VERSION 5.7 ;
  NOWIREEXTENSIONATPIN ON ;
  DIVIDERCHAR "/" ;
  BUSBITCHARS "[]" ;
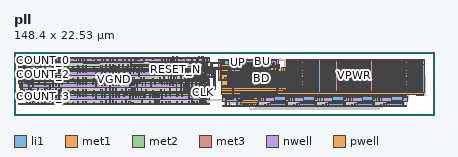
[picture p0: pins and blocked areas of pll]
MACRO pll
  CLASS BLOCK ;
  FOREIGN pll ;
  ORIGIN 0.000 0.000 ;
  SIZE 148.400 BY 22.530 ;
  PIN UP
    ANTENNAGATEAREA 1.341000 ;
    ANTENNADIFFAREA 0.537600 ;
    PORT
      LAYER li1 ;
        RECT 67.955 17.745 68.285 18.755 ;
        RECT 89.010 18.745 89.340 18.910 ;
        RECT 89.005 18.670 89.340 18.745 ;
        RECT 89.005 18.300 89.205 18.670 ;
        RECT 89.005 18.105 89.175 18.300 ;
        RECT 88.940 17.895 89.175 18.105 ;
        RECT 88.940 17.650 89.110 17.895 ;
        RECT 88.400 17.600 89.110 17.650 ;
        RECT 87.750 17.480 89.110 17.600 ;
        RECT 87.750 17.430 88.640 17.480 ;
        RECT 87.750 16.930 87.920 17.430 ;
        RECT 88.310 17.360 88.640 17.430 ;
        RECT 87.130 16.905 87.920 16.930 ;
        RECT 87.065 16.760 87.920 16.905 ;
        RECT 87.065 16.640 87.405 16.760 ;
        RECT 66.385 15.350 66.715 15.440 ;
        RECT 66.045 14.585 66.715 15.350 ;
        RECT 66.045 14.415 67.135 14.585 ;
        RECT 66.045 14.410 66.715 14.415 ;
        RECT 64.085 13.760 64.415 14.240 ;
        RECT 66.045 13.590 66.215 14.410 ;
        RECT 66.965 14.240 67.135 14.415 ;
        RECT 66.965 13.760 67.655 14.240 ;
        RECT 65.965 12.810 66.215 13.590 ;
        RECT 60.645 9.375 60.975 9.745 ;
      LAYER met1 ;
        RECT 88.920 18.415 89.270 18.690 ;
        RECT 67.945 18.240 68.300 18.255 ;
        RECT 67.900 18.010 68.345 18.240 ;
        RECT 67.945 17.980 68.300 18.010 ;
        RECT 66.400 15.105 66.690 15.140 ;
        RECT 64.110 14.935 66.690 15.105 ;
        RECT 64.110 14.275 64.280 14.935 ;
        RECT 66.400 14.900 66.690 14.935 ;
        RECT 64.085 13.985 64.315 14.275 ;
        RECT 67.075 14.030 67.365 14.065 ;
        RECT 67.050 13.740 67.390 14.030 ;
        RECT 67.075 13.705 67.365 13.740 ;
        RECT 61.665 13.105 61.925 13.190 ;
        RECT 67.130 13.105 67.300 13.705 ;
        RECT 61.665 12.935 67.300 13.105 ;
        RECT 61.665 12.860 61.925 12.935 ;
        RECT 60.725 9.545 60.955 9.665 ;
        RECT 61.665 9.545 61.925 9.615 ;
        RECT 60.725 9.375 61.925 9.545 ;
        RECT 61.665 9.285 61.925 9.375 ;
      LAYER met2 ;
        RECT 88.935 18.680 89.270 18.700 ;
        RECT 69.320 18.510 89.270 18.680 ;
        RECT 67.710 17.945 68.345 18.275 ;
        RECT 67.205 14.945 67.375 14.950 ;
        RECT 67.710 14.945 67.880 17.945 ;
        RECT 69.320 14.945 69.490 18.510 ;
        RECT 88.935 18.425 89.270 18.510 ;
        RECT 67.200 14.775 69.490 14.945 ;
        RECT 67.205 14.140 67.375 14.775 ;
        RECT 67.045 14.045 67.375 14.140 ;
        RECT 67.045 13.720 67.390 14.045 ;
        RECT 67.045 13.650 67.375 13.720 ;
        RECT 61.665 12.860 61.925 13.190 ;
        RECT 61.735 9.615 61.905 12.860 ;
        RECT 61.665 9.285 61.925 9.615 ;
    END
  END UP
  PIN BU
    ANTENNAGATEAREA 6.742000 ;
    ANTENNADIFFAREA 0.291200 ;
    PORT
      LAYER li1 ;
        RECT 81.520 17.395 81.740 18.460 ;
        RECT 84.715 17.475 84.885 19.080 ;
        RECT 84.645 17.395 84.990 17.475 ;
        RECT 81.520 17.305 84.990 17.395 ;
        RECT 81.520 17.215 84.885 17.305 ;
        RECT 81.520 16.115 81.740 17.215 ;
        RECT 91.070 17.200 91.600 17.380 ;
      LAYER met1 ;
        RECT 84.655 19.030 85.050 19.035 ;
        RECT 84.655 18.860 91.100 19.030 ;
        RECT 84.655 18.710 85.050 18.860 ;
        RECT 84.655 18.705 85.040 18.710 ;
        RECT 90.930 18.210 91.100 18.860 ;
        RECT 90.930 18.040 91.555 18.210 ;
        RECT 91.385 17.445 91.555 18.040 ;
        RECT 91.385 17.125 91.615 17.445 ;
    END
  END BU
  PIN BD
    ANTENNAGATEAREA 6.805000 ;
    ANTENNADIFFAREA 0.447500 ;
    PORT
      LAYER li1 ;
        RECT 77.255 17.395 77.465 18.960 ;
        RECT 77.115 17.215 80.195 17.395 ;
        RECT 77.115 16.930 77.285 17.215 ;
        RECT 76.175 16.760 77.285 16.930 ;
        RECT 76.175 15.710 76.375 16.760 ;
        RECT 81.415 15.740 81.760 15.910 ;
        RECT 75.930 15.530 76.375 15.710 ;
        RECT 84.790 15.630 84.960 15.975 ;
        RECT 93.030 15.740 93.260 15.885 ;
        RECT 92.955 15.565 93.335 15.740 ;
      LAYER met1 ;
        RECT 79.820 17.130 80.215 17.455 ;
        RECT 80.025 15.945 80.215 17.130 ;
        RECT 80.025 15.790 81.790 15.945 ;
        RECT 84.700 15.790 85.095 15.945 ;
        RECT 92.985 15.790 93.285 15.910 ;
        RECT 80.025 15.770 93.285 15.790 ;
        RECT 81.320 15.620 93.285 15.770 ;
    END
  END BD
  PIN RESET_OUT_N
    ANTENNAGATEAREA 0.232500 ;
    ANTENNADIFFAREA 0.543200 ;
    PORT
      LAYER li1 ;
        RECT 55.815 18.555 56.145 19.715 ;
        RECT 41.035 18.085 41.365 18.515 ;
        RECT 55.975 17.865 56.145 18.555 ;
        RECT 55.900 17.065 56.230 17.865 ;
      LAYER met1 ;
        RECT 55.890 19.415 56.220 19.675 ;
        RECT 55.975 18.870 56.145 19.415 ;
        RECT 55.890 18.610 56.220 18.870 ;
        RECT 41.010 18.160 41.270 18.490 ;
        RECT 41.100 17.690 41.270 18.160 ;
        RECT 55.935 17.690 56.195 17.815 ;
        RECT 41.100 17.520 56.195 17.690 ;
        RECT 55.935 17.485 56.195 17.520 ;
      LAYER met2 ;
        RECT 55.885 20.550 56.245 20.780 ;
        RECT 55.895 20.400 56.245 20.550 ;
        RECT 55.970 19.675 56.180 20.400 ;
        RECT 55.890 19.415 56.220 19.675 ;
        RECT 55.890 18.610 56.220 18.870 ;
        RECT 55.990 17.815 56.160 18.610 ;
        RECT 55.935 17.485 56.195 17.815 ;
    END
  END RESET_OUT_N
  PIN DOWN_N
    ANTENNAGATEAREA 0.252000 ;
    ANTENNADIFFAREA 0.541300 ;
    PORT
      LAYER li1 ;
        RECT 87.100 17.205 87.470 17.435 ;
        RECT 88.960 16.655 89.160 17.005 ;
        RECT 67.825 8.545 68.155 11.175 ;
      LAYER met1 ;
        RECT 87.125 17.345 87.480 17.440 ;
        RECT 87.125 17.175 87.745 17.345 ;
        RECT 87.585 16.515 87.745 17.175 ;
        RECT 88.905 16.685 89.255 16.970 ;
        RECT 88.920 16.515 89.080 16.685 ;
        RECT 87.585 16.345 89.100 16.515 ;
        RECT 67.830 10.335 68.150 10.655 ;
      LAYER met2 ;
        RECT 88.895 16.755 89.255 16.965 ;
        RECT 70.535 16.585 89.255 16.755 ;
        RECT 67.815 10.315 68.195 10.640 ;
        RECT 68.025 9.750 68.195 10.315 ;
        RECT 70.535 9.750 70.705 16.585 ;
        RECT 68.025 9.580 70.705 9.750 ;
    END
  END DOWN_N
  PIN UP_N
    ANTENNAGATEAREA 0.252000 ;
    ANTENNADIFFAREA 0.541300 ;
    PORT
      LAYER li1 ;
        RECT 90.620 17.110 90.850 17.480 ;
        RECT 88.430 16.690 88.700 17.020 ;
        RECT 67.825 12.810 68.155 15.440 ;
      LAYER met1 ;
        RECT 90.570 17.310 90.925 17.415 ;
        RECT 88.520 17.140 90.925 17.310 ;
        RECT 88.520 17.005 88.680 17.140 ;
        RECT 88.390 16.655 88.680 17.005 ;
        RECT 67.905 13.785 68.180 14.110 ;
      LAYER met2 ;
        RECT 69.900 18.095 89.245 18.265 ;
        RECT 67.870 13.785 68.210 14.110 ;
        RECT 68.000 13.500 68.170 13.785 ;
        RECT 69.900 13.500 70.070 18.095 ;
        RECT 89.075 17.430 89.245 18.095 ;
        RECT 89.075 17.260 90.895 17.430 ;
        RECT 90.555 17.155 90.895 17.260 ;
        RECT 68.000 13.330 70.070 13.500 ;
    END
  END UP_N
  PIN DOWN
    ANTENNAGATEAREA 1.341000 ;
    ANTENNADIFFAREA 0.537600 ;
    PORT
      LAYER li1 ;
        RECT 89.285 17.410 90.450 17.580 ;
        RECT 89.285 17.375 89.615 17.410 ;
        RECT 90.280 16.940 90.450 17.410 ;
        RECT 90.280 16.770 90.910 16.940 ;
        RECT 90.560 16.675 90.905 16.770 ;
        RECT 66.385 11.085 66.715 11.175 ;
        RECT 66.045 10.320 66.715 11.085 ;
        RECT 66.045 10.150 67.135 10.320 ;
        RECT 66.045 10.145 66.715 10.150 ;
        RECT 59.745 9.375 60.075 9.745 ;
        RECT 64.085 9.495 64.415 9.975 ;
        RECT 66.045 9.325 66.215 10.145 ;
        RECT 66.965 9.975 67.135 10.150 ;
        RECT 66.965 9.495 67.655 9.975 ;
        RECT 65.965 8.545 66.215 9.325 ;
        RECT 62.675 4.935 63.005 5.945 ;
      LAYER met1 ;
        RECT 90.560 16.660 90.910 16.945 ;
        RECT 66.400 10.840 66.690 10.875 ;
        RECT 59.755 10.380 60.015 10.710 ;
        RECT 64.110 10.670 66.690 10.840 ;
        RECT 59.800 9.665 59.970 10.380 ;
        RECT 64.110 10.010 64.280 10.670 ;
        RECT 66.400 10.635 66.690 10.670 ;
        RECT 64.085 9.720 64.315 10.010 ;
        RECT 67.070 9.775 67.370 9.780 ;
        RECT 59.765 9.375 59.995 9.665 ;
        RECT 67.030 9.470 67.395 9.775 ;
        RECT 67.070 9.460 67.370 9.470 ;
        RECT 61.665 8.840 61.925 8.925 ;
        RECT 67.130 8.840 67.300 9.460 ;
        RECT 61.665 8.670 67.300 8.840 ;
        RECT 61.665 8.595 61.925 8.670 ;
        RECT 62.585 5.650 63.040 5.955 ;
      LAYER met2 ;
        RECT 90.570 16.850 90.910 16.940 ;
        RECT 90.565 16.660 90.910 16.850 ;
        RECT 90.565 16.340 90.735 16.660 ;
        RECT 71.025 16.170 90.735 16.340 ;
        RECT 59.755 10.380 60.015 10.710 ;
        RECT 59.785 8.845 59.955 10.380 ;
        RECT 67.045 9.440 67.425 9.765 ;
        RECT 67.255 9.335 67.425 9.440 ;
        RECT 71.025 9.335 71.195 16.170 ;
        RECT 67.255 9.165 71.195 9.335 ;
        RECT 61.665 8.845 61.925 8.925 ;
        RECT 59.785 8.675 61.925 8.845 ;
        RECT 61.665 8.595 61.925 8.675 ;
        RECT 61.755 5.940 61.925 8.595 ;
        RECT 61.755 5.770 62.955 5.940 ;
        RECT 62.625 5.680 62.955 5.770 ;
    END
  END DOWN
  PIN CLK
    ANTENNADIFFAREA 0.924000 ;
    PORT
      LAYER li1 ;
        RECT 66.415 6.015 66.695 6.905 ;
        RECT 67.345 6.015 67.675 6.905 ;
        RECT 66.415 5.845 67.675 6.015 ;
        RECT 66.415 5.075 66.585 5.845 ;
        RECT 66.415 4.905 67.630 5.075 ;
        RECT 66.440 4.275 66.770 4.905 ;
        RECT 67.300 4.275 67.630 4.905 ;
      LAYER met1 ;
        RECT 66.370 4.680 66.890 4.985 ;
      LAYER met2 ;
        RECT 66.410 20.515 66.895 20.775 ;
        RECT 66.510 4.985 66.760 20.515 ;
        RECT 66.370 4.680 66.890 4.985 ;
    END
  END CLK
  PIN COUNT_0
    ANTENNAGATEAREA 0.540000 ;
    PORT
      LAYER li1 ;
        RECT 3.605 18.085 4.005 18.515 ;
        RECT 11.545 17.955 11.885 18.285 ;
        RECT 11.715 17.715 11.885 17.955 ;
        RECT 12.655 17.715 12.985 18.285 ;
        RECT 11.715 17.545 12.985 17.715 ;
      LAYER met1 ;
        RECT 3.710 18.235 4.040 18.535 ;
        RECT 12.725 17.945 13.055 18.245 ;
      LAYER met2 ;
        RECT 3.690 20.540 4.060 20.920 ;
        RECT 3.890 19.015 4.060 20.540 ;
        RECT 3.890 18.845 12.875 19.015 ;
        RECT 3.890 18.570 4.060 18.845 ;
        RECT 3.690 18.190 4.060 18.570 ;
        RECT 12.705 18.280 12.875 18.845 ;
        RECT 12.705 17.900 13.075 18.280 ;
    END
  END COUNT_0
  PIN COUNT_1
    ANTENNAGATEAREA 0.540000 ;
    PORT
      LAYER li1 ;
        RECT 3.105 18.085 3.435 18.885 ;
        RECT 11.545 13.680 11.885 14.010 ;
        RECT 11.715 13.440 11.885 13.680 ;
        RECT 12.655 13.440 12.985 14.010 ;
        RECT 11.715 13.270 12.985 13.440 ;
      LAYER met1 ;
        RECT 3.100 18.050 3.430 18.350 ;
        RECT 3.280 15.205 12.880 15.375 ;
        RECT 3.280 14.920 3.660 15.205 ;
        RECT 12.710 13.920 12.880 15.205 ;
        RECT 12.710 13.590 12.970 13.920 ;
      LAYER met2 ;
        RECT 3.080 20.535 3.450 20.915 ;
        RECT 3.165 18.385 3.335 20.535 ;
        RECT 3.080 18.005 3.450 18.385 ;
        RECT 3.280 15.290 3.450 18.005 ;
        RECT 3.280 14.920 3.660 15.290 ;
    END
  END COUNT_1
  PIN COUNT_3
    ANTENNAGATEAREA 0.540000 ;
    PORT
      LAYER li1 ;
        RECT 1.685 17.915 2.100 18.285 ;
        RECT 11.545 5.145 11.885 5.475 ;
        RECT 11.715 4.905 11.885 5.145 ;
        RECT 12.655 4.905 12.985 5.475 ;
        RECT 11.715 4.735 12.985 4.905 ;
      LAYER met1 ;
        RECT 1.725 17.975 2.055 18.275 ;
        RECT 4.015 6.570 4.395 6.715 ;
        RECT 4.015 6.400 12.880 6.570 ;
        RECT 4.015 6.345 4.395 6.400 ;
        RECT 12.710 5.385 12.880 6.400 ;
        RECT 12.710 5.055 12.970 5.385 ;
      LAYER met2 ;
        RECT 1.705 20.535 2.075 20.915 ;
        RECT 1.710 20.530 2.070 20.535 ;
        RECT 1.890 18.310 2.060 20.530 ;
        RECT 1.705 17.930 2.075 18.310 ;
        RECT 1.905 12.570 2.075 17.930 ;
        RECT 1.905 12.400 2.835 12.570 ;
        RECT 2.665 6.715 2.835 12.400 ;
        RECT 2.665 6.545 4.395 6.715 ;
        RECT 4.015 6.345 4.395 6.545 ;
    END
  END COUNT_3
  PIN COUNT_2
    ANTENNAGATEAREA 0.540000 ;
    PORT
      LAYER li1 ;
        RECT 2.535 18.085 2.875 19.625 ;
        RECT 11.545 9.415 11.885 9.745 ;
        RECT 11.715 9.175 11.885 9.415 ;
        RECT 12.655 9.175 12.985 9.745 ;
        RECT 11.715 9.005 12.985 9.175 ;
      LAYER met1 ;
        RECT 2.615 18.375 2.785 18.385 ;
        RECT 2.485 18.075 2.815 18.375 ;
        RECT 2.615 17.645 2.785 18.075 ;
        RECT 2.615 17.475 5.210 17.645 ;
        RECT 4.830 17.275 5.210 17.475 ;
        RECT 4.895 10.955 5.265 11.015 ;
        RECT 4.895 10.830 7.685 10.955 ;
        RECT 4.895 10.785 12.880 10.830 ;
        RECT 4.895 10.635 5.265 10.785 ;
        RECT 7.385 10.660 12.880 10.785 ;
        RECT 12.710 9.635 12.880 10.660 ;
        RECT 12.710 9.305 12.970 9.635 ;
      LAYER met2 ;
        RECT 2.465 20.530 2.835 20.910 ;
        RECT 2.550 18.410 2.720 20.530 ;
        RECT 2.465 18.030 2.835 18.410 ;
        RECT 4.830 17.275 5.210 17.645 ;
        RECT 5.015 11.015 5.185 17.275 ;
        RECT 4.895 10.635 5.265 11.015 ;
    END
  END COUNT_2
  PIN RESET_N
    ANTENNAGATEAREA 0.279000 ;
    PORT
      LAYER li1 ;
        RECT 56.885 13.760 57.575 14.240 ;
      LAYER met1 ;
        RECT 57.565 19.415 57.895 19.675 ;
        RECT 57.650 18.870 57.820 19.415 ;
        RECT 57.565 18.610 57.895 18.870 ;
        RECT 56.870 13.980 57.130 14.310 ;
      LAYER met2 ;
        RECT 57.560 20.550 57.920 20.780 ;
        RECT 57.570 20.400 57.920 20.550 ;
        RECT 57.645 19.675 57.855 20.400 ;
        RECT 57.565 19.415 57.895 19.675 ;
        RECT 57.565 18.610 57.895 18.870 ;
        RECT 57.625 17.965 57.795 18.610 ;
        RECT 56.915 17.820 57.795 17.965 ;
        RECT 56.915 14.310 57.085 17.820 ;
        RECT 56.870 13.980 57.130 14.310 ;
    END
  END RESET_N
  PIN VCTRL
    ANTENNAGATEAREA 1.241700 ;
    ANTENNADIFFAREA 1.913700 ;
    PORT
      LAYER li1 ;
        RECT 91.770 17.330 91.945 18.710 ;
        RECT 92.610 17.670 92.785 19.005 ;
        RECT 92.610 17.340 93.880 17.670 ;
        RECT 92.610 17.330 92.810 17.340 ;
        RECT 91.770 17.160 92.810 17.330 ;
        RECT 91.770 15.905 91.945 17.160 ;
        RECT 92.610 16.600 92.785 17.160 ;
        RECT 92.610 16.135 93.090 16.600 ;
        RECT 93.520 16.495 93.880 17.340 ;
        RECT 92.610 15.810 92.795 16.135 ;
        RECT 79.120 5.355 79.890 6.230 ;
        RECT 79.120 5.020 80.405 5.355 ;
        RECT 79.120 3.430 79.890 5.020 ;
      LAYER met1 ;
        RECT 92.530 17.140 92.880 17.425 ;
        RECT 86.655 12.500 86.795 14.165 ;
        RECT 87.215 12.500 87.355 14.165 ;
        RECT 87.775 12.500 87.915 14.165 ;
        RECT 88.145 12.500 88.415 14.165 ;
        RECT 88.645 12.500 88.785 14.165 ;
        RECT 89.205 12.500 89.345 14.165 ;
        RECT 89.765 12.500 89.905 14.165 ;
        RECT 86.655 12.180 89.905 12.500 ;
        RECT 86.655 10.515 86.795 12.180 ;
        RECT 87.215 10.515 87.355 12.180 ;
        RECT 87.775 10.515 87.915 12.180 ;
        RECT 88.145 10.515 88.415 12.180 ;
        RECT 88.645 10.515 88.785 12.180 ;
        RECT 89.205 10.515 89.345 12.180 ;
        RECT 89.765 10.515 89.905 12.180 ;
        RECT 91.380 12.500 91.520 14.165 ;
        RECT 91.940 12.500 92.080 14.165 ;
        RECT 92.500 12.500 92.640 14.165 ;
        RECT 92.870 12.500 93.140 14.165 ;
        RECT 93.370 12.500 93.510 14.165 ;
        RECT 93.930 12.500 94.070 14.165 ;
        RECT 94.490 12.500 94.630 14.165 ;
        RECT 91.380 12.180 94.630 12.500 ;
        RECT 91.380 10.515 91.520 12.180 ;
        RECT 91.940 10.515 92.080 12.180 ;
        RECT 92.500 10.515 92.640 12.180 ;
        RECT 92.870 10.515 93.140 12.180 ;
        RECT 93.370 10.515 93.510 12.180 ;
        RECT 93.930 10.515 94.070 12.180 ;
        RECT 94.490 10.515 94.630 12.180 ;
        RECT 80.155 5.375 80.470 5.410 ;
        RECT 80.155 5.070 80.475 5.375 ;
      LAYER met2 ;
        RECT 92.550 17.425 93.135 17.430 ;
        RECT 92.465 17.140 93.135 17.425 ;
        RECT 92.550 17.130 93.135 17.140 ;
        RECT 92.870 14.635 93.135 17.130 ;
        RECT 88.145 14.165 88.415 14.635 ;
        RECT 92.870 14.165 93.140 14.635 ;
        RECT 86.560 14.025 90.000 14.165 ;
        RECT 91.285 14.025 94.725 14.165 ;
        RECT 88.140 13.605 88.420 14.025 ;
        RECT 92.865 13.605 93.145 14.025 ;
        RECT 86.560 13.465 90.000 13.605 ;
        RECT 91.285 13.465 94.725 13.605 ;
        RECT 88.140 13.045 88.420 13.465 ;
        RECT 92.865 13.045 93.145 13.465 ;
        RECT 86.560 12.905 90.000 13.045 ;
        RECT 91.285 12.905 94.725 13.045 ;
        RECT 88.140 12.480 88.420 12.905 ;
        RECT 92.865 12.480 93.145 12.905 ;
        RECT 86.460 12.475 90.100 12.480 ;
        RECT 91.185 12.475 94.825 12.480 ;
        RECT 86.090 12.205 95.195 12.475 ;
        RECT 86.460 12.200 90.100 12.205 ;
        RECT 91.185 12.200 94.825 12.205 ;
        RECT 88.140 11.775 88.420 12.200 ;
        RECT 92.865 11.775 93.145 12.200 ;
        RECT 86.560 11.635 90.000 11.775 ;
        RECT 91.285 11.635 94.725 11.775 ;
        RECT 88.140 11.215 88.420 11.635 ;
        RECT 92.865 11.215 93.145 11.635 ;
        RECT 86.560 11.075 90.000 11.215 ;
        RECT 91.285 11.075 94.725 11.215 ;
        RECT 88.140 10.655 88.420 11.075 ;
        RECT 92.865 10.655 93.145 11.075 ;
        RECT 86.560 10.515 90.000 10.655 ;
        RECT 91.285 10.515 94.725 10.655 ;
        RECT 88.145 10.045 88.415 10.515 ;
        RECT 92.870 8.005 93.140 10.515 ;
        RECT 92.870 7.960 93.145 8.005 ;
        RECT 92.875 7.720 93.145 7.960 ;
        RECT 80.080 7.550 93.145 7.720 ;
        RECT 80.080 5.385 80.250 7.550 ;
        RECT 80.080 5.100 80.515 5.385 ;
        RECT 80.130 5.065 80.515 5.100 ;
      LAYER met3 ;
        RECT 86.720 12.505 87.020 14.005 ;
        RECT 88.115 12.505 88.445 14.005 ;
        RECT 89.540 12.505 89.840 14.005 ;
        RECT 86.720 12.175 89.840 12.505 ;
        RECT 86.720 10.675 87.020 12.175 ;
        RECT 88.115 10.675 88.445 12.175 ;
        RECT 89.540 10.675 89.840 12.175 ;
        RECT 91.445 12.505 91.745 14.005 ;
        RECT 92.840 12.505 93.170 14.005 ;
        RECT 94.265 12.505 94.565 14.005 ;
        RECT 91.445 12.175 94.565 12.505 ;
        RECT 91.445 10.675 91.745 12.175 ;
        RECT 92.840 10.675 93.170 12.175 ;
        RECT 94.265 10.675 94.565 12.175 ;
    END
  END VCTRL
  PIN REFCLK
    ANTENNAGATEAREA 0.558000 ;
    PORT
      LAYER li1 ;
        RECT 66.965 17.915 67.445 18.285 ;
        RECT 64.945 13.760 65.275 14.240 ;
      LAYER met1 ;
        RECT 65.150 18.240 65.505 18.255 ;
        RECT 67.195 18.240 67.435 18.255 ;
        RECT 65.135 18.205 65.580 18.240 ;
        RECT 67.035 18.205 67.480 18.240 ;
        RECT 65.135 18.035 67.480 18.205 ;
        RECT 65.135 18.010 65.580 18.035 ;
        RECT 67.035 18.010 67.480 18.035 ;
        RECT 65.150 17.980 65.505 18.010 ;
        RECT 67.195 17.995 67.435 18.010 ;
        RECT 64.930 14.240 65.285 14.255 ;
        RECT 64.885 14.010 65.330 14.240 ;
        RECT 64.930 13.980 65.285 14.010 ;
      LAYER met2 ;
        RECT 65.045 20.770 65.530 20.775 ;
        RECT 65.040 20.515 65.530 20.770 ;
        RECT 65.040 20.510 65.525 20.515 ;
        RECT 65.100 18.275 65.270 20.510 ;
        RECT 65.100 17.945 65.595 18.275 ;
        RECT 65.100 14.290 65.270 17.945 ;
        RECT 64.860 13.960 65.350 14.290 ;
    END
  END REFCLK
  PIN VPWR
    USE POWER ;
    PORT
      LAYER nwell ;
        RECT 1.850 9.855 68.950 11.715 ;
        RECT 24.575 9.815 30.220 9.855 ;
        RECT 28.700 9.750 30.220 9.815 ;
        RECT 47.300 9.815 52.945 9.855 ;
        RECT 47.300 9.750 48.820 9.815 ;
      LAYER li1 ;
        RECT 2.040 11.440 68.760 11.610 ;
        RECT 2.295 10.015 2.625 11.440 ;
        RECT 5.035 10.145 5.365 11.440 ;
        RECT 6.685 10.135 7.015 11.440 ;
        RECT 8.615 10.845 9.055 11.440 ;
        RECT 10.850 10.595 11.180 11.440 ;
        RECT 13.495 10.015 13.825 11.440 ;
        RECT 14.610 10.400 14.910 11.440 ;
        RECT 15.620 10.225 15.950 11.440 ;
        RECT 16.630 10.715 16.960 11.440 ;
        RECT 19.030 11.160 19.360 11.440 ;
        RECT 21.250 11.160 21.585 11.440 ;
        RECT 22.345 10.485 22.515 11.440 ;
        RECT 23.275 10.715 23.525 11.440 ;
        RECT 24.255 10.845 24.505 11.440 ;
        RECT 25.185 10.845 25.515 11.440 ;
        RECT 27.600 10.950 27.945 11.440 ;
        RECT 28.940 9.935 29.190 11.440 ;
        RECT 30.995 10.530 31.220 11.440 ;
        RECT 31.970 10.300 32.185 11.440 ;
        RECT 33.770 10.015 34.065 11.440 ;
        RECT 34.770 10.400 35.070 11.440 ;
        RECT 35.840 10.385 36.170 11.440 ;
        RECT 36.875 10.385 37.210 11.440 ;
        RECT 38.705 10.845 39.145 11.440 ;
        RECT 40.745 10.135 41.075 11.440 ;
        RECT 41.490 10.400 41.790 11.440 ;
        RECT 41.970 10.400 42.270 11.440 ;
        RECT 42.450 10.400 42.750 11.440 ;
        RECT 43.455 10.015 43.750 11.440 ;
        RECT 45.335 10.300 45.550 11.440 ;
        RECT 46.300 10.530 46.525 11.440 ;
        RECT 48.330 9.935 48.580 11.440 ;
        RECT 49.575 10.950 49.920 11.440 ;
        RECT 52.005 10.845 52.335 11.440 ;
        RECT 53.015 10.845 53.265 11.440 ;
        RECT 53.995 10.715 54.245 11.440 ;
        RECT 55.040 10.385 55.370 11.440 ;
        RECT 56.075 10.385 56.410 11.440 ;
        RECT 57.245 10.145 57.575 11.440 ;
        RECT 58.685 10.145 59.015 11.440 ;
        RECT 59.745 10.015 60.075 11.440 ;
        RECT 60.645 10.015 60.975 11.440 ;
        RECT 61.195 10.145 61.525 11.440 ;
        RECT 62.635 10.145 62.965 11.440 ;
        RECT 64.075 10.145 64.405 11.440 ;
        RECT 65.515 10.145 65.845 11.440 ;
        RECT 67.325 10.145 67.655 11.440 ;
        RECT 68.370 10.400 68.670 11.440 ;
      LAYER met1 ;
        RECT 2.040 11.280 68.760 11.770 ;
      LAYER met2 ;
        RECT 2.040 11.285 2.520 11.770 ;
        RECT 2.975 11.280 3.885 11.770 ;
        RECT 4.375 11.290 4.875 11.775 ;
        RECT 6.495 11.290 10.640 11.770 ;
        RECT 11.185 11.270 22.615 11.770 ;
        RECT 23.160 11.295 25.095 11.670 ;
        RECT 25.585 11.275 30.910 11.770 ;
        RECT 31.470 11.310 36.105 11.770 ;
        RECT 36.570 11.290 38.980 11.765 ;
        RECT 40.195 11.310 43.265 11.780 ;
        RECT 44.810 11.295 51.555 11.765 ;
        RECT 52.015 11.290 53.755 11.770 ;
        RECT 54.240 11.295 54.865 11.770 ;
        RECT 55.370 11.280 55.790 11.775 ;
        RECT 56.295 11.270 56.790 11.765 ;
        RECT 57.335 11.290 58.030 11.780 ;
        RECT 58.685 11.285 59.165 11.770 ;
        RECT 59.655 11.275 60.550 11.765 ;
        RECT 62.080 11.300 63.985 11.765 ;
        RECT 64.490 11.295 66.345 11.770 ;
        RECT 66.915 11.295 68.735 11.760 ;
      LAYER met3 ;
        RECT 2.800 11.765 68.980 11.775 ;
        RECT 2.055 11.760 68.980 11.765 ;
        RECT 1.560 11.285 68.980 11.760 ;
        RECT 1.560 11.280 68.765 11.285 ;
    END
    PORT
      LAYER nwell ;
        RECT 2.330 14.120 68.950 15.980 ;
        RECT 24.575 14.080 30.220 14.120 ;
        RECT 45.215 14.080 50.860 14.120 ;
        RECT 28.700 14.015 30.220 14.080 ;
        RECT 49.340 14.015 50.860 14.080 ;
      LAYER li1 ;
        RECT 2.520 15.705 68.760 15.875 ;
        RECT 3.005 14.410 3.335 15.705 ;
        RECT 5.125 14.750 5.745 15.705 ;
        RECT 6.685 14.400 7.015 15.705 ;
        RECT 8.615 15.110 9.055 15.705 ;
        RECT 10.850 14.860 11.180 15.705 ;
        RECT 13.495 14.280 13.825 15.705 ;
        RECT 14.610 14.665 14.910 15.705 ;
        RECT 15.620 14.490 15.950 15.705 ;
        RECT 16.630 14.980 16.960 15.705 ;
        RECT 19.030 15.425 19.360 15.705 ;
        RECT 21.250 15.425 21.585 15.705 ;
        RECT 22.345 14.750 22.515 15.705 ;
        RECT 23.275 14.980 23.525 15.705 ;
        RECT 24.255 15.110 24.505 15.705 ;
        RECT 25.185 15.110 25.515 15.705 ;
        RECT 27.600 15.215 27.945 15.705 ;
        RECT 28.940 14.200 29.190 15.705 ;
        RECT 30.995 14.795 31.220 15.705 ;
        RECT 31.970 14.565 32.185 15.705 ;
        RECT 33.770 14.280 34.065 15.705 ;
        RECT 34.770 14.665 35.070 15.705 ;
        RECT 35.840 14.650 36.170 15.705 ;
        RECT 36.875 14.650 37.210 15.705 ;
        RECT 38.705 15.110 39.145 15.705 ;
        RECT 40.745 14.400 41.075 15.705 ;
        RECT 42.050 14.750 42.315 15.705 ;
        RECT 43.135 15.110 43.470 15.705 ;
        RECT 43.915 14.980 44.165 15.705 ;
        RECT 44.895 15.110 45.145 15.705 ;
        RECT 45.825 15.110 46.155 15.705 ;
        RECT 48.240 15.215 48.585 15.705 ;
        RECT 43.925 13.460 44.320 14.655 ;
        RECT 49.580 14.200 49.830 15.705 ;
        RECT 51.635 14.795 51.860 15.705 ;
        RECT 52.610 14.565 52.825 15.705 ;
        RECT 54.410 14.280 54.705 15.705 ;
        RECT 56.315 14.410 56.645 15.705 ;
        RECT 57.245 14.410 57.575 15.705 ;
        RECT 58.685 14.410 59.015 15.705 ;
        RECT 60.125 14.410 60.455 15.705 ;
        RECT 61.195 14.410 61.525 15.705 ;
        RECT 62.635 14.410 62.965 15.705 ;
        RECT 64.075 14.410 64.405 15.705 ;
        RECT 65.515 14.410 65.845 15.705 ;
        RECT 67.325 14.410 67.655 15.705 ;
        RECT 68.370 14.665 68.670 15.705 ;
      LAYER met1 ;
        RECT 2.800 16.035 68.970 16.050 ;
        RECT 2.520 15.550 68.970 16.035 ;
        RECT 2.520 15.545 68.760 15.550 ;
        RECT 44.015 14.695 44.185 15.545 ;
        RECT 43.975 14.365 44.235 14.695 ;
      LAYER met2 ;
        RECT 2.530 15.550 3.080 16.030 ;
        RECT 4.450 15.555 4.855 16.015 ;
        RECT 5.930 15.545 8.790 16.045 ;
        RECT 9.340 15.535 10.650 16.020 ;
        RECT 11.115 15.545 22.560 16.035 ;
        RECT 23.230 15.540 25.125 16.040 ;
        RECT 25.675 15.555 30.930 16.045 ;
        RECT 31.390 15.560 34.210 16.030 ;
        RECT 34.680 15.550 36.100 16.030 ;
        RECT 36.570 15.550 39.525 16.035 ;
        RECT 40.185 15.545 42.265 16.035 ;
        RECT 42.880 15.560 56.175 16.030 ;
        RECT 57.290 15.555 58.060 16.035 ;
        RECT 58.725 15.535 63.890 16.045 ;
        RECT 64.550 15.555 64.935 16.035 ;
        RECT 65.470 15.550 66.310 16.035 ;
        RECT 67.085 15.555 67.565 16.030 ;
        RECT 68.200 15.530 68.770 16.020 ;
      LAYER met3 ;
        RECT 2.800 16.030 68.980 16.050 ;
        RECT 1.560 16.020 68.980 16.030 ;
        RECT 1.560 15.550 69.115 16.020 ;
        RECT 2.515 15.545 69.115 15.550 ;
        RECT 2.865 15.535 69.115 15.545 ;
    END
    PORT
      LAYER pwell ;
        RECT 75.055 16.920 75.985 16.925 ;
        RECT 77.685 16.920 80.465 17.105 ;
        RECT 75.055 16.700 80.465 16.920 ;
        RECT 81.910 16.700 86.790 17.105 ;
        RECT 75.055 16.625 86.790 16.700 ;
        RECT 91.180 16.625 92.950 17.030 ;
        RECT 75.055 15.450 88.535 16.625 ;
        RECT 89.435 15.450 92.950 16.625 ;
        RECT 94.600 15.450 95.950 16.720 ;
        RECT 73.870 15.205 96.015 15.450 ;
        RECT 74.940 14.870 95.825 15.205 ;
        RECT 95.395 7.995 95.825 14.870 ;
        RECT 107.730 7.895 108.160 19.690 ;
        RECT 119.985 7.895 120.415 19.690 ;
        RECT 132.245 7.895 132.675 19.690 ;
        RECT 144.485 7.905 144.915 17.965 ;
      LAYER li1 ;
        RECT 96.110 19.325 107.520 19.655 ;
        RECT 96.110 18.795 96.440 19.325 ;
        RECT 107.190 18.795 107.520 19.325 ;
        RECT 96.110 18.625 101.510 18.795 ;
        RECT 102.120 18.625 107.520 18.795 ;
        RECT 96.110 18.095 96.440 18.625 ;
        RECT 107.190 18.095 107.520 18.625 ;
        RECT 96.110 17.925 101.510 18.095 ;
        RECT 102.120 17.925 107.520 18.095 ;
        RECT 76.615 15.290 76.785 16.590 ;
        RECT 77.855 15.290 80.295 17.035 ;
        RECT 80.480 16.600 80.650 17.510 ;
        RECT 96.110 17.395 96.440 17.925 ;
        RECT 107.190 17.395 107.520 17.925 ;
        RECT 96.110 17.225 101.510 17.395 ;
        RECT 102.120 17.225 107.520 17.395 ;
        RECT 80.480 16.150 80.935 16.600 ;
        RECT 80.540 15.290 80.935 16.150 ;
        RECT 82.080 15.290 84.530 17.045 ;
        RECT 96.110 16.695 96.440 17.225 ;
        RECT 107.190 16.695 107.520 17.225 ;
        RECT 96.110 16.525 101.510 16.695 ;
        RECT 102.120 16.525 107.520 16.695 ;
        RECT 87.350 15.290 87.945 16.460 ;
        RECT 90.025 15.290 90.615 16.460 ;
        RECT 95.185 15.345 95.370 16.480 ;
        RECT 96.110 15.995 96.440 16.525 ;
        RECT 107.190 15.995 107.520 16.525 ;
        RECT 96.110 15.825 101.510 15.995 ;
        RECT 102.120 15.825 107.520 15.995 ;
        RECT 96.110 15.345 96.440 15.825 ;
        RECT 95.130 15.295 96.440 15.345 ;
        RECT 107.190 15.295 107.520 15.825 ;
        RECT 95.130 15.290 101.510 15.295 ;
        RECT 73.380 15.125 101.510 15.290 ;
        RECT 102.120 15.125 107.520 15.295 ;
        RECT 73.380 14.960 96.440 15.125 ;
        RECT 95.130 14.950 96.440 14.960 ;
        RECT 74.400 12.620 75.025 13.310 ;
        RECT 75.295 10.045 79.675 14.635 ;
        RECT 80.165 10.045 84.545 14.635 ;
        RECT 86.090 10.045 90.470 14.635 ;
        RECT 90.815 10.045 95.195 14.635 ;
        RECT 96.110 14.595 96.440 14.950 ;
        RECT 107.190 14.595 107.520 15.125 ;
        RECT 95.415 8.125 95.830 14.520 ;
        RECT 96.110 14.425 101.510 14.595 ;
        RECT 102.120 14.425 107.520 14.595 ;
        RECT 96.110 13.895 96.440 14.425 ;
        RECT 107.190 13.895 107.520 14.425 ;
        RECT 96.110 13.725 101.510 13.895 ;
        RECT 102.120 13.725 107.520 13.895 ;
        RECT 96.110 13.195 96.440 13.725 ;
        RECT 107.190 13.195 107.520 13.725 ;
        RECT 96.110 13.025 101.510 13.195 ;
        RECT 102.120 13.025 107.520 13.195 ;
        RECT 96.110 12.495 96.440 13.025 ;
        RECT 107.190 12.495 107.520 13.025 ;
        RECT 96.110 12.325 101.510 12.495 ;
        RECT 102.120 12.325 107.520 12.495 ;
        RECT 96.110 11.795 96.440 12.325 ;
        RECT 107.190 11.795 107.520 12.325 ;
        RECT 96.110 11.625 101.510 11.795 ;
        RECT 102.120 11.625 107.520 11.795 ;
        RECT 96.110 11.095 96.440 11.625 ;
        RECT 107.190 11.095 107.520 11.625 ;
        RECT 96.110 10.925 101.510 11.095 ;
        RECT 102.120 10.925 107.520 11.095 ;
        RECT 96.110 10.395 96.440 10.925 ;
        RECT 107.190 10.395 107.520 10.925 ;
        RECT 96.110 10.225 101.510 10.395 ;
        RECT 102.120 10.225 107.520 10.395 ;
        RECT 96.110 9.695 96.440 10.225 ;
        RECT 107.190 9.695 107.520 10.225 ;
        RECT 96.110 9.525 101.510 9.695 ;
        RECT 102.120 9.525 107.520 9.695 ;
        RECT 96.110 8.995 96.440 9.525 ;
        RECT 107.190 8.995 107.520 9.525 ;
        RECT 96.110 8.825 101.510 8.995 ;
        RECT 102.120 8.825 107.520 8.995 ;
        RECT 96.110 8.295 96.440 8.825 ;
        RECT 107.190 8.295 107.520 8.825 ;
        RECT 96.110 7.965 107.520 8.295 ;
        RECT 107.750 8.025 108.165 19.560 ;
        RECT 108.335 19.325 119.745 19.655 ;
        RECT 108.335 18.795 108.665 19.325 ;
        RECT 119.415 18.795 119.745 19.325 ;
        RECT 108.335 18.625 113.735 18.795 ;
        RECT 114.345 18.625 119.745 18.795 ;
        RECT 108.335 18.095 108.665 18.625 ;
        RECT 119.415 18.095 119.745 18.625 ;
        RECT 108.335 17.925 113.735 18.095 ;
        RECT 114.345 17.925 119.745 18.095 ;
        RECT 108.335 17.395 108.665 17.925 ;
        RECT 119.415 17.395 119.745 17.925 ;
        RECT 108.335 17.225 113.735 17.395 ;
        RECT 114.345 17.225 119.745 17.395 ;
        RECT 108.335 16.695 108.665 17.225 ;
        RECT 119.415 16.695 119.745 17.225 ;
        RECT 108.335 16.525 113.735 16.695 ;
        RECT 114.345 16.525 119.745 16.695 ;
        RECT 108.335 15.995 108.665 16.525 ;
        RECT 119.415 15.995 119.745 16.525 ;
        RECT 108.335 15.825 113.735 15.995 ;
        RECT 114.345 15.825 119.745 15.995 ;
        RECT 108.335 15.295 108.665 15.825 ;
        RECT 119.415 15.295 119.745 15.825 ;
        RECT 108.335 15.125 113.735 15.295 ;
        RECT 114.345 15.125 119.745 15.295 ;
        RECT 108.335 14.595 108.665 15.125 ;
        RECT 119.415 14.595 119.745 15.125 ;
        RECT 108.335 14.425 113.735 14.595 ;
        RECT 114.345 14.425 119.745 14.595 ;
        RECT 108.335 13.895 108.665 14.425 ;
        RECT 119.415 13.895 119.745 14.425 ;
        RECT 108.335 13.725 113.735 13.895 ;
        RECT 114.345 13.725 119.745 13.895 ;
        RECT 108.335 13.195 108.665 13.725 ;
        RECT 119.415 13.195 119.745 13.725 ;
        RECT 108.335 13.025 113.735 13.195 ;
        RECT 114.345 13.025 119.745 13.195 ;
        RECT 108.335 12.495 108.665 13.025 ;
        RECT 119.415 12.495 119.745 13.025 ;
        RECT 108.335 12.325 113.735 12.495 ;
        RECT 114.345 12.325 119.745 12.495 ;
        RECT 108.335 11.795 108.665 12.325 ;
        RECT 119.415 11.795 119.745 12.325 ;
        RECT 108.335 11.625 113.735 11.795 ;
        RECT 114.345 11.625 119.745 11.795 ;
        RECT 108.335 11.095 108.665 11.625 ;
        RECT 119.415 11.095 119.745 11.625 ;
        RECT 108.335 10.925 113.735 11.095 ;
        RECT 114.345 10.925 119.745 11.095 ;
        RECT 108.335 10.395 108.665 10.925 ;
        RECT 119.415 10.395 119.745 10.925 ;
        RECT 108.335 10.225 113.735 10.395 ;
        RECT 114.345 10.225 119.745 10.395 ;
        RECT 108.335 9.695 108.665 10.225 ;
        RECT 119.415 9.695 119.745 10.225 ;
        RECT 108.335 9.525 113.735 9.695 ;
        RECT 114.345 9.525 119.745 9.695 ;
        RECT 108.335 8.995 108.665 9.525 ;
        RECT 119.415 8.995 119.745 9.525 ;
        RECT 108.335 8.825 113.735 8.995 ;
        RECT 114.345 8.825 119.745 8.995 ;
        RECT 108.335 8.295 108.665 8.825 ;
        RECT 119.415 8.295 119.745 8.825 ;
        RECT 108.335 7.965 119.745 8.295 ;
        RECT 120.005 8.025 120.420 19.560 ;
        RECT 120.600 19.325 132.010 19.655 ;
        RECT 120.600 18.795 120.930 19.325 ;
        RECT 131.680 18.795 132.010 19.325 ;
        RECT 120.600 18.625 126.000 18.795 ;
        RECT 126.610 18.625 132.010 18.795 ;
        RECT 120.600 18.095 120.930 18.625 ;
        RECT 131.680 18.095 132.010 18.625 ;
        RECT 120.600 17.925 126.000 18.095 ;
        RECT 126.610 17.925 132.010 18.095 ;
        RECT 120.600 17.395 120.930 17.925 ;
        RECT 131.680 17.395 132.010 17.925 ;
        RECT 120.600 17.225 126.000 17.395 ;
        RECT 126.610 17.225 132.010 17.395 ;
        RECT 120.600 16.695 120.930 17.225 ;
        RECT 131.680 16.695 132.010 17.225 ;
        RECT 120.600 16.525 126.000 16.695 ;
        RECT 126.610 16.525 132.010 16.695 ;
        RECT 120.600 15.995 120.930 16.525 ;
        RECT 131.680 15.995 132.010 16.525 ;
        RECT 120.600 15.825 126.000 15.995 ;
        RECT 126.610 15.825 132.010 15.995 ;
        RECT 120.600 15.295 120.930 15.825 ;
        RECT 131.680 15.295 132.010 15.825 ;
        RECT 120.600 15.125 126.000 15.295 ;
        RECT 126.610 15.125 132.010 15.295 ;
        RECT 120.600 14.595 120.930 15.125 ;
        RECT 131.680 14.595 132.010 15.125 ;
        RECT 120.600 14.425 126.000 14.595 ;
        RECT 126.610 14.425 132.010 14.595 ;
        RECT 120.600 13.895 120.930 14.425 ;
        RECT 131.680 13.895 132.010 14.425 ;
        RECT 120.600 13.725 126.000 13.895 ;
        RECT 126.610 13.725 132.010 13.895 ;
        RECT 120.600 13.195 120.930 13.725 ;
        RECT 131.680 13.195 132.010 13.725 ;
        RECT 120.600 13.025 126.000 13.195 ;
        RECT 126.610 13.025 132.010 13.195 ;
        RECT 120.600 12.495 120.930 13.025 ;
        RECT 131.680 12.495 132.010 13.025 ;
        RECT 120.600 12.325 126.000 12.495 ;
        RECT 126.610 12.325 132.010 12.495 ;
        RECT 120.600 11.795 120.930 12.325 ;
        RECT 131.680 11.795 132.010 12.325 ;
        RECT 120.600 11.625 126.000 11.795 ;
        RECT 126.610 11.625 132.010 11.795 ;
        RECT 120.600 11.095 120.930 11.625 ;
        RECT 131.680 11.095 132.010 11.625 ;
        RECT 120.600 10.925 126.000 11.095 ;
        RECT 126.610 10.925 132.010 11.095 ;
        RECT 120.600 10.395 120.930 10.925 ;
        RECT 131.680 10.395 132.010 10.925 ;
        RECT 120.600 10.225 126.000 10.395 ;
        RECT 126.610 10.225 132.010 10.395 ;
        RECT 120.600 9.695 120.930 10.225 ;
        RECT 131.680 9.695 132.010 10.225 ;
        RECT 120.600 9.525 126.000 9.695 ;
        RECT 126.610 9.525 132.010 9.695 ;
        RECT 120.600 8.995 120.930 9.525 ;
        RECT 131.680 8.995 132.010 9.525 ;
        RECT 120.600 8.825 126.000 8.995 ;
        RECT 126.610 8.825 132.010 8.995 ;
        RECT 120.600 8.295 120.930 8.825 ;
        RECT 131.680 8.295 132.010 8.825 ;
        RECT 120.600 7.965 132.010 8.295 ;
        RECT 132.265 8.025 132.680 19.560 ;
        RECT 132.850 19.325 144.260 19.655 ;
        RECT 132.850 18.795 133.180 19.325 ;
        RECT 143.930 18.795 144.260 19.325 ;
        RECT 132.850 18.625 138.250 18.795 ;
        RECT 138.860 18.625 144.260 18.795 ;
        RECT 132.850 18.095 133.180 18.625 ;
        RECT 143.930 18.095 144.260 18.625 ;
        RECT 132.850 17.925 138.250 18.095 ;
        RECT 138.860 17.925 144.260 18.095 ;
        RECT 132.850 17.395 133.180 17.925 ;
        RECT 143.930 17.395 144.260 17.925 ;
        RECT 132.850 17.225 138.250 17.395 ;
        RECT 138.860 17.225 144.260 17.395 ;
        RECT 132.850 16.695 133.180 17.225 ;
        RECT 143.930 16.695 144.260 17.225 ;
        RECT 132.850 16.525 138.250 16.695 ;
        RECT 138.860 16.525 144.260 16.695 ;
        RECT 132.850 15.995 133.180 16.525 ;
        RECT 143.930 15.995 144.260 16.525 ;
        RECT 132.850 15.825 138.250 15.995 ;
        RECT 138.860 15.825 144.260 15.995 ;
        RECT 132.850 15.295 133.180 15.825 ;
        RECT 143.930 15.295 144.260 15.825 ;
        RECT 132.850 15.125 138.250 15.295 ;
        RECT 138.860 15.125 144.260 15.295 ;
        RECT 132.850 14.595 133.180 15.125 ;
        RECT 143.930 14.595 144.260 15.125 ;
        RECT 132.850 14.425 138.250 14.595 ;
        RECT 138.860 14.425 144.260 14.595 ;
        RECT 132.850 13.895 133.180 14.425 ;
        RECT 143.930 13.895 144.260 14.425 ;
        RECT 132.850 13.725 138.250 13.895 ;
        RECT 138.860 13.725 144.260 13.895 ;
        RECT 132.850 13.195 133.180 13.725 ;
        RECT 143.930 13.195 144.260 13.725 ;
        RECT 132.850 13.025 138.250 13.195 ;
        RECT 138.860 13.025 144.260 13.195 ;
        RECT 132.850 12.495 133.180 13.025 ;
        RECT 143.930 12.495 144.260 13.025 ;
        RECT 132.850 12.325 138.250 12.495 ;
        RECT 138.860 12.325 144.260 12.495 ;
        RECT 132.850 11.795 133.180 12.325 ;
        RECT 143.930 11.795 144.260 12.325 ;
        RECT 132.850 11.625 138.250 11.795 ;
        RECT 138.860 11.625 144.260 11.795 ;
        RECT 132.850 11.095 133.180 11.625 ;
        RECT 143.930 11.095 144.260 11.625 ;
        RECT 132.850 10.925 138.250 11.095 ;
        RECT 138.860 10.925 144.260 11.095 ;
        RECT 132.850 10.395 133.180 10.925 ;
        RECT 143.930 10.395 144.260 10.925 ;
        RECT 132.850 10.225 138.250 10.395 ;
        RECT 138.860 10.225 144.260 10.395 ;
        RECT 132.850 9.695 133.180 10.225 ;
        RECT 143.930 9.695 144.260 10.225 ;
        RECT 132.850 9.525 138.250 9.695 ;
        RECT 138.860 9.525 144.260 9.695 ;
        RECT 132.850 8.995 133.180 9.525 ;
        RECT 143.930 8.995 144.260 9.525 ;
        RECT 132.850 8.825 138.250 8.995 ;
        RECT 138.860 8.825 144.260 8.995 ;
        RECT 132.850 8.295 133.180 8.825 ;
        RECT 143.930 8.295 144.260 8.825 ;
        RECT 132.850 7.965 144.260 8.295 ;
        RECT 144.505 8.035 144.920 17.835 ;
      LAYER met1 ;
        RECT 96.110 19.325 145.160 19.655 ;
        RECT 73.380 18.485 84.515 18.925 ;
        RECT 73.380 17.765 84.900 18.485 ;
        RECT 73.380 16.970 79.540 17.765 ;
        RECT 80.355 17.620 84.900 17.765 ;
        RECT 73.380 15.450 79.775 16.970 ;
        RECT 80.355 16.090 84.895 17.620 ;
        RECT 81.945 15.950 84.310 16.090 ;
        RECT 96.110 15.450 96.440 19.325 ;
        RECT 73.380 14.960 96.440 15.450 ;
        RECT 73.385 14.635 75.560 14.960 ;
        RECT 79.525 14.670 80.055 14.960 ;
        RECT 79.525 14.635 80.180 14.670 ;
        RECT 84.300 14.635 96.440 14.960 ;
        RECT 73.385 14.305 96.440 14.635 ;
        RECT 73.385 10.375 75.625 14.305 ;
        RECT 76.140 12.640 76.280 14.305 ;
        RECT 76.700 12.640 76.840 14.305 ;
        RECT 78.130 12.640 78.270 14.305 ;
        RECT 78.690 12.640 78.830 14.305 ;
        RECT 76.140 10.375 76.280 12.040 ;
        RECT 76.700 10.375 76.840 12.040 ;
        RECT 78.130 10.375 78.270 12.040 ;
        RECT 78.690 10.375 78.830 12.040 ;
        RECT 79.345 10.375 80.495 14.305 ;
        RECT 81.010 12.640 81.150 14.305 ;
        RECT 81.570 12.640 81.710 14.305 ;
        RECT 83.000 12.640 83.140 14.305 ;
        RECT 83.560 12.640 83.700 14.305 ;
        RECT 81.010 10.375 81.150 12.040 ;
        RECT 81.570 10.375 81.710 12.040 ;
        RECT 83.000 10.375 83.140 12.040 ;
        RECT 83.560 10.375 83.700 12.040 ;
        RECT 84.215 10.375 86.420 14.305 ;
        RECT 86.935 12.640 87.075 14.305 ;
        RECT 87.495 12.640 87.635 14.305 ;
        RECT 88.925 12.640 89.065 14.305 ;
        RECT 89.485 12.640 89.625 14.305 ;
        RECT 86.935 10.375 87.075 12.040 ;
        RECT 87.495 10.375 87.635 12.040 ;
        RECT 88.925 10.375 89.065 12.040 ;
        RECT 89.485 10.375 89.625 12.040 ;
        RECT 90.140 10.375 91.145 14.305 ;
        RECT 91.660 12.640 91.800 14.305 ;
        RECT 92.220 12.640 92.360 14.305 ;
        RECT 93.650 12.640 93.790 14.305 ;
        RECT 94.210 12.640 94.350 14.305 ;
        RECT 91.660 10.375 91.800 12.040 ;
        RECT 92.220 10.375 92.360 12.040 ;
        RECT 93.650 10.375 93.790 12.040 ;
        RECT 94.210 10.375 94.350 12.040 ;
        RECT 94.865 10.375 96.440 14.305 ;
        RECT 96.890 14.110 97.030 19.325 ;
        RECT 97.450 14.110 97.590 19.325 ;
        RECT 98.010 14.110 98.150 19.325 ;
        RECT 98.570 14.110 98.710 19.325 ;
        RECT 99.130 14.110 99.270 19.325 ;
        RECT 99.690 14.110 99.830 19.325 ;
        RECT 100.250 14.110 100.390 19.325 ;
        RECT 100.810 14.110 100.950 19.325 ;
        RECT 101.370 14.110 101.510 19.325 ;
        RECT 102.120 14.110 102.260 19.325 ;
        RECT 102.680 14.110 102.820 19.325 ;
        RECT 103.240 14.110 103.380 19.325 ;
        RECT 103.800 14.110 103.940 19.325 ;
        RECT 104.360 14.110 104.500 19.325 ;
        RECT 104.920 14.110 105.060 19.325 ;
        RECT 105.480 14.110 105.620 19.325 ;
        RECT 106.040 14.110 106.180 19.325 ;
        RECT 106.600 14.110 106.740 19.325 ;
        RECT 73.385 10.045 96.440 10.375 ;
        RECT 73.385 9.765 75.480 10.045 ;
        RECT 79.675 9.765 80.180 10.045 ;
        RECT 84.300 9.765 86.355 10.045 ;
        RECT 90.440 9.765 90.815 10.045 ;
        RECT 92.545 9.835 96.440 10.045 ;
        RECT 92.425 9.765 96.440 9.835 ;
        RECT 73.385 9.750 96.440 9.765 ;
        RECT 73.385 8.975 93.280 9.750 ;
        RECT 94.410 8.975 96.440 9.750 ;
        RECT 73.385 8.295 96.440 8.975 ;
        RECT 96.890 8.295 97.030 13.510 ;
        RECT 97.450 8.295 97.590 13.510 ;
        RECT 98.010 8.295 98.150 13.510 ;
        RECT 98.570 8.295 98.710 13.510 ;
        RECT 99.130 8.295 99.270 13.510 ;
        RECT 99.690 8.295 99.830 13.510 ;
        RECT 100.250 8.295 100.390 13.510 ;
        RECT 100.810 8.295 100.950 13.510 ;
        RECT 101.370 8.295 101.510 13.510 ;
        RECT 102.120 8.295 102.260 13.510 ;
        RECT 102.680 8.295 102.820 13.510 ;
        RECT 103.240 8.295 103.380 13.510 ;
        RECT 103.800 8.295 103.940 13.510 ;
        RECT 104.360 8.295 104.500 13.510 ;
        RECT 104.920 8.295 105.060 13.510 ;
        RECT 105.480 8.295 105.620 13.510 ;
        RECT 106.040 8.295 106.180 13.510 ;
        RECT 106.600 8.295 106.740 13.510 ;
        RECT 107.190 8.295 108.665 19.325 ;
        RECT 109.115 14.110 109.255 19.325 ;
        RECT 109.675 14.110 109.815 19.325 ;
        RECT 110.235 14.110 110.375 19.325 ;
        RECT 110.795 14.110 110.935 19.325 ;
        RECT 111.355 14.110 111.495 19.325 ;
        RECT 111.915 14.110 112.055 19.325 ;
        RECT 112.475 14.110 112.615 19.325 ;
        RECT 113.035 14.110 113.175 19.325 ;
        RECT 113.595 14.110 113.735 19.325 ;
        RECT 114.345 14.110 114.485 19.325 ;
        RECT 114.905 14.110 115.045 19.325 ;
        RECT 115.465 14.110 115.605 19.325 ;
        RECT 116.025 14.110 116.165 19.325 ;
        RECT 116.585 14.110 116.725 19.325 ;
        RECT 117.145 14.110 117.285 19.325 ;
        RECT 117.705 14.110 117.845 19.325 ;
        RECT 118.265 14.110 118.405 19.325 ;
        RECT 118.825 14.110 118.965 19.325 ;
        RECT 109.115 8.295 109.255 13.510 ;
        RECT 109.675 8.295 109.815 13.510 ;
        RECT 110.235 8.295 110.375 13.510 ;
        RECT 110.795 8.295 110.935 13.510 ;
        RECT 111.355 8.295 111.495 13.510 ;
        RECT 111.915 8.295 112.055 13.510 ;
        RECT 112.475 8.295 112.615 13.510 ;
        RECT 113.035 8.295 113.175 13.510 ;
        RECT 113.595 8.295 113.735 13.510 ;
        RECT 114.345 8.295 114.485 13.510 ;
        RECT 114.905 8.295 115.045 13.510 ;
        RECT 115.465 8.295 115.605 13.510 ;
        RECT 116.025 8.295 116.165 13.510 ;
        RECT 116.585 8.295 116.725 13.510 ;
        RECT 117.145 8.295 117.285 13.510 ;
        RECT 117.705 8.295 117.845 13.510 ;
        RECT 118.265 8.295 118.405 13.510 ;
        RECT 118.825 8.295 118.965 13.510 ;
        RECT 119.415 8.295 120.930 19.325 ;
        RECT 121.380 14.110 121.520 19.325 ;
        RECT 121.940 14.110 122.080 19.325 ;
        RECT 122.500 14.110 122.640 19.325 ;
        RECT 123.060 14.110 123.200 19.325 ;
        RECT 123.620 14.110 123.760 19.325 ;
        RECT 124.180 14.110 124.320 19.325 ;
        RECT 124.740 14.110 124.880 19.325 ;
        RECT 125.300 14.110 125.440 19.325 ;
        RECT 125.860 14.110 126.000 19.325 ;
        RECT 126.610 14.110 126.750 19.325 ;
        RECT 127.170 14.110 127.310 19.325 ;
        RECT 127.730 14.110 127.870 19.325 ;
        RECT 128.290 14.110 128.430 19.325 ;
        RECT 128.850 14.110 128.990 19.325 ;
        RECT 129.410 14.110 129.550 19.325 ;
        RECT 129.970 14.110 130.110 19.325 ;
        RECT 130.530 14.110 130.670 19.325 ;
        RECT 131.090 14.110 131.230 19.325 ;
        RECT 121.380 8.295 121.520 13.510 ;
        RECT 121.940 8.295 122.080 13.510 ;
        RECT 122.500 8.295 122.640 13.510 ;
        RECT 123.060 8.295 123.200 13.510 ;
        RECT 123.620 8.295 123.760 13.510 ;
        RECT 124.180 8.295 124.320 13.510 ;
        RECT 124.740 8.295 124.880 13.510 ;
        RECT 125.300 8.295 125.440 13.510 ;
        RECT 125.860 8.295 126.000 13.510 ;
        RECT 126.610 8.295 126.750 13.510 ;
        RECT 127.170 8.295 127.310 13.510 ;
        RECT 127.730 8.295 127.870 13.510 ;
        RECT 128.290 8.295 128.430 13.510 ;
        RECT 128.850 8.295 128.990 13.510 ;
        RECT 129.410 8.295 129.550 13.510 ;
        RECT 129.970 8.295 130.110 13.510 ;
        RECT 130.530 8.295 130.670 13.510 ;
        RECT 131.090 8.295 131.230 13.510 ;
        RECT 131.680 8.295 133.180 19.325 ;
        RECT 133.630 14.110 133.770 19.325 ;
        RECT 134.190 14.110 134.330 19.325 ;
        RECT 134.750 14.110 134.890 19.325 ;
        RECT 135.310 14.110 135.450 19.325 ;
        RECT 135.870 14.110 136.010 19.325 ;
        RECT 136.430 14.110 136.570 19.325 ;
        RECT 136.990 14.110 137.130 19.325 ;
        RECT 137.550 14.110 137.690 19.325 ;
        RECT 138.110 14.110 138.250 19.325 ;
        RECT 138.860 14.110 139.000 19.325 ;
        RECT 139.420 14.110 139.560 19.325 ;
        RECT 139.980 14.110 140.120 19.325 ;
        RECT 140.540 14.110 140.680 19.325 ;
        RECT 141.100 14.110 141.240 19.325 ;
        RECT 141.660 14.110 141.800 19.325 ;
        RECT 142.220 14.110 142.360 19.325 ;
        RECT 142.780 14.110 142.920 19.325 ;
        RECT 143.340 14.110 143.480 19.325 ;
        RECT 133.630 8.295 133.770 13.510 ;
        RECT 134.190 8.295 134.330 13.510 ;
        RECT 134.750 8.295 134.890 13.510 ;
        RECT 135.310 8.295 135.450 13.510 ;
        RECT 135.870 8.295 136.010 13.510 ;
        RECT 136.430 8.295 136.570 13.510 ;
        RECT 136.990 8.295 137.130 13.510 ;
        RECT 137.550 8.295 137.690 13.510 ;
        RECT 138.110 8.295 138.250 13.510 ;
        RECT 138.860 8.295 139.000 13.510 ;
        RECT 139.420 8.295 139.560 13.510 ;
        RECT 139.980 8.295 140.120 13.510 ;
        RECT 140.540 8.295 140.680 13.510 ;
        RECT 141.100 8.295 141.240 13.510 ;
        RECT 141.660 8.295 141.800 13.510 ;
        RECT 142.220 8.295 142.360 13.510 ;
        RECT 142.780 8.295 142.920 13.510 ;
        RECT 143.340 8.295 143.480 13.510 ;
        RECT 143.930 8.295 145.160 19.325 ;
        RECT 73.385 7.965 145.160 8.295 ;
        RECT 73.385 7.075 144.780 7.965 ;
        RECT 142.070 6.815 144.780 7.075 ;
      LAYER met2 ;
        RECT 96.110 19.325 101.540 19.655 ;
        RECT 102.090 19.325 107.520 19.655 ;
        RECT 96.110 18.905 96.440 19.325 ;
        RECT 107.190 18.905 107.520 19.325 ;
        RECT 96.110 18.765 101.540 18.905 ;
        RECT 102.090 18.765 107.520 18.905 ;
        RECT 96.110 18.345 96.440 18.765 ;
        RECT 107.190 18.345 107.520 18.765 ;
        RECT 96.110 18.205 101.540 18.345 ;
        RECT 102.090 18.205 107.520 18.345 ;
        RECT 96.110 17.785 96.440 18.205 ;
        RECT 107.190 17.785 107.520 18.205 ;
        RECT 96.110 17.645 101.540 17.785 ;
        RECT 102.090 17.645 107.520 17.785 ;
        RECT 96.110 17.225 96.440 17.645 ;
        RECT 107.190 17.225 107.520 17.645 ;
        RECT 96.110 17.085 101.540 17.225 ;
        RECT 102.090 17.085 107.520 17.225 ;
        RECT 96.110 16.665 96.440 17.085 ;
        RECT 107.190 16.665 107.520 17.085 ;
        RECT 96.110 16.525 101.540 16.665 ;
        RECT 102.090 16.525 107.520 16.665 ;
        RECT 96.110 16.105 96.440 16.525 ;
        RECT 107.190 16.105 107.520 16.525 ;
        RECT 96.110 15.965 101.540 16.105 ;
        RECT 102.090 15.965 107.520 16.105 ;
        RECT 96.110 15.545 96.440 15.965 ;
        RECT 107.190 15.545 107.520 15.965 ;
        RECT 73.380 14.960 92.720 15.445 ;
        RECT 93.320 14.940 95.330 15.455 ;
        RECT 96.110 15.405 101.540 15.545 ;
        RECT 102.090 15.405 107.520 15.545 ;
        RECT 96.110 14.985 96.440 15.405 ;
        RECT 107.190 14.985 107.520 15.405 ;
        RECT 96.110 14.845 101.540 14.985 ;
        RECT 102.090 14.845 107.520 14.985 ;
        RECT 75.295 14.305 77.210 14.635 ;
        RECT 77.760 14.305 79.675 14.635 ;
        RECT 75.295 13.885 75.625 14.305 ;
        RECT 79.345 13.885 79.675 14.305 ;
        RECT 75.295 13.745 77.205 13.885 ;
        RECT 77.765 13.745 79.675 13.885 ;
        RECT 75.295 13.325 75.625 13.745 ;
        RECT 79.345 13.325 79.675 13.745 ;
        RECT 75.295 13.185 77.205 13.325 ;
        RECT 77.765 13.185 79.675 13.325 ;
        RECT 75.295 12.765 75.625 13.185 ;
        RECT 79.345 12.765 79.675 13.185 ;
        RECT 75.295 12.625 77.205 12.765 ;
        RECT 77.765 12.625 79.675 12.765 ;
        RECT 75.295 12.615 75.625 12.625 ;
        RECT 79.345 12.615 79.675 12.625 ;
        RECT 80.165 14.305 82.080 14.635 ;
        RECT 82.630 14.305 84.545 14.635 ;
        RECT 80.165 13.885 80.495 14.305 ;
        RECT 84.215 13.885 84.545 14.305 ;
        RECT 80.165 13.745 82.075 13.885 ;
        RECT 82.635 13.745 84.545 13.885 ;
        RECT 80.165 13.325 80.495 13.745 ;
        RECT 84.215 13.325 84.545 13.745 ;
        RECT 80.165 13.185 82.075 13.325 ;
        RECT 82.635 13.185 84.545 13.325 ;
        RECT 80.165 12.765 80.495 13.185 ;
        RECT 84.215 12.765 84.545 13.185 ;
        RECT 80.165 12.625 82.075 12.765 ;
        RECT 82.635 12.625 84.545 12.765 ;
        RECT 80.165 12.615 80.495 12.625 ;
        RECT 84.215 12.615 84.545 12.625 ;
        RECT 86.090 14.305 88.005 14.635 ;
        RECT 88.555 14.305 90.470 14.635 ;
        RECT 86.090 13.885 86.420 14.305 ;
        RECT 90.140 13.885 90.470 14.305 ;
        RECT 86.090 13.745 88.000 13.885 ;
        RECT 88.560 13.745 90.470 13.885 ;
        RECT 86.090 13.325 86.420 13.745 ;
        RECT 90.140 13.325 90.470 13.745 ;
        RECT 86.090 13.185 88.000 13.325 ;
        RECT 88.560 13.185 90.470 13.325 ;
        RECT 86.090 12.765 86.420 13.185 ;
        RECT 90.140 12.765 90.470 13.185 ;
        RECT 86.090 12.625 88.000 12.765 ;
        RECT 88.560 12.625 90.470 12.765 ;
        RECT 86.090 12.615 86.420 12.625 ;
        RECT 90.140 12.615 90.470 12.625 ;
        RECT 90.815 14.305 92.730 14.635 ;
        RECT 93.280 14.305 95.195 14.635 ;
        RECT 90.815 13.885 91.145 14.305 ;
        RECT 94.865 13.885 95.195 14.305 ;
        RECT 96.110 14.425 96.440 14.845 ;
        RECT 107.190 14.425 107.520 14.845 ;
        RECT 96.110 14.285 101.540 14.425 ;
        RECT 102.090 14.285 107.520 14.425 ;
        RECT 96.110 14.085 96.440 14.285 ;
        RECT 107.190 14.085 107.520 14.285 ;
        RECT 108.335 19.325 113.765 19.655 ;
        RECT 114.315 19.325 119.745 19.655 ;
        RECT 108.335 18.905 108.665 19.325 ;
        RECT 119.415 18.905 119.745 19.325 ;
        RECT 108.335 18.765 113.765 18.905 ;
        RECT 114.315 18.765 119.745 18.905 ;
        RECT 108.335 18.345 108.665 18.765 ;
        RECT 119.415 18.345 119.745 18.765 ;
        RECT 108.335 18.205 113.765 18.345 ;
        RECT 114.315 18.205 119.745 18.345 ;
        RECT 108.335 17.785 108.665 18.205 ;
        RECT 119.415 17.785 119.745 18.205 ;
        RECT 108.335 17.645 113.765 17.785 ;
        RECT 114.315 17.645 119.745 17.785 ;
        RECT 108.335 17.225 108.665 17.645 ;
        RECT 119.415 17.225 119.745 17.645 ;
        RECT 108.335 17.085 113.765 17.225 ;
        RECT 114.315 17.085 119.745 17.225 ;
        RECT 108.335 16.665 108.665 17.085 ;
        RECT 119.415 16.665 119.745 17.085 ;
        RECT 108.335 16.525 113.765 16.665 ;
        RECT 114.315 16.525 119.745 16.665 ;
        RECT 108.335 16.105 108.665 16.525 ;
        RECT 119.415 16.105 119.745 16.525 ;
        RECT 108.335 15.965 113.765 16.105 ;
        RECT 114.315 15.965 119.745 16.105 ;
        RECT 108.335 15.545 108.665 15.965 ;
        RECT 119.415 15.545 119.745 15.965 ;
        RECT 108.335 15.405 113.765 15.545 ;
        RECT 114.315 15.405 119.745 15.545 ;
        RECT 108.335 14.985 108.665 15.405 ;
        RECT 119.415 14.985 119.745 15.405 ;
        RECT 108.335 14.845 113.765 14.985 ;
        RECT 114.315 14.845 119.745 14.985 ;
        RECT 108.335 14.425 108.665 14.845 ;
        RECT 119.415 14.425 119.745 14.845 ;
        RECT 108.335 14.285 113.765 14.425 ;
        RECT 114.315 14.285 119.745 14.425 ;
        RECT 108.335 14.085 108.665 14.285 ;
        RECT 119.415 14.085 119.745 14.285 ;
        RECT 120.600 19.325 126.030 19.655 ;
        RECT 126.580 19.325 132.010 19.655 ;
        RECT 120.600 18.905 120.930 19.325 ;
        RECT 131.680 18.905 132.010 19.325 ;
        RECT 120.600 18.765 126.030 18.905 ;
        RECT 126.580 18.765 132.010 18.905 ;
        RECT 120.600 18.345 120.930 18.765 ;
        RECT 131.680 18.345 132.010 18.765 ;
        RECT 120.600 18.205 126.030 18.345 ;
        RECT 126.580 18.205 132.010 18.345 ;
        RECT 120.600 17.785 120.930 18.205 ;
        RECT 131.680 17.785 132.010 18.205 ;
        RECT 120.600 17.645 126.030 17.785 ;
        RECT 126.580 17.645 132.010 17.785 ;
        RECT 120.600 17.225 120.930 17.645 ;
        RECT 131.680 17.225 132.010 17.645 ;
        RECT 120.600 17.085 126.030 17.225 ;
        RECT 126.580 17.085 132.010 17.225 ;
        RECT 120.600 16.665 120.930 17.085 ;
        RECT 131.680 16.665 132.010 17.085 ;
        RECT 120.600 16.525 126.030 16.665 ;
        RECT 126.580 16.525 132.010 16.665 ;
        RECT 120.600 16.105 120.930 16.525 ;
        RECT 131.680 16.105 132.010 16.525 ;
        RECT 120.600 15.965 126.030 16.105 ;
        RECT 126.580 15.965 132.010 16.105 ;
        RECT 120.600 15.545 120.930 15.965 ;
        RECT 131.680 15.545 132.010 15.965 ;
        RECT 120.600 15.405 126.030 15.545 ;
        RECT 126.580 15.405 132.010 15.545 ;
        RECT 120.600 14.985 120.930 15.405 ;
        RECT 131.680 14.985 132.010 15.405 ;
        RECT 120.600 14.845 126.030 14.985 ;
        RECT 126.580 14.845 132.010 14.985 ;
        RECT 120.600 14.425 120.930 14.845 ;
        RECT 131.680 14.425 132.010 14.845 ;
        RECT 120.600 14.285 126.030 14.425 ;
        RECT 126.580 14.285 132.010 14.425 ;
        RECT 120.600 14.085 120.930 14.285 ;
        RECT 131.680 14.085 132.010 14.285 ;
        RECT 132.850 19.325 138.280 19.655 ;
        RECT 138.830 19.325 144.260 19.655 ;
        RECT 132.850 18.905 133.180 19.325 ;
        RECT 143.930 18.905 144.260 19.325 ;
        RECT 132.850 18.765 138.280 18.905 ;
        RECT 138.830 18.765 144.260 18.905 ;
        RECT 132.850 18.345 133.180 18.765 ;
        RECT 143.930 18.345 144.260 18.765 ;
        RECT 132.850 18.205 138.280 18.345 ;
        RECT 138.830 18.205 144.260 18.345 ;
        RECT 132.850 17.785 133.180 18.205 ;
        RECT 143.930 17.785 144.260 18.205 ;
        RECT 132.850 17.645 138.280 17.785 ;
        RECT 138.830 17.645 144.260 17.785 ;
        RECT 132.850 17.225 133.180 17.645 ;
        RECT 143.930 17.225 144.260 17.645 ;
        RECT 132.850 17.085 138.280 17.225 ;
        RECT 138.830 17.085 144.260 17.225 ;
        RECT 132.850 16.665 133.180 17.085 ;
        RECT 143.930 16.665 144.260 17.085 ;
        RECT 132.850 16.525 138.280 16.665 ;
        RECT 138.830 16.525 144.260 16.665 ;
        RECT 132.850 16.105 133.180 16.525 ;
        RECT 143.930 16.105 144.260 16.525 ;
        RECT 132.850 15.965 138.280 16.105 ;
        RECT 138.830 15.965 144.260 16.105 ;
        RECT 132.850 15.545 133.180 15.965 ;
        RECT 143.930 15.545 144.260 15.965 ;
        RECT 132.850 15.405 138.280 15.545 ;
        RECT 138.830 15.405 144.260 15.545 ;
        RECT 132.850 14.985 133.180 15.405 ;
        RECT 143.930 14.985 144.260 15.405 ;
        RECT 132.850 14.845 138.280 14.985 ;
        RECT 138.830 14.845 144.260 14.985 ;
        RECT 132.850 14.425 133.180 14.845 ;
        RECT 143.930 14.425 144.260 14.845 ;
        RECT 132.850 14.285 138.280 14.425 ;
        RECT 138.830 14.285 144.260 14.425 ;
        RECT 132.850 14.085 133.180 14.285 ;
        RECT 143.930 14.085 144.260 14.285 ;
        RECT 90.815 13.745 92.725 13.885 ;
        RECT 93.285 13.745 95.195 13.885 ;
        RECT 90.815 13.325 91.145 13.745 ;
        RECT 94.865 13.325 95.195 13.745 ;
        RECT 90.815 13.185 92.725 13.325 ;
        RECT 93.285 13.185 95.195 13.325 ;
        RECT 90.815 12.765 91.145 13.185 ;
        RECT 94.865 12.765 95.195 13.185 ;
        RECT 90.815 12.625 92.725 12.765 ;
        RECT 93.285 12.625 95.195 12.765 ;
        RECT 90.815 12.615 91.145 12.625 ;
        RECT 94.865 12.615 95.195 12.625 ;
        RECT 96.110 13.335 96.440 13.535 ;
        RECT 107.190 13.335 107.520 13.535 ;
        RECT 96.110 13.195 101.540 13.335 ;
        RECT 102.090 13.195 107.520 13.335 ;
        RECT 96.110 12.775 96.440 13.195 ;
        RECT 107.190 12.775 107.520 13.195 ;
        RECT 96.110 12.635 101.540 12.775 ;
        RECT 102.090 12.635 107.520 12.775 ;
        RECT 96.110 12.215 96.440 12.635 ;
        RECT 107.190 12.215 107.520 12.635 ;
        RECT 96.110 12.075 101.540 12.215 ;
        RECT 102.090 12.075 107.520 12.215 ;
        RECT 75.295 12.055 75.625 12.065 ;
        RECT 79.345 12.055 79.675 12.065 ;
        RECT 75.295 11.915 77.205 12.055 ;
        RECT 77.765 11.915 79.675 12.055 ;
        RECT 75.295 11.495 75.625 11.915 ;
        RECT 79.345 11.495 79.675 11.915 ;
        RECT 75.295 11.355 77.205 11.495 ;
        RECT 77.765 11.355 79.675 11.495 ;
        RECT 75.295 10.935 75.625 11.355 ;
        RECT 79.345 10.935 79.675 11.355 ;
        RECT 75.295 10.795 77.205 10.935 ;
        RECT 77.765 10.795 79.675 10.935 ;
        RECT 75.295 10.375 75.625 10.795 ;
        RECT 79.345 10.375 79.675 10.795 ;
        RECT 75.295 10.045 77.210 10.375 ;
        RECT 77.760 10.045 79.675 10.375 ;
        RECT 80.165 12.055 80.495 12.065 ;
        RECT 84.215 12.055 84.545 12.065 ;
        RECT 80.165 11.915 82.075 12.055 ;
        RECT 82.635 11.915 84.545 12.055 ;
        RECT 80.165 11.495 80.495 11.915 ;
        RECT 84.215 11.495 84.545 11.915 ;
        RECT 80.165 11.355 82.075 11.495 ;
        RECT 82.635 11.355 84.545 11.495 ;
        RECT 80.165 10.935 80.495 11.355 ;
        RECT 84.215 10.935 84.545 11.355 ;
        RECT 80.165 10.795 82.075 10.935 ;
        RECT 82.635 10.795 84.545 10.935 ;
        RECT 80.165 10.375 80.495 10.795 ;
        RECT 84.215 10.375 84.545 10.795 ;
        RECT 80.165 10.045 82.080 10.375 ;
        RECT 82.630 10.045 84.545 10.375 ;
        RECT 86.090 12.055 86.420 12.065 ;
        RECT 90.140 12.055 90.470 12.065 ;
        RECT 86.090 11.915 88.000 12.055 ;
        RECT 88.560 11.915 90.470 12.055 ;
        RECT 86.090 11.495 86.420 11.915 ;
        RECT 90.140 11.495 90.470 11.915 ;
        RECT 86.090 11.355 88.000 11.495 ;
        RECT 88.560 11.355 90.470 11.495 ;
        RECT 86.090 10.935 86.420 11.355 ;
        RECT 90.140 10.935 90.470 11.355 ;
        RECT 86.090 10.795 88.000 10.935 ;
        RECT 88.560 10.795 90.470 10.935 ;
        RECT 86.090 10.375 86.420 10.795 ;
        RECT 90.140 10.375 90.470 10.795 ;
        RECT 86.090 10.045 88.005 10.375 ;
        RECT 88.555 10.045 90.470 10.375 ;
        RECT 90.815 12.055 91.145 12.065 ;
        RECT 94.865 12.055 95.195 12.065 ;
        RECT 90.815 11.915 92.725 12.055 ;
        RECT 93.285 11.915 95.195 12.055 ;
        RECT 90.815 11.495 91.145 11.915 ;
        RECT 94.865 11.495 95.195 11.915 ;
        RECT 90.815 11.355 92.725 11.495 ;
        RECT 93.285 11.355 95.195 11.495 ;
        RECT 90.815 10.935 91.145 11.355 ;
        RECT 94.865 10.935 95.195 11.355 ;
        RECT 90.815 10.795 92.725 10.935 ;
        RECT 93.285 10.795 95.195 10.935 ;
        RECT 90.815 10.375 91.145 10.795 ;
        RECT 94.865 10.375 95.195 10.795 ;
        RECT 90.815 10.045 92.730 10.375 ;
        RECT 93.280 10.045 95.195 10.375 ;
        RECT 96.110 11.655 96.440 12.075 ;
        RECT 107.190 11.655 107.520 12.075 ;
        RECT 96.110 11.515 101.540 11.655 ;
        RECT 102.090 11.515 107.520 11.655 ;
        RECT 96.110 11.095 96.440 11.515 ;
        RECT 107.190 11.095 107.520 11.515 ;
        RECT 96.110 10.955 101.540 11.095 ;
        RECT 102.090 10.955 107.520 11.095 ;
        RECT 96.110 10.535 96.440 10.955 ;
        RECT 107.190 10.535 107.520 10.955 ;
        RECT 96.110 10.395 101.540 10.535 ;
        RECT 102.090 10.395 107.520 10.535 ;
        RECT 96.110 9.975 96.440 10.395 ;
        RECT 107.190 9.975 107.520 10.395 ;
        RECT 96.110 9.835 101.540 9.975 ;
        RECT 102.090 9.835 107.520 9.975 ;
        RECT 96.110 9.415 96.440 9.835 ;
        RECT 107.190 9.415 107.520 9.835 ;
        RECT 96.110 9.275 101.540 9.415 ;
        RECT 102.090 9.275 107.520 9.415 ;
        RECT 96.110 8.855 96.440 9.275 ;
        RECT 107.190 8.855 107.520 9.275 ;
        RECT 96.110 8.715 101.540 8.855 ;
        RECT 102.090 8.715 107.520 8.855 ;
        RECT 96.110 8.295 96.440 8.715 ;
        RECT 107.190 8.295 107.520 8.715 ;
        RECT 96.110 7.965 101.540 8.295 ;
        RECT 102.090 7.965 107.520 8.295 ;
        RECT 108.335 13.335 108.665 13.535 ;
        RECT 119.415 13.335 119.745 13.535 ;
        RECT 108.335 13.195 113.765 13.335 ;
        RECT 114.315 13.195 119.745 13.335 ;
        RECT 108.335 12.775 108.665 13.195 ;
        RECT 119.415 12.775 119.745 13.195 ;
        RECT 108.335 12.635 113.765 12.775 ;
        RECT 114.315 12.635 119.745 12.775 ;
        RECT 108.335 12.215 108.665 12.635 ;
        RECT 119.415 12.215 119.745 12.635 ;
        RECT 108.335 12.075 113.765 12.215 ;
        RECT 114.315 12.075 119.745 12.215 ;
        RECT 108.335 11.655 108.665 12.075 ;
        RECT 119.415 11.655 119.745 12.075 ;
        RECT 108.335 11.515 113.765 11.655 ;
        RECT 114.315 11.515 119.745 11.655 ;
        RECT 108.335 11.095 108.665 11.515 ;
        RECT 119.415 11.095 119.745 11.515 ;
        RECT 108.335 10.955 113.765 11.095 ;
        RECT 114.315 10.955 119.745 11.095 ;
        RECT 108.335 10.535 108.665 10.955 ;
        RECT 119.415 10.535 119.745 10.955 ;
        RECT 108.335 10.395 113.765 10.535 ;
        RECT 114.315 10.395 119.745 10.535 ;
        RECT 108.335 9.975 108.665 10.395 ;
        RECT 119.415 9.975 119.745 10.395 ;
        RECT 108.335 9.835 113.765 9.975 ;
        RECT 114.315 9.835 119.745 9.975 ;
        RECT 108.335 9.415 108.665 9.835 ;
        RECT 119.415 9.415 119.745 9.835 ;
        RECT 108.335 9.275 113.765 9.415 ;
        RECT 114.315 9.275 119.745 9.415 ;
        RECT 108.335 8.855 108.665 9.275 ;
        RECT 119.415 8.855 119.745 9.275 ;
        RECT 108.335 8.715 113.765 8.855 ;
        RECT 114.315 8.715 119.745 8.855 ;
        RECT 108.335 8.295 108.665 8.715 ;
        RECT 119.415 8.295 119.745 8.715 ;
        RECT 108.335 7.965 113.765 8.295 ;
        RECT 114.315 7.965 119.745 8.295 ;
        RECT 120.600 13.335 120.930 13.535 ;
        RECT 131.680 13.335 132.010 13.535 ;
        RECT 120.600 13.195 126.030 13.335 ;
        RECT 126.580 13.195 132.010 13.335 ;
        RECT 120.600 12.775 120.930 13.195 ;
        RECT 131.680 12.775 132.010 13.195 ;
        RECT 120.600 12.635 126.030 12.775 ;
        RECT 126.580 12.635 132.010 12.775 ;
        RECT 120.600 12.215 120.930 12.635 ;
        RECT 131.680 12.215 132.010 12.635 ;
        RECT 120.600 12.075 126.030 12.215 ;
        RECT 126.580 12.075 132.010 12.215 ;
        RECT 120.600 11.655 120.930 12.075 ;
        RECT 131.680 11.655 132.010 12.075 ;
        RECT 120.600 11.515 126.030 11.655 ;
        RECT 126.580 11.515 132.010 11.655 ;
        RECT 120.600 11.095 120.930 11.515 ;
        RECT 131.680 11.095 132.010 11.515 ;
        RECT 120.600 10.955 126.030 11.095 ;
        RECT 126.580 10.955 132.010 11.095 ;
        RECT 120.600 10.535 120.930 10.955 ;
        RECT 131.680 10.535 132.010 10.955 ;
        RECT 120.600 10.395 126.030 10.535 ;
        RECT 126.580 10.395 132.010 10.535 ;
        RECT 120.600 9.975 120.930 10.395 ;
        RECT 131.680 9.975 132.010 10.395 ;
        RECT 120.600 9.835 126.030 9.975 ;
        RECT 126.580 9.835 132.010 9.975 ;
        RECT 120.600 9.415 120.930 9.835 ;
        RECT 131.680 9.415 132.010 9.835 ;
        RECT 120.600 9.275 126.030 9.415 ;
        RECT 126.580 9.275 132.010 9.415 ;
        RECT 120.600 8.855 120.930 9.275 ;
        RECT 131.680 8.855 132.010 9.275 ;
        RECT 120.600 8.715 126.030 8.855 ;
        RECT 126.580 8.715 132.010 8.855 ;
        RECT 120.600 8.295 120.930 8.715 ;
        RECT 131.680 8.295 132.010 8.715 ;
        RECT 120.600 7.965 126.030 8.295 ;
        RECT 126.580 7.965 132.010 8.295 ;
        RECT 132.850 13.335 133.180 13.535 ;
        RECT 143.930 13.335 144.260 13.535 ;
        RECT 132.850 13.195 138.280 13.335 ;
        RECT 138.830 13.195 144.260 13.335 ;
        RECT 132.850 12.775 133.180 13.195 ;
        RECT 143.930 12.775 144.260 13.195 ;
        RECT 132.850 12.635 138.280 12.775 ;
        RECT 138.830 12.635 144.260 12.775 ;
        RECT 132.850 12.215 133.180 12.635 ;
        RECT 143.930 12.215 144.260 12.635 ;
        RECT 132.850 12.075 138.280 12.215 ;
        RECT 138.830 12.075 144.260 12.215 ;
        RECT 132.850 11.655 133.180 12.075 ;
        RECT 143.930 11.655 144.260 12.075 ;
        RECT 132.850 11.515 138.280 11.655 ;
        RECT 138.830 11.515 144.260 11.655 ;
        RECT 132.850 11.095 133.180 11.515 ;
        RECT 143.930 11.095 144.260 11.515 ;
        RECT 132.850 10.955 138.280 11.095 ;
        RECT 138.830 10.955 144.260 11.095 ;
        RECT 132.850 10.535 133.180 10.955 ;
        RECT 143.930 10.535 144.260 10.955 ;
        RECT 132.850 10.395 138.280 10.535 ;
        RECT 138.830 10.395 144.260 10.535 ;
        RECT 132.850 9.975 133.180 10.395 ;
        RECT 143.930 9.975 144.260 10.395 ;
        RECT 132.850 9.835 138.280 9.975 ;
        RECT 138.830 9.835 144.260 9.975 ;
        RECT 132.850 9.415 133.180 9.835 ;
        RECT 143.930 9.415 144.260 9.835 ;
        RECT 132.850 9.275 138.280 9.415 ;
        RECT 138.830 9.275 144.260 9.415 ;
        RECT 132.850 8.855 133.180 9.275 ;
        RECT 143.930 8.855 144.260 9.275 ;
        RECT 132.850 8.715 138.280 8.855 ;
        RECT 138.830 8.715 144.260 8.855 ;
        RECT 132.850 8.295 133.180 8.715 ;
        RECT 143.930 8.295 144.260 8.715 ;
        RECT 132.850 7.965 138.280 8.295 ;
        RECT 138.830 7.965 144.260 8.295 ;
      LAYER met3 ;
        RECT 73.380 14.935 95.520 15.450 ;
        RECT 75.295 14.305 79.675 14.635 ;
        RECT 75.295 10.375 75.625 14.305 ;
        RECT 76.525 12.805 76.825 14.305 ;
        RECT 78.145 12.805 78.445 14.305 ;
        RECT 76.525 10.375 76.825 11.875 ;
        RECT 78.145 10.375 78.445 11.875 ;
        RECT 79.345 10.375 79.675 14.305 ;
        RECT 75.295 10.045 79.675 10.375 ;
        RECT 80.165 14.305 84.545 14.635 ;
        RECT 80.165 10.375 80.495 14.305 ;
        RECT 81.395 12.805 81.695 14.305 ;
        RECT 83.015 12.805 83.315 14.305 ;
        RECT 81.395 10.375 81.695 11.875 ;
        RECT 83.015 10.375 83.315 11.875 ;
        RECT 84.215 10.375 84.545 14.305 ;
        RECT 80.165 10.045 84.545 10.375 ;
        RECT 86.090 14.305 90.470 14.635 ;
        RECT 86.090 10.375 86.420 14.305 ;
        RECT 87.320 12.805 87.620 14.305 ;
        RECT 88.940 12.805 89.240 14.305 ;
        RECT 87.320 10.375 87.620 11.875 ;
        RECT 88.940 10.375 89.240 11.875 ;
        RECT 90.140 10.375 90.470 14.305 ;
        RECT 86.090 10.045 90.470 10.375 ;
        RECT 90.815 14.305 95.195 14.635 ;
        RECT 90.815 10.375 91.145 14.305 ;
        RECT 92.045 12.805 92.345 14.305 ;
        RECT 93.665 12.805 93.965 14.305 ;
        RECT 92.045 10.375 92.345 11.875 ;
        RECT 93.665 10.375 93.965 11.875 ;
        RECT 94.865 10.375 95.195 14.305 ;
        RECT 90.815 10.045 95.195 10.375 ;
        RECT 96.110 7.965 144.260 19.655 ;
    END
    PORT
      LAYER nwell ;
        RECT 73.300 17.315 93.425 19.695 ;
        RECT 73.495 6.685 138.490 6.755 ;
        RECT 73.495 4.825 138.915 6.685 ;
      LAYER li1 ;
        RECT 73.380 19.265 92.825 19.705 ;
        RECT 74.425 17.780 75.665 19.265 ;
        RECT 76.335 17.610 76.510 19.265 ;
        RECT 77.835 17.600 80.295 19.265 ;
        RECT 80.760 17.695 81.175 19.265 ;
        RECT 80.760 17.645 81.180 17.695 ;
        RECT 80.940 16.800 81.180 17.645 ;
        RECT 82.080 17.600 84.520 19.265 ;
        RECT 87.485 17.820 88.075 19.265 ;
        RECT 89.895 17.830 90.485 19.265 ;
        RECT 73.745 6.580 78.545 6.755 ;
        RECT 79.985 6.740 85.885 6.755 ;
        RECT 86.365 6.740 96.165 6.755 ;
        RECT 96.645 6.740 106.445 6.755 ;
        RECT 106.925 6.740 116.725 6.755 ;
        RECT 117.205 6.740 127.005 6.755 ;
        RECT 127.485 6.740 137.285 6.755 ;
        RECT 79.985 6.580 137.285 6.740 ;
        RECT 73.745 6.410 138.725 6.580 ;
        RECT 73.745 6.400 78.935 6.410 ;
        RECT 79.500 6.400 137.765 6.410 ;
        RECT 74.850 5.295 75.045 6.400 ;
        RECT 75.275 5.770 75.520 6.400 ;
        RECT 75.275 5.595 77.540 5.770 ;
        RECT 78.635 5.370 78.935 6.400 ;
        RECT 80.145 5.740 80.535 6.400 ;
        RECT 80.145 5.550 84.595 5.740 ;
        RECT 80.455 5.520 84.595 5.550 ;
        RECT 85.975 5.370 86.275 6.400 ;
        RECT 86.865 5.115 87.065 6.400 ;
        RECT 87.710 5.130 87.880 6.400 ;
        RECT 88.650 5.115 88.820 6.400 ;
        RECT 92.140 5.095 95.995 6.400 ;
        RECT 96.255 5.370 96.555 6.400 ;
        RECT 97.145 5.115 97.345 6.400 ;
        RECT 97.990 5.130 98.160 6.400 ;
        RECT 98.930 5.115 99.100 6.400 ;
        RECT 102.420 5.095 106.275 6.400 ;
        RECT 106.535 5.370 106.835 6.400 ;
        RECT 107.425 5.115 107.625 6.400 ;
        RECT 108.270 5.130 108.440 6.400 ;
        RECT 109.210 5.115 109.380 6.400 ;
        RECT 112.700 5.095 116.555 6.400 ;
        RECT 116.815 5.370 117.115 6.400 ;
        RECT 117.705 5.115 117.905 6.400 ;
        RECT 118.550 5.130 118.720 6.400 ;
        RECT 119.490 5.115 119.660 6.400 ;
        RECT 122.980 5.095 126.835 6.400 ;
        RECT 127.095 5.370 127.395 6.400 ;
        RECT 127.985 5.115 128.185 6.400 ;
        RECT 128.830 5.130 129.000 6.400 ;
        RECT 129.770 5.115 129.940 6.400 ;
        RECT 133.260 5.095 137.115 6.400 ;
        RECT 137.375 5.370 137.675 6.400 ;
      LAYER met1 ;
        RECT 72.240 19.210 92.900 19.695 ;
        RECT 72.240 12.210 73.010 19.210 ;
        RECT 73.380 19.205 92.900 19.210 ;
        RECT 75.860 12.500 76.000 14.165 ;
        RECT 76.420 12.500 76.560 14.165 ;
        RECT 76.980 12.500 77.120 14.165 ;
        RECT 77.350 12.500 77.620 14.165 ;
        RECT 77.850 12.500 77.990 14.165 ;
        RECT 78.410 12.500 78.550 14.165 ;
        RECT 78.970 12.500 79.110 14.165 ;
        RECT 75.860 12.180 79.110 12.500 ;
        RECT 75.860 10.515 76.000 12.180 ;
        RECT 76.420 10.515 76.560 12.180 ;
        RECT 76.980 10.515 77.120 12.180 ;
        RECT 77.350 10.515 77.620 12.180 ;
        RECT 77.850 10.515 77.990 12.180 ;
        RECT 78.410 10.515 78.550 12.180 ;
        RECT 78.970 10.515 79.110 12.180 ;
        RECT 80.730 12.500 80.870 14.165 ;
        RECT 81.290 12.500 81.430 14.165 ;
        RECT 81.850 12.500 81.990 14.165 ;
        RECT 82.220 12.500 82.490 14.165 ;
        RECT 82.720 12.500 82.860 14.165 ;
        RECT 83.280 12.500 83.420 14.165 ;
        RECT 83.840 12.500 83.980 14.165 ;
        RECT 80.730 12.180 83.980 12.500 ;
        RECT 80.730 10.515 80.870 12.180 ;
        RECT 81.290 10.515 81.430 12.180 ;
        RECT 81.850 10.515 81.990 12.180 ;
        RECT 82.220 10.515 82.490 12.180 ;
        RECT 82.720 10.515 82.860 12.180 ;
        RECT 83.280 10.515 83.420 12.180 ;
        RECT 83.840 10.515 83.980 12.180 ;
        RECT 73.745 6.250 138.725 6.740 ;
      LAYER met2 ;
        RECT 77.350 14.165 77.620 14.635 ;
        RECT 82.220 14.165 82.490 14.635 ;
        RECT 75.765 14.025 79.205 14.165 ;
        RECT 80.635 14.025 84.075 14.165 ;
        RECT 77.345 13.605 77.625 14.025 ;
        RECT 82.215 13.605 82.495 14.025 ;
        RECT 75.765 13.465 79.205 13.605 ;
        RECT 80.635 13.465 84.075 13.605 ;
        RECT 72.280 12.475 72.950 13.225 ;
        RECT 77.345 13.045 77.625 13.465 ;
        RECT 82.215 13.045 82.495 13.465 ;
        RECT 75.765 12.905 79.205 13.045 ;
        RECT 80.635 12.905 84.075 13.045 ;
        RECT 77.345 12.480 77.625 12.905 ;
        RECT 82.215 12.480 82.495 12.905 ;
        RECT 75.665 12.475 79.305 12.480 ;
        RECT 80.535 12.475 84.175 12.480 ;
        RECT 72.280 12.205 84.545 12.475 ;
        RECT 75.665 12.200 79.305 12.205 ;
        RECT 80.535 12.200 84.175 12.205 ;
        RECT 77.345 11.775 77.625 12.200 ;
        RECT 82.215 11.775 82.495 12.200 ;
        RECT 75.765 11.635 79.205 11.775 ;
        RECT 80.635 11.635 84.075 11.775 ;
        RECT 77.345 11.215 77.625 11.635 ;
        RECT 82.215 11.215 82.495 11.635 ;
        RECT 75.765 11.075 79.205 11.215 ;
        RECT 80.635 11.075 84.075 11.215 ;
        RECT 77.345 10.655 77.625 11.075 ;
        RECT 82.215 10.655 82.495 11.075 ;
        RECT 75.765 10.515 79.205 10.655 ;
        RECT 80.635 10.515 84.075 10.655 ;
        RECT 77.350 7.200 77.620 10.515 ;
        RECT 82.220 10.045 82.490 10.515 ;
        RECT 77.350 7.140 77.625 7.200 ;
        RECT 77.355 6.735 77.625 7.140 ;
        RECT 73.825 6.250 79.695 6.735 ;
        RECT 80.645 6.290 138.700 6.685 ;
      LAYER met3 ;
        RECT 75.925 12.505 76.225 14.005 ;
        RECT 77.320 12.505 77.650 14.005 ;
        RECT 78.745 12.505 79.045 14.005 ;
        RECT 75.925 12.175 79.045 12.505 ;
        RECT 75.925 10.675 76.225 12.175 ;
        RECT 77.320 10.675 77.650 12.175 ;
        RECT 78.745 10.675 79.045 12.175 ;
        RECT 80.795 12.505 81.095 14.005 ;
        RECT 82.190 12.505 82.520 14.005 ;
        RECT 83.615 12.505 83.915 14.005 ;
        RECT 80.795 12.175 83.915 12.505 ;
        RECT 80.795 10.675 81.095 12.175 ;
        RECT 82.190 10.675 82.520 12.175 ;
        RECT 83.615 10.675 83.915 12.175 ;
        RECT 73.825 6.235 138.700 6.735 ;
    END
    PORT
      LAYER nwell ;
        RECT 1.370 18.980 68.950 20.255 ;
        RECT 1.370 18.395 45.865 18.980 ;
        RECT 48.040 18.395 68.950 18.980 ;
        RECT 24.575 18.355 30.220 18.395 ;
        RECT 28.700 18.290 30.220 18.355 ;
        RECT 53.075 18.315 55.225 18.395 ;
        RECT 62.045 18.345 67.795 18.395 ;
        RECT 62.045 18.260 63.085 18.345 ;
      LAYER li1 ;
        RECT 1.560 19.980 68.760 20.150 ;
        RECT 1.815 18.555 2.145 19.980 ;
        RECT 5.090 19.135 5.420 19.980 ;
        RECT 7.735 18.555 8.065 19.980 ;
        RECT 9.245 18.685 9.575 19.980 ;
        RECT 10.850 19.135 11.180 19.980 ;
        RECT 13.495 18.555 13.825 19.980 ;
        RECT 14.610 18.940 14.910 19.980 ;
        RECT 15.620 18.765 15.950 19.980 ;
        RECT 16.630 19.255 16.960 19.980 ;
        RECT 19.030 19.700 19.360 19.980 ;
        RECT 21.250 19.700 21.585 19.980 ;
        RECT 22.345 19.025 22.515 19.980 ;
        RECT 23.275 19.255 23.525 19.980 ;
        RECT 24.255 19.385 24.505 19.980 ;
        RECT 25.185 19.385 25.515 19.980 ;
        RECT 27.600 19.490 27.945 19.980 ;
        RECT 28.940 18.475 29.190 19.980 ;
        RECT 30.995 19.070 31.220 19.980 ;
        RECT 31.970 18.840 32.185 19.980 ;
        RECT 33.770 18.555 34.065 19.980 ;
        RECT 34.770 18.940 35.070 19.980 ;
        RECT 36.305 19.385 36.745 19.980 ;
        RECT 38.345 18.675 38.675 19.980 ;
        RECT 39.615 18.835 39.945 19.980 ;
        RECT 41.255 18.685 41.585 19.980 ;
        RECT 42.450 18.940 42.750 19.980 ;
        RECT 42.955 19.700 44.275 19.980 ;
        RECT 42.955 18.675 43.350 19.700 ;
        RECT 45.785 19.360 46.035 19.980 ;
        RECT 48.830 19.500 49.340 19.980 ;
        RECT 52.105 19.025 52.465 19.980 ;
        RECT 53.205 19.025 53.535 19.980 ;
        RECT 54.105 18.475 54.435 19.980 ;
        RECT 55.315 18.555 55.645 19.980 ;
        RECT 56.315 18.555 56.645 19.980 ;
        RECT 57.380 18.730 57.710 19.980 ;
        RECT 58.850 19.465 59.200 19.980 ;
        RECT 60.520 19.385 60.690 19.980 ;
        RECT 62.710 19.200 63.050 19.980 ;
        RECT 64.320 19.240 64.715 19.980 ;
        RECT 66.855 19.265 67.185 19.980 ;
        RECT 67.865 19.325 68.195 19.980 ;
      LAYER met1 ;
        RECT 1.560 19.820 68.760 20.310 ;
      LAYER met2 ;
        RECT 4.750 19.830 55.755 20.310 ;
        RECT 56.515 19.840 57.400 20.310 ;
        RECT 58.185 19.820 64.925 20.315 ;
        RECT 67.060 19.830 68.760 20.300 ;
      LAYER met3 ;
        RECT 1.545 19.830 68.980 20.310 ;
        RECT 1.545 19.825 68.760 19.830 ;
    END
    PORT
      LAYER nwell ;
        RECT 4.250 5.585 68.950 7.445 ;
        RECT 24.575 5.545 30.220 5.585 ;
        RECT 28.700 5.480 30.220 5.545 ;
        RECT 56.765 5.535 62.515 5.585 ;
        RECT 56.765 5.450 57.805 5.535 ;
      LAYER li1 ;
        RECT 4.440 7.170 68.760 7.340 ;
        RECT 4.545 6.250 4.875 7.170 ;
        RECT 4.545 5.875 4.795 6.250 ;
        RECT 6.685 5.865 7.015 7.170 ;
        RECT 8.615 6.575 9.055 7.170 ;
        RECT 10.850 6.325 11.180 7.170 ;
        RECT 13.495 5.745 13.825 7.170 ;
        RECT 14.610 6.130 14.910 7.170 ;
        RECT 15.620 5.955 15.950 7.170 ;
        RECT 16.630 6.445 16.960 7.170 ;
        RECT 19.030 6.890 19.360 7.170 ;
        RECT 21.250 6.890 21.585 7.170 ;
        RECT 22.345 6.215 22.515 7.170 ;
        RECT 23.275 6.445 23.525 7.170 ;
        RECT 24.255 6.575 24.505 7.170 ;
        RECT 25.185 6.575 25.515 7.170 ;
        RECT 27.600 6.680 27.945 7.170 ;
        RECT 28.940 5.665 29.190 7.170 ;
        RECT 30.995 6.260 31.220 7.170 ;
        RECT 31.970 6.030 32.185 7.170 ;
        RECT 33.770 5.745 34.065 7.170 ;
        RECT 34.770 6.130 35.070 7.170 ;
        RECT 35.840 6.115 36.170 7.170 ;
        RECT 36.875 6.115 37.210 7.170 ;
        RECT 38.705 6.575 39.145 7.170 ;
        RECT 40.745 5.865 41.075 7.170 ;
        RECT 41.775 5.985 42.105 7.170 ;
        RECT 42.800 6.245 43.130 7.170 ;
        RECT 43.835 5.745 44.165 7.170 ;
        RECT 44.850 6.215 45.590 7.170 ;
        RECT 46.215 6.215 46.545 7.170 ;
        RECT 47.840 6.115 48.170 7.170 ;
        RECT 48.875 6.115 49.210 7.170 ;
        RECT 49.650 6.130 49.950 7.170 ;
        RECT 50.130 6.130 50.430 7.170 ;
        RECT 50.610 6.130 50.910 7.170 ;
        RECT 51.090 6.130 51.390 7.170 ;
        RECT 52.100 5.920 52.430 7.170 ;
        RECT 53.570 6.655 53.920 7.170 ;
        RECT 55.240 6.575 55.410 7.170 ;
        RECT 57.430 6.390 57.770 7.170 ;
        RECT 59.040 6.430 59.435 7.170 ;
        RECT 61.575 6.455 61.905 7.170 ;
        RECT 62.585 6.515 62.915 7.170 ;
        RECT 63.585 6.585 63.915 7.170 ;
        RECT 64.485 6.585 64.815 7.170 ;
        RECT 65.490 6.130 65.790 7.170 ;
        RECT 65.995 5.745 66.245 7.170 ;
        RECT 66.895 6.185 67.145 7.170 ;
        RECT 67.875 5.845 68.125 7.170 ;
      LAYER met1 ;
        RECT 4.440 7.010 68.760 7.500 ;
      LAYER met2 ;
        RECT 5.000 7.015 5.380 7.500 ;
        RECT 6.440 7.015 10.630 7.500 ;
        RECT 11.165 7.000 22.560 7.500 ;
        RECT 23.145 7.015 25.155 7.510 ;
        RECT 25.610 7.015 30.910 7.495 ;
        RECT 31.395 7.020 36.090 7.500 ;
        RECT 36.590 7.010 39.515 7.495 ;
        RECT 40.140 7.005 40.910 7.500 ;
        RECT 41.400 7.005 42.295 7.500 ;
        RECT 43.365 7.020 43.755 7.500 ;
        RECT 44.785 7.015 54.865 7.505 ;
        RECT 55.345 7.010 57.720 7.505 ;
        RECT 58.200 7.015 61.590 7.500 ;
        RECT 62.095 7.015 64.725 7.510 ;
        RECT 65.245 7.015 66.340 7.500 ;
        RECT 66.930 7.010 68.765 7.505 ;
      LAYER met3 ;
        RECT 1.560 7.020 68.980 7.500 ;
        RECT 1.560 7.015 68.765 7.020 ;
        RECT 1.560 7.010 4.670 7.015 ;
    END
  END VPWR
  PIN VGND
    USE GROUND ;
    PORT
      LAYER pwell ;
        RECT 14.545 8.385 14.975 9.470 ;
        RECT 34.705 8.385 35.135 9.470 ;
        RECT 41.425 8.385 41.855 9.470 ;
        RECT 41.905 8.385 42.335 9.470 ;
        RECT 42.385 8.385 42.815 9.470 ;
        RECT 68.305 8.385 68.735 9.470 ;
      LAYER li1 ;
        RECT 2.250 8.280 2.650 9.205 ;
        RECT 3.250 8.280 3.580 9.035 ;
        RECT 4.350 8.280 4.680 9.035 ;
        RECT 5.055 8.280 5.305 9.325 ;
        RECT 5.915 8.280 6.245 9.325 ;
        RECT 6.535 8.280 7.135 9.185 ;
        RECT 8.180 8.280 8.510 9.390 ;
        RECT 9.570 8.280 9.900 8.940 ;
        RECT 10.825 8.875 11.035 9.325 ;
        RECT 10.825 8.280 11.205 8.875 ;
        RECT 13.495 8.280 13.825 9.005 ;
        RECT 14.610 8.280 14.910 9.300 ;
        RECT 15.625 8.280 15.940 8.875 ;
        RECT 16.600 8.280 16.930 9.255 ;
        RECT 18.840 8.280 19.090 8.715 ;
        RECT 20.845 8.280 21.175 8.755 ;
        RECT 22.365 8.280 22.615 8.985 ;
        RECT 24.190 8.280 24.440 9.025 ;
        RECT 25.250 8.280 25.580 8.995 ;
        RECT 28.155 8.280 28.485 8.605 ;
        RECT 30.695 8.280 31.155 8.875 ;
        RECT 32.300 8.280 32.550 9.325 ;
        RECT 33.805 8.280 34.055 9.325 ;
        RECT 34.770 8.280 35.070 9.300 ;
        RECT 35.890 8.280 36.220 9.205 ;
        RECT 37.860 8.280 38.190 8.940 ;
        RECT 39.250 8.280 39.580 9.390 ;
        RECT 40.625 8.280 41.225 9.185 ;
        RECT 41.490 8.280 41.790 9.300 ;
        RECT 41.970 8.280 42.270 9.300 ;
        RECT 42.450 8.280 42.750 9.300 ;
        RECT 43.465 8.280 43.715 9.325 ;
        RECT 44.970 8.280 45.220 9.325 ;
        RECT 46.365 8.280 46.825 8.875 ;
        RECT 49.035 8.280 49.365 8.605 ;
        RECT 51.940 8.280 52.270 8.995 ;
        RECT 53.080 8.280 53.330 9.025 ;
        RECT 55.090 8.280 55.420 9.205 ;
        RECT 57.245 8.280 57.575 9.325 ;
        RECT 58.685 8.280 59.015 9.325 ;
        RECT 59.770 8.280 60.100 9.205 ;
        RECT 61.215 8.280 61.465 9.325 ;
        RECT 62.075 8.280 62.405 9.325 ;
        RECT 62.655 8.280 62.905 9.325 ;
        RECT 63.515 8.280 63.845 9.325 ;
        RECT 64.095 8.280 64.345 9.325 ;
        RECT 64.955 8.280 65.285 9.325 ;
        RECT 65.535 8.280 65.785 9.325 ;
        RECT 66.395 8.280 66.725 9.325 ;
        RECT 67.325 8.280 67.655 9.325 ;
        RECT 68.370 8.280 68.670 9.300 ;
        RECT 2.040 8.110 68.760 8.280 ;
      LAYER met1 ;
        RECT 2.040 7.950 68.760 8.440 ;
      LAYER met2 ;
        RECT 3.085 7.930 4.400 8.435 ;
        RECT 5.055 7.955 5.380 8.440 ;
        RECT 6.440 7.950 10.640 8.445 ;
        RECT 11.165 7.940 22.560 8.440 ;
        RECT 23.135 7.945 25.155 8.440 ;
        RECT 25.620 7.955 30.910 8.445 ;
        RECT 31.410 7.945 36.100 8.445 ;
        RECT 36.590 7.950 39.520 8.430 ;
        RECT 40.150 7.950 40.910 8.435 ;
        RECT 41.410 7.950 42.295 8.435 ;
        RECT 43.340 7.945 43.775 8.440 ;
        RECT 44.800 7.955 54.865 8.445 ;
        RECT 55.360 7.940 57.720 8.445 ;
        RECT 58.190 7.940 61.590 8.450 ;
        RECT 62.085 7.950 64.725 8.450 ;
        RECT 65.240 7.955 66.340 8.435 ;
        RECT 66.930 7.945 68.770 8.445 ;
      LAYER met3 ;
        RECT 1.560 7.955 68.980 8.445 ;
        RECT 1.560 7.950 4.670 7.955 ;
    END
    PORT
      LAYER pwell ;
        RECT 78.570 3.355 79.000 4.440 ;
        RECT 85.910 3.355 86.340 4.440 ;
        RECT 96.190 3.355 96.620 4.440 ;
        RECT 106.470 3.355 106.900 4.440 ;
        RECT 116.750 3.355 117.180 4.440 ;
        RECT 127.030 3.355 127.460 4.440 ;
        RECT 137.310 3.355 137.740 4.440 ;
      LAYER li1 ;
        RECT 74.840 3.305 75.035 4.425 ;
        RECT 76.015 3.305 76.210 4.400 ;
        RECT 78.635 3.305 78.935 4.270 ;
        RECT 80.685 3.305 82.610 3.800 ;
        RECT 83.870 3.305 84.405 3.785 ;
        RECT 85.975 3.305 86.275 4.270 ;
        RECT 90.480 4.155 96.000 4.545 ;
        RECT 89.905 4.135 96.000 4.155 ;
        RECT 89.885 4.125 96.000 4.135 ;
        RECT 89.860 4.115 96.000 4.125 ;
        RECT 89.840 4.100 96.000 4.115 ;
        RECT 89.770 4.025 96.000 4.100 ;
        RECT 89.400 3.985 96.000 4.025 ;
        RECT 89.400 3.970 89.985 3.985 ;
        RECT 89.400 3.915 89.970 3.970 ;
        RECT 89.400 3.855 89.935 3.915 ;
        RECT 88.410 3.465 88.750 3.650 ;
        RECT 73.745 3.250 78.935 3.305 ;
        RECT 80.035 3.260 86.435 3.305 ;
        RECT 88.500 3.260 88.670 3.465 ;
        RECT 90.480 3.305 96.000 3.985 ;
        RECT 96.255 3.305 96.555 4.270 ;
        RECT 100.760 4.155 106.280 4.545 ;
        RECT 100.185 4.135 106.280 4.155 ;
        RECT 100.165 4.125 106.280 4.135 ;
        RECT 100.140 4.115 106.280 4.125 ;
        RECT 100.120 4.100 106.280 4.115 ;
        RECT 100.050 4.025 106.280 4.100 ;
        RECT 99.680 3.985 106.280 4.025 ;
        RECT 99.680 3.970 100.265 3.985 ;
        RECT 99.680 3.915 100.250 3.970 ;
        RECT 99.680 3.855 100.215 3.915 ;
        RECT 98.690 3.465 99.030 3.650 ;
        RECT 90.480 3.260 96.715 3.305 ;
        RECT 98.780 3.260 98.950 3.465 ;
        RECT 100.760 3.305 106.280 3.985 ;
        RECT 106.535 3.305 106.835 4.270 ;
        RECT 111.040 4.155 116.560 4.545 ;
        RECT 110.465 4.135 116.560 4.155 ;
        RECT 110.445 4.125 116.560 4.135 ;
        RECT 110.420 4.115 116.560 4.125 ;
        RECT 110.400 4.100 116.560 4.115 ;
        RECT 110.330 4.025 116.560 4.100 ;
        RECT 109.960 3.985 116.560 4.025 ;
        RECT 109.960 3.970 110.545 3.985 ;
        RECT 109.960 3.915 110.530 3.970 ;
        RECT 109.960 3.855 110.495 3.915 ;
        RECT 108.970 3.465 109.310 3.650 ;
        RECT 100.760 3.260 106.995 3.305 ;
        RECT 109.060 3.260 109.230 3.465 ;
        RECT 111.040 3.305 116.560 3.985 ;
        RECT 116.815 3.305 117.115 4.270 ;
        RECT 121.320 4.155 126.840 4.545 ;
        RECT 120.745 4.135 126.840 4.155 ;
        RECT 120.725 4.125 126.840 4.135 ;
        RECT 120.700 4.115 126.840 4.125 ;
        RECT 120.680 4.100 126.840 4.115 ;
        RECT 120.610 4.025 126.840 4.100 ;
        RECT 120.240 3.985 126.840 4.025 ;
        RECT 120.240 3.970 120.825 3.985 ;
        RECT 120.240 3.915 120.810 3.970 ;
        RECT 120.240 3.855 120.775 3.915 ;
        RECT 119.250 3.465 119.590 3.650 ;
        RECT 111.040 3.260 117.275 3.305 ;
        RECT 119.340 3.260 119.510 3.465 ;
        RECT 121.320 3.305 126.840 3.985 ;
        RECT 127.095 3.305 127.395 4.270 ;
        RECT 131.600 4.155 137.120 4.545 ;
        RECT 131.025 4.135 137.120 4.155 ;
        RECT 131.005 4.125 137.120 4.135 ;
        RECT 130.980 4.115 137.120 4.125 ;
        RECT 130.960 4.100 137.120 4.115 ;
        RECT 130.890 4.025 137.120 4.100 ;
        RECT 130.520 3.985 137.120 4.025 ;
        RECT 130.520 3.970 131.105 3.985 ;
        RECT 130.520 3.915 131.090 3.970 ;
        RECT 130.520 3.855 131.055 3.915 ;
        RECT 129.530 3.465 129.870 3.650 ;
        RECT 121.320 3.260 127.555 3.305 ;
        RECT 129.620 3.260 129.790 3.465 ;
        RECT 131.600 3.310 137.120 3.985 ;
        RECT 137.375 3.310 137.675 4.270 ;
        RECT 131.600 3.260 137.675 3.310 ;
        RECT 80.035 3.250 137.675 3.260 ;
        RECT 73.745 3.080 138.725 3.250 ;
        RECT 73.745 2.920 78.545 3.080 ;
        RECT 80.035 2.920 85.885 3.080 ;
        RECT 86.365 2.920 96.165 3.080 ;
        RECT 96.645 2.920 106.445 3.080 ;
        RECT 106.925 2.920 116.725 3.080 ;
        RECT 117.205 2.920 127.005 3.080 ;
        RECT 127.485 2.920 137.285 3.080 ;
      LAYER met1 ;
        RECT 82.520 6.040 86.305 6.045 ;
        RECT 79.125 5.580 86.305 6.040 ;
        RECT 79.125 4.930 80.010 5.580 ;
        RECT 80.715 4.930 86.305 5.580 ;
        RECT 79.125 4.050 86.305 4.930 ;
        RECT 79.125 3.410 82.855 4.050 ;
        RECT 83.540 3.410 84.950 4.050 ;
        RECT 85.720 3.410 86.305 4.050 ;
        RECT 73.745 2.920 138.725 3.410 ;
      LAYER met2 ;
        RECT 73.745 2.970 82.910 3.405 ;
        RECT 83.615 2.970 85.060 3.405 ;
        RECT 85.710 2.970 87.510 3.405 ;
        RECT 89.340 2.970 97.775 3.405 ;
        RECT 99.675 2.970 108.110 3.405 ;
        RECT 109.915 2.970 118.350 3.405 ;
        RECT 120.220 2.970 128.525 3.405 ;
        RECT 130.470 2.970 138.700 3.405 ;
      LAYER met3 ;
        RECT 73.825 2.960 138.700 3.410 ;
    END
    PORT
      LAYER pwell ;
        RECT 14.545 12.650 14.975 13.735 ;
        RECT 34.705 12.650 35.135 13.735 ;
        RECT 68.305 12.650 68.735 13.735 ;
      LAYER li1 ;
        RECT 3.005 12.545 3.335 13.590 ;
        RECT 4.255 12.545 4.610 13.455 ;
        RECT 5.415 12.545 5.745 13.300 ;
        RECT 6.535 12.545 7.135 13.450 ;
        RECT 8.180 12.545 8.510 13.655 ;
        RECT 9.570 12.545 9.900 13.205 ;
        RECT 10.825 13.140 11.035 13.590 ;
        RECT 10.825 12.545 11.205 13.140 ;
        RECT 13.495 12.545 13.825 13.270 ;
        RECT 14.610 12.545 14.910 13.565 ;
        RECT 15.625 12.545 15.940 13.140 ;
        RECT 16.600 12.545 16.930 13.520 ;
        RECT 18.840 12.545 19.090 12.980 ;
        RECT 20.845 12.545 21.175 13.020 ;
        RECT 22.365 12.545 22.615 13.250 ;
        RECT 24.190 12.545 24.440 13.290 ;
        RECT 25.250 12.545 25.580 13.260 ;
        RECT 28.155 12.545 28.485 12.870 ;
        RECT 30.695 12.545 31.155 13.140 ;
        RECT 32.300 12.545 32.550 13.590 ;
        RECT 33.805 12.545 34.055 13.590 ;
        RECT 34.770 12.545 35.070 13.565 ;
        RECT 35.890 12.545 36.220 13.470 ;
        RECT 37.860 12.545 38.190 13.205 ;
        RECT 39.250 12.545 39.580 13.655 ;
        RECT 40.625 12.545 41.225 13.450 ;
        RECT 41.950 12.545 42.620 13.250 ;
        RECT 44.830 12.545 45.080 13.290 ;
        RECT 45.890 12.545 46.220 13.260 ;
        RECT 48.795 12.545 49.125 12.870 ;
        RECT 51.335 12.545 51.795 13.140 ;
        RECT 52.940 12.545 53.190 13.590 ;
        RECT 54.445 12.545 54.695 13.590 ;
        RECT 55.435 12.545 55.765 13.590 ;
        RECT 56.375 12.545 56.625 13.590 ;
        RECT 57.245 12.545 57.575 13.590 ;
        RECT 58.685 12.545 59.015 13.590 ;
        RECT 60.125 12.545 60.455 13.590 ;
        RECT 61.215 12.545 61.465 13.590 ;
        RECT 62.075 12.545 62.405 13.590 ;
        RECT 62.655 12.545 62.905 13.590 ;
        RECT 63.515 12.545 63.845 13.590 ;
        RECT 64.095 12.545 64.345 13.590 ;
        RECT 64.955 12.545 65.285 13.590 ;
        RECT 65.535 12.545 65.785 13.590 ;
        RECT 66.395 12.545 66.725 13.590 ;
        RECT 67.325 12.545 67.655 13.590 ;
        RECT 68.370 12.545 68.670 13.565 ;
        RECT 2.520 12.375 68.760 12.545 ;
      LAYER met1 ;
        RECT 1.705 12.215 68.760 12.705 ;
      LAYER met2 ;
        RECT 2.975 12.220 3.880 12.710 ;
        RECT 4.380 12.215 4.870 12.710 ;
        RECT 6.480 12.220 10.605 12.725 ;
        RECT 11.155 12.210 22.640 12.705 ;
        RECT 23.220 12.370 25.070 12.695 ;
        RECT 25.615 12.220 30.925 12.710 ;
        RECT 31.460 12.210 36.095 12.700 ;
        RECT 36.585 12.215 38.980 12.710 ;
        RECT 40.200 12.210 43.270 12.720 ;
        RECT 44.810 12.215 51.545 12.715 ;
        RECT 52.040 12.220 53.760 12.705 ;
        RECT 54.250 12.220 54.870 12.700 ;
        RECT 55.415 12.220 55.800 12.705 ;
        RECT 56.285 12.230 56.805 12.705 ;
        RECT 57.320 12.210 58.065 12.695 ;
        RECT 58.700 12.210 59.180 12.690 ;
        RECT 59.680 12.205 60.525 12.690 ;
        RECT 62.075 12.215 63.985 12.695 ;
        RECT 64.480 12.205 66.330 12.710 ;
        RECT 66.920 12.215 68.755 12.705 ;
      LAYER met3 ;
        RECT 1.560 12.220 68.980 12.715 ;
    END
    PORT
      LAYER pwell ;
        RECT 14.545 16.925 14.975 18.010 ;
        RECT 34.705 16.925 35.135 18.010 ;
        RECT 42.385 16.925 42.815 18.010 ;
      LAYER li1 ;
        RECT 1.770 16.820 2.170 17.745 ;
        RECT 2.770 16.820 3.100 17.575 ;
        RECT 3.870 16.820 4.200 17.575 ;
        RECT 5.065 17.415 5.275 17.865 ;
        RECT 5.065 16.820 5.445 17.415 ;
        RECT 7.735 16.820 8.065 17.545 ;
        RECT 9.245 16.820 9.575 17.865 ;
        RECT 10.825 17.415 11.035 17.865 ;
        RECT 10.825 16.820 11.205 17.415 ;
        RECT 13.495 16.820 13.825 17.545 ;
        RECT 14.610 16.820 14.910 17.840 ;
        RECT 15.625 16.820 15.940 17.415 ;
        RECT 16.600 16.820 16.930 17.795 ;
        RECT 18.840 16.820 19.090 17.255 ;
        RECT 20.845 16.820 21.175 17.295 ;
        RECT 22.365 16.820 22.615 17.525 ;
        RECT 24.190 16.820 24.440 17.565 ;
        RECT 25.250 16.820 25.580 17.535 ;
        RECT 28.155 16.820 28.485 17.145 ;
        RECT 30.695 16.820 31.155 17.415 ;
        RECT 32.300 16.820 32.550 17.865 ;
        RECT 33.805 16.820 34.055 17.865 ;
        RECT 34.770 16.820 35.070 17.840 ;
        RECT 35.460 16.820 35.790 17.480 ;
        RECT 36.850 16.820 37.180 17.930 ;
        RECT 38.225 16.820 38.825 17.725 ;
        RECT 40.000 16.820 40.525 17.865 ;
        RECT 41.265 16.820 41.680 17.575 ;
        RECT 42.450 16.820 42.750 17.840 ;
        RECT 43.985 16.820 44.315 17.545 ;
        RECT 45.045 16.820 45.375 17.515 ;
        RECT 48.445 16.820 48.695 17.225 ;
        RECT 52.255 16.820 52.585 17.455 ;
        RECT 53.685 16.820 53.855 17.835 ;
        RECT 54.465 16.820 54.805 17.335 ;
        RECT 55.470 16.820 55.720 17.865 ;
        RECT 56.400 16.820 56.660 17.865 ;
        RECT 57.375 16.820 57.705 17.675 ;
        RECT 58.945 16.820 59.275 17.405 ;
        RECT 60.005 16.820 60.695 17.405 ;
        RECT 62.575 16.820 62.905 17.685 ;
        RECT 64.325 16.820 64.655 17.450 ;
        RECT 66.895 16.820 67.155 17.745 ;
        RECT 67.965 16.820 68.215 17.575 ;
        RECT 1.560 16.650 68.760 16.820 ;
      LAYER met1 ;
        RECT 1.560 16.490 68.760 16.980 ;
      LAYER met2 ;
        RECT 2.300 16.490 3.100 16.985 ;
        RECT 4.440 16.495 4.835 16.990 ;
        RECT 5.900 16.495 8.790 16.990 ;
        RECT 9.340 16.490 10.650 16.970 ;
        RECT 11.150 16.490 22.595 16.980 ;
        RECT 23.265 16.495 25.135 16.990 ;
        RECT 25.670 16.485 30.935 16.985 ;
        RECT 31.390 16.485 34.215 16.985 ;
        RECT 34.680 16.485 36.105 16.980 ;
        RECT 36.570 16.490 39.480 16.980 ;
        RECT 40.185 16.490 42.230 16.985 ;
        RECT 42.890 16.490 56.185 16.995 ;
        RECT 57.350 16.495 58.055 16.970 ;
        RECT 58.675 16.510 63.945 16.975 ;
        RECT 64.530 16.490 64.920 16.965 ;
        RECT 65.470 16.490 66.310 16.975 ;
        RECT 66.925 16.490 67.540 16.985 ;
        RECT 68.105 16.520 68.755 16.970 ;
      LAYER met3 ;
        RECT 1.550 16.965 68.840 16.970 ;
        RECT 1.550 16.485 69.005 16.965 ;
    END
    PORT
      LAYER pwell ;
        RECT 14.545 4.115 14.975 5.200 ;
        RECT 34.705 4.115 35.135 5.200 ;
        RECT 49.585 4.115 50.015 5.200 ;
        RECT 50.065 4.115 50.495 5.200 ;
        RECT 50.545 4.115 50.975 5.200 ;
        RECT 51.025 4.115 51.455 5.200 ;
        RECT 65.425 4.115 65.855 5.200 ;
      LAYER li1 ;
        RECT 4.555 4.635 4.800 4.935 ;
        RECT 4.555 4.010 4.885 4.635 ;
        RECT 5.415 4.010 5.745 4.635 ;
        RECT 6.535 4.010 7.135 4.915 ;
        RECT 8.180 4.010 8.510 5.120 ;
        RECT 9.570 4.010 9.900 4.670 ;
        RECT 10.825 4.605 11.035 5.055 ;
        RECT 10.825 4.010 11.205 4.605 ;
        RECT 13.495 4.010 13.825 4.735 ;
        RECT 14.610 4.010 14.910 5.030 ;
        RECT 15.625 4.010 15.940 4.605 ;
        RECT 16.600 4.010 16.930 4.985 ;
        RECT 18.840 4.010 19.090 4.445 ;
        RECT 20.845 4.010 21.175 4.485 ;
        RECT 22.365 4.010 22.615 4.715 ;
        RECT 24.190 4.010 24.440 4.755 ;
        RECT 25.250 4.010 25.580 4.725 ;
        RECT 28.155 4.010 28.485 4.335 ;
        RECT 30.695 4.010 31.155 4.605 ;
        RECT 32.300 4.010 32.550 5.055 ;
        RECT 33.805 4.010 34.055 5.055 ;
        RECT 34.770 4.010 35.070 5.030 ;
        RECT 35.890 4.010 36.220 4.935 ;
        RECT 37.860 4.010 38.190 4.670 ;
        RECT 39.250 4.010 39.580 5.120 ;
        RECT 40.625 4.010 41.225 4.915 ;
        RECT 41.510 4.010 42.185 4.525 ;
        RECT 45.135 4.010 45.465 5.105 ;
        RECT 47.890 4.010 48.220 4.935 ;
        RECT 49.650 4.010 49.950 5.030 ;
        RECT 50.130 4.010 50.430 5.030 ;
        RECT 50.610 4.010 50.910 5.030 ;
        RECT 51.090 4.010 51.390 5.030 ;
        RECT 52.095 4.010 52.425 4.865 ;
        RECT 53.665 4.010 53.995 4.595 ;
        RECT 54.725 4.010 55.415 4.595 ;
        RECT 57.295 4.010 57.625 4.875 ;
        RECT 59.045 4.010 59.375 4.640 ;
        RECT 61.615 4.010 61.875 4.935 ;
        RECT 62.685 4.010 62.935 4.765 ;
        RECT 63.595 4.010 63.845 4.715 ;
        RECT 64.535 4.010 64.785 4.735 ;
        RECT 65.490 4.010 65.790 5.030 ;
        RECT 66.010 4.010 66.260 4.735 ;
        RECT 66.950 4.010 67.120 4.735 ;
        RECT 67.800 4.010 68.130 4.735 ;
        RECT 4.440 3.840 68.760 4.010 ;
      LAYER met1 ;
        RECT 3.555 3.685 68.760 4.170 ;
        RECT 4.440 3.680 68.760 3.685 ;
      LAYER met2 ;
        RECT 4.445 3.680 68.760 4.165 ;
      LAYER met3 ;
        RECT 1.560 3.685 68.980 4.165 ;
        RECT 4.435 3.670 68.780 3.685 ;
        RECT 4.450 3.645 68.780 3.670 ;
    END
  END VGND
  OBS
      LAYER pwell ;
        RECT 46.220 18.305 47.830 18.445 ;
        RECT 20.075 17.975 20.695 18.165 ;
        RECT 46.075 18.095 47.830 18.305 ;
        RECT 1.660 17.685 4.205 17.975 ;
        RECT 1.660 16.980 4.310 17.685 ;
        RECT 4.445 16.980 8.745 17.975 ;
        RECT 9.135 16.980 10.185 17.975 ;
        RECT 10.205 16.980 14.505 17.975 ;
        RECT 15.005 17.905 15.950 17.975 ;
        RECT 20.075 17.910 23.155 17.975 ;
        RECT 15.005 17.790 18.520 17.905 ;
        RECT 19.600 17.790 23.155 17.910 ;
        RECT 15.005 16.980 23.155 17.790 ;
        RECT 24.640 17.875 26.190 17.975 ;
        RECT 28.635 17.875 29.185 18.015 ;
        RECT 24.640 17.675 29.660 17.875 ;
        RECT 23.220 17.655 29.660 17.675 ;
        RECT 32.110 17.655 34.665 17.975 ;
        RECT 23.220 16.980 34.665 17.655 ;
        RECT 35.230 16.980 38.915 18.040 ;
        RECT 46.075 18.030 49.910 18.095 ;
        RECT 39.005 16.980 42.315 17.975 ;
        RECT 43.980 17.690 44.925 17.975 ;
        RECT 46.075 17.690 51.715 18.030 ;
        RECT 43.980 17.655 51.715 17.690 ;
        RECT 53.495 17.655 56.755 17.975 ;
        RECT 43.060 16.980 56.755 17.655 ;
        RECT 56.765 17.655 59.385 17.975 ;
        RECT 61.545 17.655 63.015 17.875 ;
        RECT 66.355 17.690 67.765 17.975 ;
        RECT 64.215 17.685 67.765 17.690 ;
        RECT 64.215 17.655 68.755 17.685 ;
        RECT 56.765 16.980 68.755 17.655 ;
        RECT 1.560 16.735 14.520 16.980 ;
        RECT 15.000 16.735 34.680 16.980 ;
        RECT 35.160 16.735 42.360 16.980 ;
        RECT 42.840 16.735 68.760 16.980 ;
        RECT 101.990 14.410 102.095 14.655 ;
        RECT 114.215 14.410 114.320 14.655 ;
        RECT 126.480 14.410 126.585 14.655 ;
        RECT 138.730 14.410 138.835 14.655 ;
        RECT 2.895 12.705 3.945 13.700 ;
        RECT 3.965 12.705 6.355 13.700 ;
        RECT 6.445 12.705 10.130 13.765 ;
        RECT 20.075 13.700 20.695 13.890 ;
        RECT 36.465 13.830 37.410 13.910 ;
        RECT 10.205 12.705 14.505 13.700 ;
        RECT 15.005 13.630 15.950 13.700 ;
        RECT 20.075 13.635 23.155 13.700 ;
        RECT 15.005 13.515 18.520 13.630 ;
        RECT 19.600 13.515 23.155 13.635 ;
        RECT 15.005 12.705 23.155 13.515 ;
        RECT 24.640 13.600 26.190 13.700 ;
        RECT 28.635 13.600 29.185 13.740 ;
        RECT 24.640 13.400 29.660 13.600 ;
        RECT 23.220 13.380 29.660 13.400 ;
        RECT 32.110 13.380 34.665 13.700 ;
        RECT 23.220 12.705 34.665 13.380 ;
        RECT 35.280 12.705 37.410 13.830 ;
        RECT 37.630 12.705 41.315 13.765 ;
        RECT 41.405 12.705 43.695 13.700 ;
        RECT 45.280 13.600 46.830 13.700 ;
        RECT 49.275 13.600 49.825 13.740 ;
        RECT 45.280 13.400 50.300 13.600 ;
        RECT 43.860 13.380 50.300 13.400 ;
        RECT 52.750 13.380 55.305 13.700 ;
        RECT 43.860 12.705 55.305 13.380 ;
        RECT 55.325 12.705 56.735 13.700 ;
        RECT 57.135 12.705 58.185 13.700 ;
        RECT 58.575 12.705 59.625 13.700 ;
        RECT 60.015 12.705 61.065 13.700 ;
        RECT 61.105 12.705 62.515 13.700 ;
        RECT 62.545 12.705 63.955 13.700 ;
        RECT 63.985 12.705 65.395 13.700 ;
        RECT 65.425 12.705 66.835 13.700 ;
        RECT 67.215 12.705 68.265 13.700 ;
        RECT 2.520 12.460 14.520 12.705 ;
        RECT 15.000 12.460 34.680 12.705 ;
        RECT 35.160 12.460 68.280 12.705 ;
        RECT 77.630 11.795 77.750 12.050 ;
        RECT 82.500 11.795 82.620 12.050 ;
        RECT 88.425 11.795 88.545 12.050 ;
        RECT 93.150 11.795 93.270 12.050 ;
        RECT 2.140 9.145 4.685 9.435 ;
        RECT 2.140 8.440 4.790 9.145 ;
        RECT 4.945 8.440 6.355 9.435 ;
        RECT 6.445 8.440 10.130 9.500 ;
        RECT 20.075 9.435 20.695 9.625 ;
        RECT 36.465 9.565 37.410 9.645 ;
        RECT 55.665 9.565 56.610 9.645 ;
        RECT 10.205 8.440 14.505 9.435 ;
        RECT 15.005 9.365 15.950 9.435 ;
        RECT 20.075 9.370 23.155 9.435 ;
        RECT 15.005 9.250 18.520 9.365 ;
        RECT 19.600 9.250 23.155 9.370 ;
        RECT 15.005 8.440 23.155 9.250 ;
        RECT 24.640 9.335 26.190 9.435 ;
        RECT 28.635 9.335 29.185 9.475 ;
        RECT 24.640 9.135 29.660 9.335 ;
        RECT 23.220 9.115 29.660 9.135 ;
        RECT 32.110 9.115 34.665 9.435 ;
        RECT 23.220 8.440 34.665 9.115 ;
        RECT 35.280 8.440 37.410 9.565 ;
        RECT 37.630 8.440 41.315 9.500 ;
        RECT 42.855 9.115 45.410 9.435 ;
        RECT 48.335 9.335 48.885 9.475 ;
        RECT 51.330 9.335 52.880 9.435 ;
        RECT 47.860 9.135 52.880 9.335 ;
        RECT 47.860 9.115 54.300 9.135 ;
        RECT 42.855 8.440 54.300 9.115 ;
        RECT 54.480 8.440 56.610 9.565 ;
        RECT 57.135 8.440 58.185 9.435 ;
        RECT 58.575 8.440 59.625 9.435 ;
        RECT 59.660 8.440 61.030 9.435 ;
        RECT 61.105 8.440 62.515 9.435 ;
        RECT 62.545 8.440 63.955 9.435 ;
        RECT 63.985 8.440 65.395 9.435 ;
        RECT 65.425 8.440 66.835 9.435 ;
        RECT 67.215 8.440 68.265 9.435 ;
        RECT 2.040 8.195 14.520 8.440 ;
        RECT 15.000 8.195 34.680 8.440 ;
        RECT 35.160 8.195 41.400 8.440 ;
        RECT 42.840 8.195 68.280 8.440 ;
        RECT 4.445 4.170 6.355 5.165 ;
        RECT 6.445 4.170 10.130 5.230 ;
        RECT 20.075 5.165 20.695 5.355 ;
        RECT 36.465 5.295 37.410 5.375 ;
        RECT 45.615 5.295 47.120 5.375 ;
        RECT 48.465 5.295 49.410 5.375 ;
        RECT 10.205 4.170 14.505 5.165 ;
        RECT 15.005 5.095 15.950 5.165 ;
        RECT 20.075 5.100 23.155 5.165 ;
        RECT 15.005 4.980 18.520 5.095 ;
        RECT 19.600 4.980 23.155 5.100 ;
        RECT 15.005 4.170 23.155 4.980 ;
        RECT 24.640 5.065 26.190 5.165 ;
        RECT 28.635 5.065 29.185 5.205 ;
        RECT 24.640 4.865 29.660 5.065 ;
        RECT 23.220 4.845 29.660 4.865 ;
        RECT 32.110 4.845 34.665 5.165 ;
        RECT 23.220 4.170 34.665 4.845 ;
        RECT 35.280 4.170 37.410 5.295 ;
        RECT 37.630 4.170 41.315 5.230 ;
        RECT 41.775 5.045 44.230 5.165 ;
        RECT 41.775 4.715 44.250 5.045 ;
        RECT 41.405 4.170 44.250 4.715 ;
        RECT 44.525 4.170 47.120 5.295 ;
        RECT 47.280 4.170 49.410 5.295 ;
        RECT 51.485 4.845 54.105 5.165 ;
        RECT 56.265 4.845 57.735 5.065 ;
        RECT 61.075 4.880 62.485 5.165 ;
        RECT 58.935 4.875 62.485 4.880 ;
        RECT 58.935 4.845 63.475 4.875 ;
        RECT 51.485 4.170 63.475 4.845 ;
        RECT 63.485 4.170 65.395 4.845 ;
        RECT 65.900 4.170 68.755 4.845 ;
        RECT 75.445 4.535 76.795 4.605 ;
        RECT 4.440 3.925 14.520 4.170 ;
        RECT 15.000 3.925 34.680 4.170 ;
        RECT 35.160 3.925 49.560 4.170 ;
        RECT 51.480 3.925 65.400 4.170 ;
        RECT 65.880 3.925 68.760 4.170 ;
        RECT 74.265 3.410 76.795 4.535 ;
        RECT 79.030 3.410 79.980 4.545 ;
        RECT 80.490 3.410 82.750 4.380 ;
        RECT 83.760 3.410 84.440 4.400 ;
        RECT 86.845 4.255 88.090 4.615 ;
        RECT 89.285 4.255 96.130 4.615 ;
        RECT 86.845 3.410 96.130 4.255 ;
        RECT 97.125 4.255 98.370 4.615 ;
        RECT 99.565 4.255 106.410 4.615 ;
        RECT 97.125 3.410 106.410 4.255 ;
        RECT 107.405 4.255 108.650 4.615 ;
        RECT 109.845 4.255 116.690 4.615 ;
        RECT 107.405 3.410 116.690 4.255 ;
        RECT 117.685 4.255 118.930 4.615 ;
        RECT 120.125 4.255 126.970 4.615 ;
        RECT 117.685 3.410 126.970 4.255 ;
        RECT 127.965 4.255 129.210 4.615 ;
        RECT 130.405 4.255 137.250 4.615 ;
        RECT 127.965 3.410 137.250 4.255 ;
        RECT 137.770 3.410 138.720 4.545 ;
        RECT 73.745 3.165 78.545 3.410 ;
        RECT 79.025 3.165 85.885 3.410 ;
        RECT 86.365 3.165 96.165 3.410 ;
        RECT 96.645 3.165 106.445 3.410 ;
        RECT 106.925 3.165 116.725 3.410 ;
        RECT 117.205 3.165 127.005 3.410 ;
        RECT 127.485 3.165 137.285 3.410 ;
        RECT 137.765 3.165 138.725 3.410 ;
      LAYER li1 ;
        RECT 3.825 18.685 4.345 19.715 ;
        RECT 5.590 19.640 7.565 19.810 ;
        RECT 4.175 17.915 4.345 18.685 ;
        RECT 2.340 17.745 4.345 17.915 ;
        RECT 4.555 18.965 4.885 19.435 ;
        RECT 5.590 18.965 5.760 19.640 ;
        RECT 4.555 18.795 5.760 18.965 ;
        RECT 4.555 18.685 4.885 18.795 ;
        RECT 4.555 17.865 4.725 18.685 ;
        RECT 6.505 18.625 6.835 19.470 ;
        RECT 4.945 18.085 5.275 18.515 ;
        RECT 5.445 18.455 6.835 18.625 ;
        RECT 2.340 17.085 2.600 17.745 ;
        RECT 3.370 17.085 3.700 17.745 ;
        RECT 4.555 17.275 4.885 17.865 ;
        RECT 5.445 17.755 5.615 18.455 ;
        RECT 7.395 18.385 7.565 19.640 ;
        RECT 8.235 18.555 8.675 19.715 ;
        RECT 5.785 17.955 6.125 18.285 ;
        RECT 5.445 17.585 5.785 17.755 ;
        RECT 5.615 17.375 5.785 17.585 ;
        RECT 5.955 17.715 6.125 17.955 ;
        RECT 6.325 17.915 6.715 18.285 ;
        RECT 6.895 17.715 7.225 18.285 ;
        RECT 7.395 18.055 7.795 18.385 ;
        RECT 7.965 18.035 8.335 18.365 ;
        RECT 7.965 17.885 8.135 18.035 ;
        RECT 5.955 17.545 7.225 17.715 ;
        RECT 7.395 17.715 8.135 17.885 ;
        RECT 8.505 17.865 8.675 18.555 ;
        RECT 8.885 18.035 9.575 18.515 ;
        RECT 7.395 17.375 7.565 17.715 ;
        RECT 5.615 17.125 7.565 17.375 ;
        RECT 8.305 17.085 8.675 17.865 ;
        RECT 9.745 17.085 10.075 19.715 ;
        RECT 11.350 19.640 13.325 19.810 ;
        RECT 10.315 18.965 10.645 19.435 ;
        RECT 11.350 18.965 11.520 19.640 ;
        RECT 10.315 18.795 11.520 18.965 ;
        RECT 10.315 18.685 10.645 18.795 ;
        RECT 10.315 17.865 10.485 18.685 ;
        RECT 12.265 18.625 12.595 19.470 ;
        RECT 10.705 18.085 11.035 18.515 ;
        RECT 11.205 18.455 12.595 18.625 ;
        RECT 10.315 17.275 10.645 17.865 ;
        RECT 11.205 17.755 11.375 18.455 ;
        RECT 13.155 18.385 13.325 19.640 ;
        RECT 13.995 18.555 14.435 19.715 ;
        RECT 12.085 17.915 12.475 18.285 ;
        RECT 13.155 18.055 13.555 18.385 ;
        RECT 13.725 18.035 14.095 18.365 ;
        RECT 13.725 17.885 13.895 18.035 ;
        RECT 11.205 17.585 11.545 17.755 ;
        RECT 11.375 17.375 11.545 17.585 ;
        RECT 13.155 17.715 13.895 17.885 ;
        RECT 14.265 17.865 14.435 18.555 ;
        RECT 13.155 17.375 13.325 17.715 ;
        RECT 11.375 17.125 13.325 17.375 ;
        RECT 14.065 17.085 14.435 17.865 ;
        RECT 15.085 18.765 15.445 19.715 ;
        RECT 17.320 19.640 18.380 19.810 ;
        RECT 15.085 17.865 15.255 18.765 ;
        RECT 16.150 18.595 16.400 19.435 ;
        RECT 16.780 18.595 17.110 18.975 ;
        RECT 17.320 18.785 17.650 19.640 ;
        RECT 18.210 19.530 18.380 19.640 ;
        RECT 19.700 19.530 21.080 19.700 ;
        RECT 21.815 19.530 22.145 19.715 ;
        RECT 17.870 18.615 18.040 19.470 ;
        RECT 15.425 18.425 17.110 18.595 ;
        RECT 15.425 18.085 15.785 18.425 ;
        RECT 16.780 18.305 17.110 18.425 ;
        RECT 17.340 18.445 18.040 18.615 ;
        RECT 18.210 19.360 19.870 19.530 ;
        RECT 20.910 19.360 22.145 19.530 ;
        RECT 15.085 17.085 15.445 17.865 ;
        RECT 15.615 17.755 15.785 18.085 ;
        RECT 15.955 18.135 16.285 18.255 ;
        RECT 17.340 18.135 17.510 18.445 ;
        RECT 18.210 18.275 18.380 19.360 ;
        RECT 20.040 19.190 20.400 19.360 ;
        RECT 15.955 17.965 17.510 18.135 ;
        RECT 15.955 17.925 16.285 17.965 ;
        RECT 15.615 17.585 16.370 17.755 ;
        RECT 16.120 17.085 16.370 17.585 ;
        RECT 17.340 17.715 17.510 17.965 ;
        RECT 17.680 18.105 18.380 18.275 ;
        RECT 18.550 18.860 18.825 19.190 ;
        RECT 19.020 19.020 20.400 19.190 ;
        RECT 17.680 17.885 17.990 18.105 ;
        RECT 18.550 17.935 18.720 18.860 ;
        RECT 19.020 18.690 19.190 19.020 ;
        RECT 18.890 18.360 19.190 18.690 ;
        RECT 19.400 18.485 20.060 18.815 ;
        RECT 18.900 17.935 19.230 18.150 ;
        RECT 18.160 17.765 19.230 17.935 ;
        RECT 17.340 17.465 17.940 17.715 ;
        RECT 18.160 17.330 18.330 17.765 ;
        RECT 19.400 17.595 19.570 18.485 ;
        RECT 20.230 18.315 20.400 19.020 ;
        RECT 18.500 17.425 19.570 17.595 ;
        RECT 17.265 17.160 17.595 17.245 ;
        RECT 18.500 17.160 18.670 17.425 ;
        RECT 17.265 16.990 18.670 17.160 ;
        RECT 19.400 17.180 19.570 17.425 ;
        RECT 19.740 18.145 20.400 18.315 ;
        RECT 19.740 17.350 20.005 18.145 ;
        RECT 20.570 17.975 20.740 19.360 ;
        RECT 20.185 17.805 20.740 17.975 ;
        RECT 20.910 18.760 21.290 19.090 ;
        RECT 20.910 17.860 21.190 18.760 ;
        RECT 21.685 18.555 22.145 19.360 ;
        RECT 22.715 18.855 23.045 19.715 ;
        RECT 23.725 19.255 24.055 19.715 ;
        RECT 23.850 19.215 24.055 19.255 ;
        RECT 26.225 19.215 26.555 19.490 ;
        RECT 23.850 19.045 26.555 19.215 ;
        RECT 26.755 19.320 27.005 19.490 ;
        RECT 28.150 19.320 28.485 19.415 ;
        RECT 26.755 19.150 28.485 19.320 ;
        RECT 22.315 18.685 23.045 18.855 ;
        RECT 21.685 18.415 21.855 18.555 ;
        RECT 21.400 18.085 21.855 18.415 ;
        RECT 22.315 18.285 22.485 18.685 ;
        RECT 20.505 17.465 21.515 17.635 ;
        RECT 20.505 17.180 20.675 17.465 ;
        RECT 19.400 17.010 20.675 17.180 ;
        RECT 21.345 17.160 21.515 17.465 ;
        RECT 21.685 17.330 21.855 18.085 ;
        RECT 22.025 17.865 22.485 18.285 ;
        RECT 22.655 18.035 23.035 18.515 ;
        RECT 22.025 17.695 23.045 17.865 ;
        RECT 23.285 17.735 23.680 18.930 ;
        RECT 22.025 17.160 22.195 17.695 ;
        RECT 21.345 16.990 22.195 17.160 ;
        RECT 22.795 17.085 23.045 17.695 ;
        RECT 23.850 17.565 24.020 19.045 ;
        RECT 26.225 18.980 26.555 19.045 ;
        RECT 24.190 17.865 24.460 18.875 ;
        RECT 24.630 18.545 24.985 18.875 ;
        RECT 25.635 18.640 25.965 18.875 ;
        RECT 26.225 18.810 27.000 18.980 ;
        RECT 24.630 17.875 24.800 18.545 ;
        RECT 25.205 18.375 25.435 18.515 ;
        RECT 25.635 18.470 26.660 18.640 ;
        RECT 24.970 18.045 25.435 18.375 ;
        RECT 26.105 18.310 26.660 18.470 ;
        RECT 25.605 17.875 25.935 18.285 ;
        RECT 23.330 17.395 24.020 17.565 ;
        RECT 24.630 17.705 25.935 17.875 ;
        RECT 23.330 17.105 23.660 17.395 ;
        RECT 24.630 17.085 25.080 17.705 ;
        RECT 26.105 17.535 26.275 18.310 ;
        RECT 26.830 18.105 27.000 18.810 ;
        RECT 25.750 17.160 26.275 17.535 ;
        RECT 26.445 17.935 27.000 18.105 ;
        RECT 26.445 17.330 26.695 17.935 ;
        RECT 27.170 17.765 27.340 19.150 ;
        RECT 28.050 19.085 28.485 19.150 ;
        RECT 26.865 17.330 27.340 17.765 ;
        RECT 27.510 17.825 27.790 18.890 ;
        RECT 28.050 18.350 28.220 19.085 ;
        RECT 28.390 18.560 28.770 18.890 ;
        RECT 28.050 18.180 28.720 18.350 ;
        RECT 29.390 18.305 29.640 19.490 ;
        RECT 29.860 19.100 30.825 19.430 ;
        RECT 28.390 18.020 28.720 18.180 ;
        RECT 28.905 18.135 29.640 18.305 ;
        RECT 29.810 18.600 30.485 18.930 ;
        RECT 28.905 17.825 29.075 18.135 ;
        RECT 29.810 17.965 29.980 18.600 ;
        RECT 30.655 18.330 30.825 19.100 ;
        RECT 31.420 19.070 31.800 19.465 ;
        RECT 30.995 18.570 31.460 18.900 ;
        RECT 31.630 18.670 31.800 19.070 ;
        RECT 31.630 18.500 32.130 18.670 ;
        RECT 32.420 18.545 33.110 19.720 ;
        RECT 27.510 17.655 29.075 17.825 ;
        RECT 29.245 17.635 29.980 17.965 ;
        RECT 30.150 18.160 31.790 18.330 ;
        RECT 29.245 17.485 29.415 17.635 ;
        RECT 27.510 17.315 29.415 17.485 ;
        RECT 30.150 17.465 30.320 18.160 ;
        RECT 31.490 18.000 31.790 18.160 ;
        RECT 30.590 17.805 30.920 17.965 ;
        RECT 31.960 17.805 32.130 18.500 ;
        RECT 30.590 17.635 32.130 17.805 ;
        RECT 27.510 17.160 27.680 17.315 ;
        RECT 25.750 16.990 27.680 17.160 ;
        RECT 29.585 17.135 30.320 17.465 ;
        RECT 31.645 17.085 32.130 17.635 ;
        RECT 32.720 17.085 33.110 18.545 ;
        RECT 33.350 18.365 33.600 19.710 ;
        RECT 34.235 18.555 34.595 19.715 ;
        RECT 33.350 18.035 34.255 18.365 ;
        RECT 33.350 17.085 33.600 18.035 ;
        RECT 34.425 17.865 34.595 18.555 ;
        RECT 34.225 17.085 34.595 17.865 ;
        RECT 35.245 18.555 35.635 19.715 ;
        RECT 35.805 19.195 36.135 19.715 ;
        RECT 36.915 19.195 37.245 19.715 ;
        RECT 35.805 19.025 37.245 19.195 ;
        RECT 37.475 18.855 38.055 19.715 ;
        RECT 35.805 18.685 38.055 18.855 ;
        RECT 35.245 17.885 35.415 18.555 ;
        RECT 35.805 18.385 35.975 18.685 ;
        RECT 35.585 18.055 35.975 18.385 ;
        RECT 36.155 18.430 36.485 18.515 ;
        RECT 36.155 18.100 37.715 18.430 ;
        RECT 36.155 18.085 36.485 18.100 ;
        RECT 35.245 17.715 36.475 17.885 ;
        RECT 37.885 17.775 38.055 18.685 ;
        RECT 39.115 18.665 39.445 19.715 ;
        RECT 40.300 18.725 40.630 19.595 ;
        RECT 39.115 18.495 39.830 18.665 ;
        RECT 40.300 18.555 40.865 18.725 ;
        RECT 41.755 18.555 42.275 19.715 ;
        RECT 44.445 19.640 45.615 19.810 ;
        RECT 44.445 19.530 44.615 19.640 ;
        RECT 43.520 19.360 44.615 19.530 ;
        RECT 43.520 18.685 43.850 19.360 ;
        RECT 44.325 19.020 44.810 19.190 ;
        RECT 39.660 18.365 39.830 18.495 ;
        RECT 38.225 17.915 38.895 18.350 ;
        RECT 39.125 17.915 39.455 18.285 ;
        RECT 39.660 18.035 40.525 18.365 ;
        RECT 36.030 17.150 36.475 17.715 ;
        RECT 37.360 17.445 38.055 17.775 ;
        RECT 39.660 17.745 39.830 18.035 ;
        RECT 39.115 17.415 39.830 17.745 ;
        RECT 40.695 17.915 40.865 18.555 ;
        RECT 41.535 18.035 41.935 18.365 ;
        RECT 42.105 18.305 42.275 18.555 ;
        RECT 42.105 18.135 43.355 18.305 ;
        RECT 41.535 17.915 41.705 18.035 ;
        RECT 40.695 17.745 41.705 17.915 ;
        RECT 42.105 17.865 42.275 18.135 ;
        RECT 40.695 17.275 41.045 17.745 ;
        RECT 41.875 17.085 42.275 17.865 ;
        RECT 42.965 17.545 43.355 18.135 ;
        RECT 43.525 17.375 43.695 18.685 ;
        RECT 43.865 18.185 44.155 18.515 ;
        RECT 44.325 17.920 44.495 19.020 ;
        RECT 45.025 18.850 45.275 19.470 ;
        RECT 45.445 19.190 45.615 19.640 ;
        RECT 46.205 19.640 47.300 19.810 ;
        RECT 46.205 19.190 46.375 19.640 ;
        RECT 47.130 19.550 47.300 19.640 ;
        RECT 45.445 19.020 46.375 19.190 ;
        RECT 46.630 18.850 46.960 19.470 ;
        RECT 47.130 19.220 47.800 19.550 ;
        RECT 48.265 19.330 48.625 19.715 ;
        RECT 50.155 19.640 51.060 19.810 ;
        RECT 50.155 19.330 50.345 19.640 ;
        RECT 47.130 19.145 47.315 19.220 ;
        RECT 44.665 18.680 46.960 18.850 ;
        RECT 44.665 18.205 44.995 18.680 ;
        RECT 45.225 18.180 45.595 18.510 ;
        RECT 45.765 18.290 46.095 18.510 ;
        RECT 46.725 18.345 46.960 18.680 ;
        RECT 45.765 17.920 45.935 18.290 ;
        RECT 44.325 17.750 45.935 17.920 ;
        RECT 46.185 17.840 46.555 18.120 ;
        RECT 46.725 18.010 46.975 18.345 ;
        RECT 47.145 17.840 47.315 19.145 ;
        RECT 48.265 19.160 50.345 19.330 ;
        RECT 48.265 18.975 48.625 19.160 ;
        RECT 47.485 18.645 48.625 18.975 ;
        RECT 49.545 18.905 49.875 18.990 ;
        RECT 47.935 18.575 48.625 18.645 ;
        RECT 48.935 18.575 50.345 18.905 ;
        RECT 43.165 17.125 43.695 17.375 ;
        RECT 44.485 17.085 44.815 17.750 ;
        RECT 45.545 17.160 45.715 17.750 ;
        RECT 46.185 17.670 47.315 17.840 ;
        RECT 47.485 17.500 47.735 18.335 ;
        RECT 47.935 17.735 48.265 18.575 ;
        RECT 48.935 18.405 49.105 18.575 ;
        RECT 48.435 18.075 49.375 18.405 ;
        RECT 49.205 17.700 49.375 18.075 ;
        RECT 49.545 17.915 49.885 18.405 ;
        RECT 50.550 18.260 50.720 19.470 ;
        RECT 50.055 18.090 50.720 18.260 ;
        RECT 50.890 18.340 51.060 19.640 ;
        RECT 51.230 18.830 51.480 19.120 ;
        RECT 52.670 18.855 53.000 19.120 ;
        RECT 51.230 18.660 51.735 18.830 ;
        RECT 45.885 17.330 47.735 17.500 ;
        RECT 47.905 17.395 49.035 17.565 ;
        RECT 47.905 17.160 48.075 17.395 ;
        RECT 45.545 16.990 48.075 17.160 ;
        RECT 48.865 17.160 49.035 17.395 ;
        RECT 49.205 17.370 49.800 17.700 ;
        RECT 50.055 17.160 50.225 18.090 ;
        RECT 50.890 18.010 51.395 18.340 ;
        RECT 51.565 18.000 51.735 18.660 ;
        RECT 51.905 18.685 53.515 18.855 ;
        RECT 51.905 18.190 52.170 18.685 ;
        RECT 52.380 18.185 52.795 18.515 ;
        RECT 50.395 17.500 50.565 17.920 ;
        RECT 51.565 17.840 53.175 18.000 ;
        RECT 50.745 17.670 53.175 17.840 ;
        RECT 53.345 17.500 53.515 18.685 ;
        RECT 53.735 18.275 53.905 19.635 ;
        RECT 54.735 18.475 55.145 19.515 ;
        RECT 54.975 18.365 55.145 18.475 ;
        RECT 56.875 18.555 57.205 19.715 ;
        RECT 53.735 18.145 54.565 18.275 ;
        RECT 53.735 18.055 54.715 18.145 ;
        RECT 50.395 17.330 52.075 17.500 ;
        RECT 48.865 16.990 51.620 17.160 ;
        RECT 51.825 17.085 52.075 17.330 ;
        RECT 53.045 17.085 53.515 17.500 ;
        RECT 54.035 17.505 54.715 18.055 ;
        RECT 54.975 18.035 55.805 18.365 ;
        RECT 54.035 17.085 54.295 17.505 ;
        RECT 54.975 17.085 55.270 18.035 ;
        RECT 56.875 17.785 57.045 18.555 ;
        RECT 57.910 18.285 58.080 19.610 ;
        RECT 57.220 17.955 58.080 18.285 ;
        RECT 56.875 17.085 57.205 17.785 ;
        RECT 57.885 17.675 58.080 17.955 ;
        RECT 58.325 17.915 58.640 19.715 ;
        RECT 59.430 19.295 59.760 19.715 ;
        RECT 58.445 17.865 58.640 17.915 ;
        RECT 59.025 19.125 59.760 19.295 ;
        RECT 59.990 19.215 60.320 19.715 ;
        RECT 63.220 19.640 64.150 19.810 ;
        RECT 61.310 19.385 62.000 19.640 ;
        RECT 60.860 19.215 62.000 19.385 ;
        RECT 57.885 17.085 58.215 17.675 ;
        RECT 58.445 17.085 58.775 17.865 ;
        RECT 59.025 17.745 59.195 19.125 ;
        RECT 59.990 18.955 61.030 19.215 ;
        RECT 59.365 18.785 61.030 18.955 ;
        RECT 59.365 17.945 59.695 18.785 ;
        RECT 61.200 18.755 61.530 19.045 ;
        RECT 60.090 17.915 60.475 18.515 ;
        RECT 60.660 17.745 60.990 18.615 ;
        RECT 59.025 17.575 60.990 17.745 ;
        RECT 59.505 17.150 59.835 17.575 ;
        RECT 61.200 17.160 61.370 18.755 ;
        RECT 61.750 18.695 62.000 19.215 ;
        RECT 63.220 19.030 63.390 19.640 ;
        RECT 62.725 18.860 63.390 19.030 ;
        RECT 61.750 18.585 61.920 18.695 ;
        RECT 61.540 18.415 61.920 18.585 ;
        RECT 62.725 18.525 62.895 18.860 ;
        RECT 63.560 18.730 63.810 19.470 ;
        RECT 63.980 19.070 64.150 19.640 ;
        RECT 64.885 19.640 66.655 19.810 ;
        RECT 64.885 19.070 65.055 19.640 ;
        RECT 63.980 18.900 65.055 19.070 ;
        RECT 61.540 17.660 61.710 18.415 ;
        RECT 62.155 18.355 62.895 18.525 ;
        RECT 62.155 18.185 62.325 18.355 ;
        RECT 63.065 18.285 63.355 18.690 ;
        RECT 63.560 18.510 64.530 18.730 ;
        RECT 61.880 17.855 62.325 18.185 ;
        RECT 62.495 18.025 62.825 18.185 ;
        RECT 63.525 18.170 64.645 18.340 ;
        RECT 63.525 18.025 63.810 18.170 ;
        RECT 62.495 17.855 63.810 18.025 ;
        RECT 61.540 17.330 61.985 17.660 ;
        RECT 62.155 17.160 62.325 17.855 ;
        RECT 63.525 17.790 63.810 17.855 ;
        RECT 63.985 17.620 64.305 18.000 ;
        RECT 64.475 17.790 64.645 18.170 ;
        RECT 64.815 18.095 65.055 18.900 ;
        RECT 65.225 19.030 65.585 19.470 ;
        RECT 65.755 19.030 66.235 19.470 ;
        RECT 66.405 19.135 66.655 19.640 ;
        RECT 68.395 19.095 68.645 19.715 ;
        RECT 93.810 19.680 94.130 19.975 ;
        RECT 93.810 19.350 94.620 19.680 ;
        RECT 65.225 17.790 65.395 19.030 ;
        RECT 66.065 18.965 66.235 19.030 ;
        RECT 66.965 18.965 68.645 19.095 ;
        RECT 66.065 18.925 68.645 18.965 ;
        RECT 64.475 17.620 65.395 17.790 ;
        RECT 63.580 17.170 64.155 17.620 ;
        RECT 61.200 16.990 62.325 17.160 ;
        RECT 65.145 17.120 65.395 17.620 ;
        RECT 65.565 18.170 65.895 18.840 ;
        RECT 66.065 18.795 67.135 18.925 ;
        RECT 65.565 17.160 65.735 18.170 ;
        RECT 66.065 17.580 66.235 18.795 ;
        RECT 67.305 18.625 67.785 18.755 ;
        RECT 66.405 18.455 67.785 18.625 ;
        RECT 66.405 18.035 66.735 18.455 ;
        RECT 65.905 17.330 66.235 17.580 ;
        RECT 66.465 17.160 66.715 17.865 ;
        RECT 67.615 17.745 67.785 18.455 ;
        RECT 65.565 16.990 66.715 17.160 ;
        RECT 67.325 17.085 67.785 17.745 ;
        RECT 68.475 17.575 68.645 18.925 ;
        RECT 68.395 17.115 68.645 17.575 ;
        RECT 73.515 17.935 73.695 18.855 ;
        RECT 73.515 17.550 73.725 17.935 ;
        RECT 73.995 17.610 74.175 18.760 ;
        RECT 75.910 17.610 76.090 18.760 ;
        RECT 76.785 17.625 76.970 17.895 ;
        RECT 73.515 17.050 73.695 17.550 ;
        RECT 73.995 17.440 76.090 17.610 ;
        RECT 76.765 17.495 76.970 17.625 ;
        RECT 76.765 17.270 76.935 17.495 ;
        RECT 75.700 17.100 76.935 17.270 ;
        RECT 85.185 17.330 85.360 19.065 ;
        RECT 85.610 18.925 86.630 19.095 ;
        RECT 85.610 17.580 85.785 18.925 ;
        RECT 86.030 17.330 86.205 18.755 ;
        RECT 86.450 18.560 86.625 18.925 ;
        RECT 91.345 18.910 92.365 19.080 ;
        RECT 96.610 18.975 107.015 19.145 ;
        RECT 108.835 18.975 119.240 19.145 ;
        RECT 121.100 18.975 131.505 19.145 ;
        RECT 133.350 18.975 143.755 19.145 ;
        RECT 86.450 17.745 87.110 18.560 ;
        RECT 88.325 17.820 88.555 18.570 ;
        RECT 91.345 18.560 91.520 18.910 ;
        RECT 89.435 17.830 89.645 18.505 ;
        RECT 90.865 17.745 91.520 18.560 ;
        RECT 85.185 17.160 86.230 17.330 ;
        RECT 86.450 17.295 86.625 17.745 ;
        RECT 91.345 17.655 91.520 17.745 ;
        RECT 92.190 17.500 92.365 18.910 ;
        RECT 101.680 18.445 101.950 18.975 ;
        RECT 113.905 18.445 114.175 18.975 ;
        RECT 126.170 18.445 126.440 18.975 ;
        RECT 138.420 18.445 138.690 18.975 ;
        RECT 96.610 18.275 107.015 18.445 ;
        RECT 108.835 18.275 119.240 18.445 ;
        RECT 121.100 18.275 131.505 18.445 ;
        RECT 133.350 18.275 143.755 18.445 ;
        RECT 101.680 17.745 101.950 18.275 ;
        RECT 113.905 17.745 114.175 18.275 ;
        RECT 126.170 17.745 126.440 18.275 ;
        RECT 138.420 17.745 138.690 18.275 ;
        RECT 96.610 17.575 107.015 17.745 ;
        RECT 108.835 17.575 119.240 17.745 ;
        RECT 121.100 17.575 131.505 17.745 ;
        RECT 133.350 17.575 143.755 17.745 ;
        RECT 75.700 17.050 75.880 17.100 ;
        RECT 73.515 16.880 75.880 17.050 ;
        RECT 75.225 16.555 75.395 16.710 ;
        RECT 72.685 16.220 75.395 16.555 ;
        RECT 2.645 13.760 3.335 14.240 ;
        RECT 3.505 12.810 3.835 15.440 ;
        RECT 4.255 14.580 4.585 15.160 ;
        RECT 4.255 14.410 5.745 14.580 ;
        RECT 4.255 14.280 4.585 14.410 ;
        RECT 4.065 13.640 4.735 14.010 ;
        RECT 5.005 13.810 5.335 14.240 ;
        RECT 5.575 14.090 5.745 14.410 ;
        RECT 5.915 14.280 6.270 15.440 ;
        RECT 5.575 13.760 5.930 14.090 ;
        RECT 5.575 13.640 5.745 13.760 ;
        RECT 4.905 13.470 5.745 13.640 ;
        RECT 6.100 13.590 6.270 14.280 ;
        RECT 7.305 14.580 7.885 15.440 ;
        RECT 8.115 14.920 8.445 15.440 ;
        RECT 9.225 14.920 9.555 15.440 ;
        RECT 8.115 14.750 9.555 14.920 ;
        RECT 7.305 14.410 9.555 14.580 ;
        RECT 6.465 13.640 7.135 14.075 ;
        RECT 4.905 13.000 5.200 13.470 ;
        RECT 5.915 12.810 6.270 13.590 ;
        RECT 7.305 13.500 7.475 14.410 ;
        RECT 8.875 14.155 9.205 14.240 ;
        RECT 7.645 13.825 9.205 14.155 ;
        RECT 8.875 13.810 9.205 13.825 ;
        RECT 9.385 14.110 9.555 14.410 ;
        RECT 9.725 14.280 10.115 15.440 ;
        RECT 11.350 15.365 13.325 15.535 ;
        RECT 9.385 13.780 9.775 14.110 ;
        RECT 9.945 13.610 10.115 14.280 ;
        RECT 7.305 13.170 8.000 13.500 ;
        RECT 8.885 13.440 10.115 13.610 ;
        RECT 10.315 14.690 10.645 15.160 ;
        RECT 11.350 14.690 11.520 15.365 ;
        RECT 10.315 14.520 11.520 14.690 ;
        RECT 10.315 14.410 10.645 14.520 ;
        RECT 10.315 13.590 10.485 14.410 ;
        RECT 12.265 14.350 12.595 15.195 ;
        RECT 10.705 13.810 11.035 14.240 ;
        RECT 11.205 14.180 12.595 14.350 ;
        RECT 8.885 12.875 9.330 13.440 ;
        RECT 10.315 13.000 10.645 13.590 ;
        RECT 11.205 13.480 11.375 14.180 ;
        RECT 13.155 14.110 13.325 15.365 ;
        RECT 13.995 14.280 14.435 15.440 ;
        RECT 12.085 13.640 12.475 14.010 ;
        RECT 13.155 13.780 13.555 14.110 ;
        RECT 13.725 13.760 14.095 14.090 ;
        RECT 13.725 13.610 13.895 13.760 ;
        RECT 11.205 13.310 11.545 13.480 ;
        RECT 11.375 13.100 11.545 13.310 ;
        RECT 13.155 13.440 13.895 13.610 ;
        RECT 14.265 13.590 14.435 14.280 ;
        RECT 13.155 13.100 13.325 13.440 ;
        RECT 11.375 12.850 13.325 13.100 ;
        RECT 14.065 12.810 14.435 13.590 ;
        RECT 15.085 14.490 15.445 15.440 ;
        RECT 17.320 15.365 18.380 15.535 ;
        RECT 15.085 13.590 15.255 14.490 ;
        RECT 16.150 14.320 16.400 15.160 ;
        RECT 16.780 14.320 17.110 14.700 ;
        RECT 17.320 14.510 17.650 15.365 ;
        RECT 18.210 15.255 18.380 15.365 ;
        RECT 19.700 15.255 21.080 15.425 ;
        RECT 21.815 15.255 22.145 15.440 ;
        RECT 17.870 14.340 18.040 15.195 ;
        RECT 15.425 14.150 17.110 14.320 ;
        RECT 15.425 13.810 15.785 14.150 ;
        RECT 16.780 14.030 17.110 14.150 ;
        RECT 17.340 14.170 18.040 14.340 ;
        RECT 18.210 15.085 19.870 15.255 ;
        RECT 20.910 15.085 22.145 15.255 ;
        RECT 15.085 12.810 15.445 13.590 ;
        RECT 15.615 13.480 15.785 13.810 ;
        RECT 15.955 13.860 16.285 13.980 ;
        RECT 17.340 13.860 17.510 14.170 ;
        RECT 18.210 14.000 18.380 15.085 ;
        RECT 20.040 14.915 20.400 15.085 ;
        RECT 15.955 13.690 17.510 13.860 ;
        RECT 15.955 13.650 16.285 13.690 ;
        RECT 15.615 13.310 16.370 13.480 ;
        RECT 16.120 12.810 16.370 13.310 ;
        RECT 17.340 13.440 17.510 13.690 ;
        RECT 17.680 13.830 18.380 14.000 ;
        RECT 18.550 14.585 18.825 14.915 ;
        RECT 19.020 14.745 20.400 14.915 ;
        RECT 17.680 13.610 17.990 13.830 ;
        RECT 18.550 13.660 18.720 14.585 ;
        RECT 19.020 14.415 19.190 14.745 ;
        RECT 18.890 14.085 19.190 14.415 ;
        RECT 19.400 14.210 20.060 14.540 ;
        RECT 18.900 13.660 19.230 13.875 ;
        RECT 18.160 13.490 19.230 13.660 ;
        RECT 17.340 13.190 17.940 13.440 ;
        RECT 18.160 13.055 18.330 13.490 ;
        RECT 19.400 13.320 19.570 14.210 ;
        RECT 20.230 14.040 20.400 14.745 ;
        RECT 18.500 13.150 19.570 13.320 ;
        RECT 17.265 12.885 17.595 12.970 ;
        RECT 18.500 12.885 18.670 13.150 ;
        RECT 17.265 12.715 18.670 12.885 ;
        RECT 19.400 12.905 19.570 13.150 ;
        RECT 19.740 13.870 20.400 14.040 ;
        RECT 19.740 13.075 20.005 13.870 ;
        RECT 20.570 13.700 20.740 15.085 ;
        RECT 20.185 13.530 20.740 13.700 ;
        RECT 20.910 14.485 21.290 14.815 ;
        RECT 20.910 13.585 21.190 14.485 ;
        RECT 21.685 14.280 22.145 15.085 ;
        RECT 22.715 14.580 23.045 15.440 ;
        RECT 23.725 14.980 24.055 15.440 ;
        RECT 23.850 14.940 24.055 14.980 ;
        RECT 26.225 14.940 26.555 15.215 ;
        RECT 23.850 14.770 26.555 14.940 ;
        RECT 26.755 15.045 27.005 15.215 ;
        RECT 28.150 15.045 28.485 15.140 ;
        RECT 26.755 14.875 28.485 15.045 ;
        RECT 22.315 14.410 23.045 14.580 ;
        RECT 21.685 14.140 21.855 14.280 ;
        RECT 21.400 13.810 21.855 14.140 ;
        RECT 22.315 14.010 22.485 14.410 ;
        RECT 20.505 13.190 21.515 13.360 ;
        RECT 20.505 12.905 20.675 13.190 ;
        RECT 19.400 12.735 20.675 12.905 ;
        RECT 21.345 12.885 21.515 13.190 ;
        RECT 21.685 13.055 21.855 13.810 ;
        RECT 22.025 13.590 22.485 14.010 ;
        RECT 22.655 13.760 23.035 14.240 ;
        RECT 22.025 13.420 23.045 13.590 ;
        RECT 23.285 13.460 23.680 14.655 ;
        RECT 22.025 12.885 22.195 13.420 ;
        RECT 21.345 12.715 22.195 12.885 ;
        RECT 22.795 12.810 23.045 13.420 ;
        RECT 23.850 13.290 24.020 14.770 ;
        RECT 26.225 14.705 26.555 14.770 ;
        RECT 24.190 13.590 24.460 14.600 ;
        RECT 24.630 14.270 24.985 14.600 ;
        RECT 25.635 14.365 25.965 14.600 ;
        RECT 26.225 14.535 27.000 14.705 ;
        RECT 24.630 13.600 24.800 14.270 ;
        RECT 25.205 14.100 25.435 14.240 ;
        RECT 25.635 14.195 26.660 14.365 ;
        RECT 24.970 13.770 25.435 14.100 ;
        RECT 26.105 14.035 26.660 14.195 ;
        RECT 25.605 13.600 25.935 14.010 ;
        RECT 23.330 13.120 24.020 13.290 ;
        RECT 24.630 13.430 25.935 13.600 ;
        RECT 23.330 12.830 23.660 13.120 ;
        RECT 24.630 12.810 25.080 13.430 ;
        RECT 26.105 13.260 26.275 14.035 ;
        RECT 26.830 13.830 27.000 14.535 ;
        RECT 25.750 12.885 26.275 13.260 ;
        RECT 26.445 13.660 27.000 13.830 ;
        RECT 26.445 13.055 26.695 13.660 ;
        RECT 27.170 13.490 27.340 14.875 ;
        RECT 28.050 14.810 28.485 14.875 ;
        RECT 26.865 13.055 27.340 13.490 ;
        RECT 27.510 13.550 27.790 14.615 ;
        RECT 28.050 14.075 28.220 14.810 ;
        RECT 28.390 14.285 28.770 14.615 ;
        RECT 28.050 13.905 28.720 14.075 ;
        RECT 29.390 14.030 29.640 15.215 ;
        RECT 29.860 14.825 30.825 15.155 ;
        RECT 28.390 13.745 28.720 13.905 ;
        RECT 28.905 13.860 29.640 14.030 ;
        RECT 29.810 14.325 30.485 14.655 ;
        RECT 28.905 13.550 29.075 13.860 ;
        RECT 29.810 13.690 29.980 14.325 ;
        RECT 30.655 14.055 30.825 14.825 ;
        RECT 31.420 14.795 31.800 15.190 ;
        RECT 30.995 14.295 31.460 14.625 ;
        RECT 31.630 14.395 31.800 14.795 ;
        RECT 31.630 14.225 32.130 14.395 ;
        RECT 32.420 14.270 33.110 15.445 ;
        RECT 27.510 13.380 29.075 13.550 ;
        RECT 29.245 13.360 29.980 13.690 ;
        RECT 30.150 13.885 31.790 14.055 ;
        RECT 29.245 13.210 29.415 13.360 ;
        RECT 27.510 13.040 29.415 13.210 ;
        RECT 30.150 13.190 30.320 13.885 ;
        RECT 31.490 13.725 31.790 13.885 ;
        RECT 30.590 13.530 30.920 13.690 ;
        RECT 31.960 13.530 32.130 14.225 ;
        RECT 30.590 13.360 32.130 13.530 ;
        RECT 27.510 12.885 27.680 13.040 ;
        RECT 25.750 12.715 27.680 12.885 ;
        RECT 29.585 12.860 30.320 13.190 ;
        RECT 31.645 12.810 32.130 13.360 ;
        RECT 32.720 12.810 33.110 14.270 ;
        RECT 33.350 14.090 33.600 15.435 ;
        RECT 34.235 14.280 34.595 15.440 ;
        RECT 33.350 13.760 34.255 14.090 ;
        RECT 33.350 12.810 33.600 13.760 ;
        RECT 34.425 13.590 34.595 14.280 ;
        RECT 34.225 12.810 34.595 13.590 ;
        RECT 35.245 14.310 35.640 15.440 ;
        RECT 36.375 14.480 36.705 15.460 ;
        RECT 35.810 14.310 37.300 14.480 ;
        RECT 35.245 13.640 35.415 14.310 ;
        RECT 35.810 14.140 35.980 14.310 ;
        RECT 35.585 13.810 35.980 14.140 ;
        RECT 36.155 13.640 36.485 14.140 ;
        RECT 35.245 12.930 35.720 13.640 ;
        RECT 36.970 13.300 37.300 14.310 ;
        RECT 37.645 14.280 38.035 15.440 ;
        RECT 38.205 14.920 38.535 15.440 ;
        RECT 39.315 14.920 39.645 15.440 ;
        RECT 38.205 14.750 39.645 14.920 ;
        RECT 39.875 14.580 40.455 15.440 ;
        RECT 38.205 14.410 40.455 14.580 ;
        RECT 41.515 14.580 41.845 15.160 ;
        RECT 42.485 14.920 42.965 15.440 ;
        RECT 44.365 14.980 44.695 15.440 ;
        RECT 44.490 14.940 44.695 14.980 ;
        RECT 46.865 14.940 47.195 15.215 ;
        RECT 42.485 14.750 43.655 14.920 ;
        RECT 41.515 14.410 43.085 14.580 ;
        RECT 37.645 13.610 37.815 14.280 ;
        RECT 38.205 14.110 38.375 14.410 ;
        RECT 37.985 13.780 38.375 14.110 ;
        RECT 38.555 14.155 38.885 14.240 ;
        RECT 38.555 13.825 40.115 14.155 ;
        RECT 38.555 13.810 38.885 13.825 ;
        RECT 37.645 13.440 38.875 13.610 ;
        RECT 40.285 13.500 40.455 14.410 ;
        RECT 40.625 13.640 41.295 14.075 ;
        RECT 41.505 13.760 42.235 14.240 ;
        RECT 42.415 13.810 42.745 14.240 ;
        RECT 42.915 14.090 43.085 14.410 ;
        RECT 42.915 13.760 43.315 14.090 ;
        RECT 42.915 13.590 43.085 13.760 ;
        RECT 43.485 13.590 43.655 14.750 ;
        RECT 36.725 12.715 37.455 13.130 ;
        RECT 38.430 12.875 38.875 13.440 ;
        RECT 39.760 13.170 40.455 13.500 ;
        RECT 41.515 13.420 43.085 13.590 ;
        RECT 41.515 13.000 41.780 13.420 ;
        RECT 43.255 12.810 43.655 13.590 ;
        RECT 44.490 14.770 47.195 14.940 ;
        RECT 47.395 15.045 47.645 15.215 ;
        RECT 48.790 15.045 49.125 15.140 ;
        RECT 47.395 14.875 49.125 15.045 ;
        RECT 44.490 13.290 44.660 14.770 ;
        RECT 46.865 14.705 47.195 14.770 ;
        RECT 44.830 13.590 45.100 14.600 ;
        RECT 45.270 14.270 45.625 14.600 ;
        RECT 46.275 14.365 46.605 14.600 ;
        RECT 46.865 14.535 47.640 14.705 ;
        RECT 45.270 13.600 45.440 14.270 ;
        RECT 45.845 14.100 46.075 14.240 ;
        RECT 46.275 14.195 47.300 14.365 ;
        RECT 45.610 13.770 46.075 14.100 ;
        RECT 46.745 14.035 47.300 14.195 ;
        RECT 46.245 13.600 46.575 14.010 ;
        RECT 43.970 13.120 44.660 13.290 ;
        RECT 45.270 13.430 46.575 13.600 ;
        RECT 43.970 12.830 44.300 13.120 ;
        RECT 45.270 12.810 45.720 13.430 ;
        RECT 46.745 13.260 46.915 14.035 ;
        RECT 47.470 13.830 47.640 14.535 ;
        RECT 46.390 12.885 46.915 13.260 ;
        RECT 47.085 13.660 47.640 13.830 ;
        RECT 47.085 13.055 47.335 13.660 ;
        RECT 47.810 13.490 47.980 14.875 ;
        RECT 48.690 14.810 49.125 14.875 ;
        RECT 47.505 13.055 47.980 13.490 ;
        RECT 48.150 13.550 48.430 14.615 ;
        RECT 48.690 14.075 48.860 14.810 ;
        RECT 49.030 14.285 49.410 14.615 ;
        RECT 48.690 13.905 49.360 14.075 ;
        RECT 50.030 14.030 50.280 15.215 ;
        RECT 50.500 14.825 51.465 15.155 ;
        RECT 49.030 13.745 49.360 13.905 ;
        RECT 49.545 13.860 50.280 14.030 ;
        RECT 50.450 14.325 51.125 14.655 ;
        RECT 49.545 13.550 49.715 13.860 ;
        RECT 50.450 13.690 50.620 14.325 ;
        RECT 51.295 14.055 51.465 14.825 ;
        RECT 52.060 14.795 52.440 15.190 ;
        RECT 51.635 14.295 52.100 14.625 ;
        RECT 52.270 14.395 52.440 14.795 ;
        RECT 52.270 14.225 52.770 14.395 ;
        RECT 53.060 14.270 53.750 15.445 ;
        RECT 48.150 13.380 49.715 13.550 ;
        RECT 49.885 13.360 50.620 13.690 ;
        RECT 50.790 13.885 52.430 14.055 ;
        RECT 49.885 13.210 50.055 13.360 ;
        RECT 48.150 13.040 50.055 13.210 ;
        RECT 50.790 13.190 50.960 13.885 ;
        RECT 52.130 13.725 52.430 13.885 ;
        RECT 51.230 13.530 51.560 13.690 ;
        RECT 52.600 13.530 52.770 14.225 ;
        RECT 51.230 13.360 52.770 13.530 ;
        RECT 48.150 12.885 48.320 13.040 ;
        RECT 46.390 12.715 48.320 12.885 ;
        RECT 50.225 12.860 50.960 13.190 ;
        RECT 52.285 12.810 52.770 13.360 ;
        RECT 53.360 12.810 53.750 14.270 ;
        RECT 53.990 14.090 54.240 15.435 ;
        RECT 54.875 14.280 55.235 15.440 ;
        RECT 55.445 15.350 55.775 15.440 ;
        RECT 55.445 14.410 56.115 15.350 ;
        RECT 53.990 13.760 54.895 14.090 ;
        RECT 53.990 12.810 54.240 13.760 ;
        RECT 55.065 13.590 55.235 14.280 ;
        RECT 55.445 13.760 55.775 14.240 ;
        RECT 54.865 12.810 55.235 13.590 ;
        RECT 55.945 13.590 56.115 14.410 ;
        RECT 56.305 13.760 56.635 14.240 ;
        RECT 55.945 12.810 56.195 13.590 ;
        RECT 57.745 12.810 58.075 15.440 ;
        RECT 58.325 13.760 59.015 14.240 ;
        RECT 59.185 14.205 59.515 15.440 ;
        RECT 59.765 14.205 60.455 14.240 ;
        RECT 59.185 13.915 60.455 14.205 ;
        RECT 59.185 12.810 59.515 13.915 ;
        RECT 59.765 13.760 60.455 13.915 ;
        RECT 60.625 12.810 60.955 15.440 ;
        RECT 62.065 15.350 62.395 15.440 ;
        RECT 63.505 15.350 63.835 15.440 ;
        RECT 64.945 15.350 65.275 15.440 ;
        RECT 61.725 14.410 62.395 15.350 ;
        RECT 63.165 14.410 63.835 15.350 ;
        RECT 64.605 14.410 65.275 15.350 ;
        RECT 72.685 14.580 73.135 16.220 ;
        RECT 75.225 15.895 75.395 16.220 ;
        RECT 75.645 15.845 75.815 16.880 ;
        RECT 77.100 16.410 77.510 16.555 ;
        RECT 77.100 16.100 77.625 16.410 ;
        RECT 77.435 15.685 77.625 16.100 ;
        RECT 85.185 15.880 85.360 17.160 ;
        RECT 85.610 15.885 85.785 16.985 ;
        RECT 86.030 16.060 86.205 17.160 ;
        RECT 86.450 16.460 86.625 17.030 ;
        RECT 86.450 15.905 87.105 16.460 ;
        RECT 88.180 15.905 88.415 16.485 ;
        RECT 89.540 15.905 89.775 16.485 ;
        RECT 91.350 16.460 91.525 16.925 ;
        RECT 95.610 16.885 95.910 17.145 ;
        RECT 101.680 17.045 101.950 17.575 ;
        RECT 113.905 17.045 114.175 17.575 ;
        RECT 126.170 17.045 126.440 17.575 ;
        RECT 138.420 17.045 138.690 17.575 ;
        RECT 90.865 15.905 91.525 16.460 ;
        RECT 86.450 15.885 86.625 15.905 ;
        RECT 85.610 15.715 86.625 15.885 ;
        RECT 91.350 15.735 91.525 15.905 ;
        RECT 92.190 15.735 92.365 16.835 ;
        RECT 94.770 16.650 95.910 16.885 ;
        RECT 96.610 16.875 107.015 17.045 ;
        RECT 108.835 16.875 119.240 17.045 ;
        RECT 121.100 16.875 131.505 17.045 ;
        RECT 133.350 16.875 143.755 17.045 ;
        RECT 91.350 15.565 92.365 15.735 ;
        RECT 93.680 15.695 94.180 16.245 ;
        RECT 94.770 15.845 94.955 16.650 ;
        RECT 95.610 16.385 95.910 16.650 ;
        RECT 95.610 15.850 95.850 16.385 ;
        RECT 101.680 16.345 101.950 16.875 ;
        RECT 113.905 16.345 114.175 16.875 ;
        RECT 126.170 16.345 126.440 16.875 ;
        RECT 138.420 16.345 138.690 16.875 ;
        RECT 96.610 16.175 107.015 16.345 ;
        RECT 108.835 16.175 119.240 16.345 ;
        RECT 121.100 16.175 131.505 16.345 ;
        RECT 133.350 16.175 143.755 16.345 ;
        RECT 101.680 15.645 101.950 16.175 ;
        RECT 113.905 15.645 114.175 16.175 ;
        RECT 126.170 15.645 126.440 16.175 ;
        RECT 138.420 15.645 138.690 16.175 ;
        RECT 96.610 15.475 107.015 15.645 ;
        RECT 108.835 15.475 119.240 15.645 ;
        RECT 121.100 15.475 131.505 15.645 ;
        RECT 133.350 15.475 143.755 15.645 ;
        RECT 101.680 14.945 101.950 15.475 ;
        RECT 113.905 14.945 114.175 15.475 ;
        RECT 126.170 14.945 126.440 15.475 ;
        RECT 138.420 14.945 138.690 15.475 ;
        RECT 96.610 14.775 107.015 14.945 ;
        RECT 108.835 14.775 119.240 14.945 ;
        RECT 121.100 14.775 131.505 14.945 ;
        RECT 133.350 14.775 143.755 14.945 ;
        RECT 61.205 13.760 61.535 14.240 ;
        RECT 61.725 13.590 61.895 14.410 ;
        RECT 62.065 13.760 62.395 14.240 ;
        RECT 62.645 13.760 62.975 14.240 ;
        RECT 63.165 13.590 63.335 14.410 ;
        RECT 63.505 13.760 63.835 14.240 ;
        RECT 64.605 13.590 64.775 14.410 ;
        RECT 65.525 13.760 65.855 14.240 ;
        RECT 66.385 13.760 66.715 14.240 ;
        RECT 72.685 14.215 74.615 14.580 ;
        RECT 101.680 14.245 101.950 14.775 ;
        RECT 113.905 14.245 114.175 14.775 ;
        RECT 126.170 14.245 126.440 14.775 ;
        RECT 138.420 14.245 138.690 14.775 ;
        RECT 96.610 14.075 107.015 14.245 ;
        RECT 108.835 14.075 119.240 14.245 ;
        RECT 121.100 14.075 131.505 14.245 ;
        RECT 133.350 14.075 143.755 14.245 ;
        RECT 61.645 12.810 61.895 13.590 ;
        RECT 63.085 12.810 63.335 13.590 ;
        RECT 64.525 12.810 64.775 13.590 ;
        RECT 101.680 13.545 101.950 14.075 ;
        RECT 113.905 13.545 114.175 14.075 ;
        RECT 126.170 13.545 126.440 14.075 ;
        RECT 138.420 13.545 138.690 14.075 ;
        RECT 96.610 13.375 107.015 13.545 ;
        RECT 108.835 13.375 119.240 13.545 ;
        RECT 121.100 13.375 131.505 13.545 ;
        RECT 133.350 13.375 143.755 13.545 ;
        RECT 101.680 12.845 101.950 13.375 ;
        RECT 113.905 12.845 114.175 13.375 ;
        RECT 126.170 12.845 126.440 13.375 ;
        RECT 138.420 12.845 138.690 13.375 ;
        RECT 96.610 12.675 107.015 12.845 ;
        RECT 108.835 12.675 119.240 12.845 ;
        RECT 121.100 12.675 131.505 12.845 ;
        RECT 133.350 12.675 143.755 12.845 ;
        RECT 101.680 12.145 101.950 12.675 ;
        RECT 113.905 12.145 114.175 12.675 ;
        RECT 126.170 12.145 126.440 12.675 ;
        RECT 138.420 12.145 138.690 12.675 ;
        RECT 96.610 11.975 107.015 12.145 ;
        RECT 108.835 11.975 119.240 12.145 ;
        RECT 121.100 11.975 131.505 12.145 ;
        RECT 133.350 11.975 143.755 12.145 ;
        RECT 101.680 11.445 101.950 11.975 ;
        RECT 113.905 11.445 114.175 11.975 ;
        RECT 126.170 11.445 126.440 11.975 ;
        RECT 138.420 11.445 138.690 11.975 ;
        RECT 96.610 11.275 107.015 11.445 ;
        RECT 108.835 11.275 119.240 11.445 ;
        RECT 121.100 11.275 131.505 11.445 ;
        RECT 133.350 11.275 143.755 11.445 ;
        RECT 2.165 9.375 2.580 9.745 ;
        RECT 3.015 9.545 3.355 11.085 ;
        RECT 3.585 9.545 3.915 10.345 ;
        RECT 4.305 10.145 4.825 11.175 ;
        RECT 5.905 11.085 6.235 11.175 ;
        RECT 4.085 9.545 4.485 9.975 ;
        RECT 4.655 9.375 4.825 10.145 ;
        RECT 5.565 10.145 6.235 11.085 ;
        RECT 7.305 10.315 7.885 11.175 ;
        RECT 8.115 10.655 8.445 11.175 ;
        RECT 9.225 10.655 9.555 11.175 ;
        RECT 8.115 10.485 9.555 10.655 ;
        RECT 7.305 10.145 9.555 10.315 ;
        RECT 5.045 9.495 5.375 9.975 ;
        RECT 2.820 9.205 4.825 9.375 ;
        RECT 5.565 9.325 5.735 10.145 ;
        RECT 5.905 9.495 6.235 9.975 ;
        RECT 6.465 9.375 7.135 9.810 ;
        RECT 2.820 8.545 3.080 9.205 ;
        RECT 3.850 8.545 4.180 9.205 ;
        RECT 5.485 8.545 5.735 9.325 ;
        RECT 7.305 9.235 7.475 10.145 ;
        RECT 8.875 9.890 9.205 9.975 ;
        RECT 7.645 9.560 9.205 9.890 ;
        RECT 8.875 9.545 9.205 9.560 ;
        RECT 9.385 9.845 9.555 10.145 ;
        RECT 9.725 10.015 10.115 11.175 ;
        RECT 11.350 11.100 13.325 11.270 ;
        RECT 9.385 9.515 9.775 9.845 ;
        RECT 9.945 9.345 10.115 10.015 ;
        RECT 7.305 8.905 8.000 9.235 ;
        RECT 8.885 9.175 10.115 9.345 ;
        RECT 10.315 10.425 10.645 10.895 ;
        RECT 11.350 10.425 11.520 11.100 ;
        RECT 10.315 10.255 11.520 10.425 ;
        RECT 10.315 10.145 10.645 10.255 ;
        RECT 10.315 9.325 10.485 10.145 ;
        RECT 12.265 10.085 12.595 10.930 ;
        RECT 10.705 9.545 11.035 9.975 ;
        RECT 11.205 9.915 12.595 10.085 ;
        RECT 8.885 8.610 9.330 9.175 ;
        RECT 10.315 8.735 10.645 9.325 ;
        RECT 11.205 9.215 11.375 9.915 ;
        RECT 13.155 9.845 13.325 11.100 ;
        RECT 13.995 10.015 14.435 11.175 ;
        RECT 12.085 9.375 12.475 9.745 ;
        RECT 13.155 9.515 13.555 9.845 ;
        RECT 13.725 9.495 14.095 9.825 ;
        RECT 13.725 9.345 13.895 9.495 ;
        RECT 11.205 9.045 11.545 9.215 ;
        RECT 11.375 8.835 11.545 9.045 ;
        RECT 13.155 9.175 13.895 9.345 ;
        RECT 14.265 9.325 14.435 10.015 ;
        RECT 13.155 8.835 13.325 9.175 ;
        RECT 11.375 8.585 13.325 8.835 ;
        RECT 14.065 8.545 14.435 9.325 ;
        RECT 15.085 10.225 15.445 11.175 ;
        RECT 17.320 11.100 18.380 11.270 ;
        RECT 15.085 9.325 15.255 10.225 ;
        RECT 16.150 10.055 16.400 10.895 ;
        RECT 16.780 10.055 17.110 10.435 ;
        RECT 17.320 10.245 17.650 11.100 ;
        RECT 18.210 10.990 18.380 11.100 ;
        RECT 19.700 10.990 21.080 11.160 ;
        RECT 21.815 10.990 22.145 11.175 ;
        RECT 17.870 10.075 18.040 10.930 ;
        RECT 15.425 9.885 17.110 10.055 ;
        RECT 15.425 9.545 15.785 9.885 ;
        RECT 16.780 9.765 17.110 9.885 ;
        RECT 17.340 9.905 18.040 10.075 ;
        RECT 18.210 10.820 19.870 10.990 ;
        RECT 20.910 10.820 22.145 10.990 ;
        RECT 15.085 8.545 15.445 9.325 ;
        RECT 15.615 9.215 15.785 9.545 ;
        RECT 15.955 9.595 16.285 9.715 ;
        RECT 17.340 9.595 17.510 9.905 ;
        RECT 18.210 9.735 18.380 10.820 ;
        RECT 20.040 10.650 20.400 10.820 ;
        RECT 15.955 9.425 17.510 9.595 ;
        RECT 15.955 9.385 16.285 9.425 ;
        RECT 15.615 9.045 16.370 9.215 ;
        RECT 16.120 8.545 16.370 9.045 ;
        RECT 17.340 9.175 17.510 9.425 ;
        RECT 17.680 9.565 18.380 9.735 ;
        RECT 18.550 10.320 18.825 10.650 ;
        RECT 19.020 10.480 20.400 10.650 ;
        RECT 17.680 9.345 17.990 9.565 ;
        RECT 18.550 9.395 18.720 10.320 ;
        RECT 19.020 10.150 19.190 10.480 ;
        RECT 18.890 9.820 19.190 10.150 ;
        RECT 19.400 9.945 20.060 10.275 ;
        RECT 18.900 9.395 19.230 9.610 ;
        RECT 18.160 9.225 19.230 9.395 ;
        RECT 17.340 8.925 17.940 9.175 ;
        RECT 18.160 8.790 18.330 9.225 ;
        RECT 19.400 9.055 19.570 9.945 ;
        RECT 20.230 9.775 20.400 10.480 ;
        RECT 18.500 8.885 19.570 9.055 ;
        RECT 17.265 8.620 17.595 8.705 ;
        RECT 18.500 8.620 18.670 8.885 ;
        RECT 17.265 8.450 18.670 8.620 ;
        RECT 19.400 8.640 19.570 8.885 ;
        RECT 19.740 9.605 20.400 9.775 ;
        RECT 19.740 8.810 20.005 9.605 ;
        RECT 20.570 9.435 20.740 10.820 ;
        RECT 20.185 9.265 20.740 9.435 ;
        RECT 20.910 10.220 21.290 10.550 ;
        RECT 20.910 9.320 21.190 10.220 ;
        RECT 21.685 10.015 22.145 10.820 ;
        RECT 22.715 10.315 23.045 11.175 ;
        RECT 23.725 10.715 24.055 11.175 ;
        RECT 23.850 10.675 24.055 10.715 ;
        RECT 26.225 10.675 26.555 10.950 ;
        RECT 23.850 10.505 26.555 10.675 ;
        RECT 26.755 10.780 27.005 10.950 ;
        RECT 28.150 10.780 28.485 10.875 ;
        RECT 26.755 10.610 28.485 10.780 ;
        RECT 22.315 10.145 23.045 10.315 ;
        RECT 21.685 9.875 21.855 10.015 ;
        RECT 21.400 9.545 21.855 9.875 ;
        RECT 22.315 9.745 22.485 10.145 ;
        RECT 20.505 8.925 21.515 9.095 ;
        RECT 20.505 8.640 20.675 8.925 ;
        RECT 19.400 8.470 20.675 8.640 ;
        RECT 21.345 8.620 21.515 8.925 ;
        RECT 21.685 8.790 21.855 9.545 ;
        RECT 22.025 9.325 22.485 9.745 ;
        RECT 22.655 9.495 23.035 9.975 ;
        RECT 22.025 9.155 23.045 9.325 ;
        RECT 23.285 9.195 23.680 10.390 ;
        RECT 22.025 8.620 22.195 9.155 ;
        RECT 21.345 8.450 22.195 8.620 ;
        RECT 22.795 8.545 23.045 9.155 ;
        RECT 23.850 9.025 24.020 10.505 ;
        RECT 26.225 10.440 26.555 10.505 ;
        RECT 24.190 9.325 24.460 10.335 ;
        RECT 24.630 10.005 24.985 10.335 ;
        RECT 25.635 10.100 25.965 10.335 ;
        RECT 26.225 10.270 27.000 10.440 ;
        RECT 24.630 9.335 24.800 10.005 ;
        RECT 25.205 9.835 25.435 9.975 ;
        RECT 25.635 9.930 26.660 10.100 ;
        RECT 24.970 9.505 25.435 9.835 ;
        RECT 26.105 9.770 26.660 9.930 ;
        RECT 25.605 9.335 25.935 9.745 ;
        RECT 23.330 8.855 24.020 9.025 ;
        RECT 24.630 9.165 25.935 9.335 ;
        RECT 23.330 8.565 23.660 8.855 ;
        RECT 24.630 8.545 25.080 9.165 ;
        RECT 26.105 8.995 26.275 9.770 ;
        RECT 26.830 9.565 27.000 10.270 ;
        RECT 25.750 8.620 26.275 8.995 ;
        RECT 26.445 9.395 27.000 9.565 ;
        RECT 26.445 8.790 26.695 9.395 ;
        RECT 27.170 9.225 27.340 10.610 ;
        RECT 28.050 10.545 28.485 10.610 ;
        RECT 26.865 8.790 27.340 9.225 ;
        RECT 27.510 9.285 27.790 10.350 ;
        RECT 28.050 9.810 28.220 10.545 ;
        RECT 28.390 10.020 28.770 10.350 ;
        RECT 28.050 9.640 28.720 9.810 ;
        RECT 29.390 9.765 29.640 10.950 ;
        RECT 29.860 10.560 30.825 10.890 ;
        RECT 28.390 9.480 28.720 9.640 ;
        RECT 28.905 9.595 29.640 9.765 ;
        RECT 29.810 10.060 30.485 10.390 ;
        RECT 28.905 9.285 29.075 9.595 ;
        RECT 29.810 9.425 29.980 10.060 ;
        RECT 30.655 9.790 30.825 10.560 ;
        RECT 31.420 10.530 31.800 10.925 ;
        RECT 30.995 10.030 31.460 10.360 ;
        RECT 31.630 10.130 31.800 10.530 ;
        RECT 31.630 9.960 32.130 10.130 ;
        RECT 32.420 10.005 33.110 11.180 ;
        RECT 27.510 9.115 29.075 9.285 ;
        RECT 29.245 9.095 29.980 9.425 ;
        RECT 30.150 9.620 31.790 9.790 ;
        RECT 29.245 8.945 29.415 9.095 ;
        RECT 27.510 8.775 29.415 8.945 ;
        RECT 30.150 8.925 30.320 9.620 ;
        RECT 31.490 9.460 31.790 9.620 ;
        RECT 30.590 9.265 30.920 9.425 ;
        RECT 31.960 9.265 32.130 9.960 ;
        RECT 30.590 9.095 32.130 9.265 ;
        RECT 27.510 8.620 27.680 8.775 ;
        RECT 25.750 8.450 27.680 8.620 ;
        RECT 29.585 8.595 30.320 8.925 ;
        RECT 31.645 8.545 32.130 9.095 ;
        RECT 32.720 8.545 33.110 10.005 ;
        RECT 33.350 9.825 33.600 11.170 ;
        RECT 34.235 10.015 34.595 11.175 ;
        RECT 33.350 9.495 34.255 9.825 ;
        RECT 33.350 8.545 33.600 9.495 ;
        RECT 34.425 9.325 34.595 10.015 ;
        RECT 34.225 8.545 34.595 9.325 ;
        RECT 35.245 10.045 35.640 11.175 ;
        RECT 36.375 10.215 36.705 11.195 ;
        RECT 35.810 10.045 37.300 10.215 ;
        RECT 35.245 9.375 35.415 10.045 ;
        RECT 35.810 9.875 35.980 10.045 ;
        RECT 35.585 9.545 35.980 9.875 ;
        RECT 36.155 9.375 36.485 9.875 ;
        RECT 35.245 8.665 35.720 9.375 ;
        RECT 36.970 9.035 37.300 10.045 ;
        RECT 37.645 10.015 38.035 11.175 ;
        RECT 38.205 10.655 38.535 11.175 ;
        RECT 39.315 10.655 39.645 11.175 ;
        RECT 38.205 10.485 39.645 10.655 ;
        RECT 39.875 10.315 40.455 11.175 ;
        RECT 38.205 10.145 40.455 10.315 ;
        RECT 37.645 9.345 37.815 10.015 ;
        RECT 38.205 9.845 38.375 10.145 ;
        RECT 37.985 9.515 38.375 9.845 ;
        RECT 38.555 9.890 38.885 9.975 ;
        RECT 38.555 9.560 40.115 9.890 ;
        RECT 38.555 9.545 38.885 9.560 ;
        RECT 37.645 9.175 38.875 9.345 ;
        RECT 40.285 9.235 40.455 10.145 ;
        RECT 42.925 10.015 43.285 11.175 ;
        RECT 40.625 9.375 41.295 9.810 ;
        RECT 36.725 8.450 37.455 8.865 ;
        RECT 38.430 8.610 38.875 9.175 ;
        RECT 39.760 8.905 40.455 9.235 ;
        RECT 42.925 9.325 43.095 10.015 ;
        RECT 43.920 9.825 44.170 11.170 ;
        RECT 43.265 9.495 44.170 9.825 ;
        RECT 42.925 8.545 43.295 9.325 ;
        RECT 43.920 8.545 44.170 9.495 ;
        RECT 44.410 10.005 45.100 11.180 ;
        RECT 45.720 10.530 46.100 10.925 ;
        RECT 46.695 10.560 47.660 10.890 ;
        RECT 45.720 10.130 45.890 10.530 ;
        RECT 44.410 8.545 44.800 10.005 ;
        RECT 45.390 9.960 45.890 10.130 ;
        RECT 46.060 10.030 46.525 10.360 ;
        RECT 45.390 9.265 45.560 9.960 ;
        RECT 46.695 9.790 46.865 10.560 ;
        RECT 47.035 10.060 47.710 10.390 ;
        RECT 45.730 9.620 47.370 9.790 ;
        RECT 45.730 9.460 46.030 9.620 ;
        RECT 46.600 9.265 46.930 9.425 ;
        RECT 45.390 9.095 46.930 9.265 ;
        RECT 45.390 8.545 45.875 9.095 ;
        RECT 47.200 8.925 47.370 9.620 ;
        RECT 47.540 9.425 47.710 10.060 ;
        RECT 47.880 9.765 48.130 10.950 ;
        RECT 49.035 10.780 49.370 10.875 ;
        RECT 50.515 10.780 50.765 10.950 ;
        RECT 49.035 10.610 50.765 10.780 ;
        RECT 50.965 10.675 51.295 10.950 ;
        RECT 53.465 10.715 53.795 11.175 ;
        RECT 53.465 10.675 53.670 10.715 ;
        RECT 49.035 10.545 49.470 10.610 ;
        RECT 48.750 10.020 49.130 10.350 ;
        RECT 49.300 9.810 49.470 10.545 ;
        RECT 47.880 9.595 48.615 9.765 ;
        RECT 47.540 9.095 48.275 9.425 ;
        RECT 48.445 9.285 48.615 9.595 ;
        RECT 48.800 9.640 49.470 9.810 ;
        RECT 48.800 9.480 49.130 9.640 ;
        RECT 49.730 9.285 50.010 10.350 ;
        RECT 48.445 9.115 50.010 9.285 ;
        RECT 50.180 9.225 50.350 10.610 ;
        RECT 50.965 10.505 53.670 10.675 ;
        RECT 50.965 10.440 51.295 10.505 ;
        RECT 50.520 10.270 51.295 10.440 ;
        RECT 50.520 9.565 50.690 10.270 ;
        RECT 51.555 10.100 51.885 10.335 ;
        RECT 50.860 9.930 51.885 10.100 ;
        RECT 52.535 10.005 52.890 10.335 ;
        RECT 50.860 9.770 51.415 9.930 ;
        RECT 50.520 9.395 51.075 9.565 ;
        RECT 48.105 8.945 48.275 9.095 ;
        RECT 47.200 8.595 47.935 8.925 ;
        RECT 48.105 8.775 50.010 8.945 ;
        RECT 50.180 8.790 50.655 9.225 ;
        RECT 50.825 8.790 51.075 9.395 ;
        RECT 51.245 8.995 51.415 9.770 ;
        RECT 52.085 9.835 52.315 9.975 ;
        RECT 51.585 9.335 51.915 9.745 ;
        RECT 52.085 9.505 52.550 9.835 ;
        RECT 52.720 9.335 52.890 10.005 ;
        RECT 51.585 9.165 52.890 9.335 ;
        RECT 53.060 9.325 53.330 10.335 ;
        RECT 49.840 8.620 50.010 8.775 ;
        RECT 51.245 8.620 51.770 8.995 ;
        RECT 49.840 8.450 51.770 8.620 ;
        RECT 52.440 8.545 52.890 9.165 ;
        RECT 53.500 9.025 53.670 10.505 ;
        RECT 53.840 9.195 54.235 10.390 ;
        RECT 54.445 10.045 54.840 11.175 ;
        RECT 55.575 10.215 55.905 11.195 ;
        RECT 55.010 10.045 56.500 10.215 ;
        RECT 54.445 9.375 54.615 10.045 ;
        RECT 55.010 9.875 55.180 10.045 ;
        RECT 54.785 9.545 55.180 9.875 ;
        RECT 55.355 9.375 55.685 9.875 ;
        RECT 53.500 8.855 54.190 9.025 ;
        RECT 53.860 8.565 54.190 8.855 ;
        RECT 54.445 8.665 54.920 9.375 ;
        RECT 56.170 9.035 56.500 10.045 ;
        RECT 56.885 9.495 57.575 9.975 ;
        RECT 55.925 8.450 56.655 8.865 ;
        RECT 57.745 8.545 58.075 11.175 ;
        RECT 58.325 9.495 59.015 9.975 ;
        RECT 59.185 8.545 59.515 11.175 ;
        RECT 60.245 9.375 60.475 11.175 ;
        RECT 62.065 11.085 62.395 11.175 ;
        RECT 63.505 11.085 63.835 11.175 ;
        RECT 64.945 11.085 65.275 11.175 ;
        RECT 61.725 10.145 62.395 11.085 ;
        RECT 63.165 10.145 63.835 11.085 ;
        RECT 64.605 10.145 65.275 11.085 ;
        RECT 101.680 10.745 101.950 11.275 ;
        RECT 113.905 10.745 114.175 11.275 ;
        RECT 126.170 10.745 126.440 11.275 ;
        RECT 138.420 10.745 138.690 11.275 ;
        RECT 96.610 10.575 107.015 10.745 ;
        RECT 108.835 10.575 119.240 10.745 ;
        RECT 121.100 10.575 131.505 10.745 ;
        RECT 133.350 10.575 143.755 10.745 ;
        RECT 61.205 9.495 61.535 9.975 ;
        RECT 60.305 9.205 60.475 9.375 ;
        RECT 61.725 9.325 61.895 10.145 ;
        RECT 62.065 9.495 62.395 9.975 ;
        RECT 62.645 9.495 62.975 9.975 ;
        RECT 63.165 9.325 63.335 10.145 ;
        RECT 63.505 9.495 63.835 9.975 ;
        RECT 64.605 9.325 64.775 10.145 ;
        RECT 101.680 10.045 101.950 10.575 ;
        RECT 113.905 10.045 114.175 10.575 ;
        RECT 126.170 10.045 126.440 10.575 ;
        RECT 138.420 10.045 138.690 10.575 ;
        RECT 64.945 9.495 65.275 9.975 ;
        RECT 65.525 9.495 65.855 9.975 ;
        RECT 66.385 9.495 66.715 9.975 ;
        RECT 96.610 9.875 107.015 10.045 ;
        RECT 108.835 9.875 119.240 10.045 ;
        RECT 121.100 9.875 131.505 10.045 ;
        RECT 133.350 9.875 143.755 10.045 ;
        RECT 93.450 9.515 93.790 9.705 ;
        RECT 60.305 9.035 60.920 9.205 ;
        RECT 60.590 8.545 60.920 9.035 ;
        RECT 61.645 8.545 61.895 9.325 ;
        RECT 63.085 8.545 63.335 9.325 ;
        RECT 64.525 8.545 64.775 9.325 ;
        RECT 93.450 9.140 94.210 9.515 ;
        RECT 101.680 9.345 101.950 9.875 ;
        RECT 113.905 9.345 114.175 9.875 ;
        RECT 126.170 9.345 126.440 9.875 ;
        RECT 138.420 9.345 138.690 9.875 ;
        RECT 96.610 9.175 107.015 9.345 ;
        RECT 108.835 9.175 119.240 9.345 ;
        RECT 121.100 9.175 131.505 9.345 ;
        RECT 133.350 9.175 143.755 9.345 ;
        RECT 101.680 8.645 101.950 9.175 ;
        RECT 113.905 8.645 114.175 9.175 ;
        RECT 126.170 8.645 126.440 9.175 ;
        RECT 138.420 8.645 138.690 9.175 ;
        RECT 96.610 8.475 107.015 8.645 ;
        RECT 108.835 8.475 119.240 8.645 ;
        RECT 121.100 8.475 131.505 8.645 ;
        RECT 133.350 8.475 143.755 8.645 ;
        RECT 145.135 7.085 145.540 7.845 ;
        RECT 5.045 6.045 6.255 6.905 ;
        RECT 4.970 5.875 6.255 6.045 ;
        RECT 7.305 6.045 7.885 6.905 ;
        RECT 8.115 6.385 8.445 6.905 ;
        RECT 9.225 6.385 9.555 6.905 ;
        RECT 8.115 6.215 9.555 6.385 ;
        RECT 7.305 5.875 9.555 6.045 ;
        RECT 4.545 5.105 4.800 5.705 ;
        RECT 4.970 5.055 5.140 5.875 ;
        RECT 5.310 5.225 5.755 5.705 ;
        RECT 5.925 5.225 6.255 5.705 ;
        RECT 6.465 5.105 7.135 5.540 ;
        RECT 4.970 4.805 6.245 5.055 ;
        RECT 5.055 4.290 5.245 4.805 ;
        RECT 5.915 4.275 6.245 4.805 ;
        RECT 7.305 4.965 7.475 5.875 ;
        RECT 8.875 5.620 9.205 5.705 ;
        RECT 7.645 5.290 9.205 5.620 ;
        RECT 8.875 5.275 9.205 5.290 ;
        RECT 9.385 5.575 9.555 5.875 ;
        RECT 9.725 5.745 10.115 6.905 ;
        RECT 11.350 6.830 13.325 7.000 ;
        RECT 9.385 5.245 9.775 5.575 ;
        RECT 9.945 5.075 10.115 5.745 ;
        RECT 7.305 4.635 8.000 4.965 ;
        RECT 8.885 4.905 10.115 5.075 ;
        RECT 10.315 6.155 10.645 6.625 ;
        RECT 11.350 6.155 11.520 6.830 ;
        RECT 10.315 5.985 11.520 6.155 ;
        RECT 10.315 5.875 10.645 5.985 ;
        RECT 10.315 5.055 10.485 5.875 ;
        RECT 12.265 5.815 12.595 6.660 ;
        RECT 10.705 5.275 11.035 5.705 ;
        RECT 11.205 5.645 12.595 5.815 ;
        RECT 8.885 4.340 9.330 4.905 ;
        RECT 10.315 4.465 10.645 5.055 ;
        RECT 11.205 4.945 11.375 5.645 ;
        RECT 13.155 5.575 13.325 6.830 ;
        RECT 13.995 5.745 14.435 6.905 ;
        RECT 12.085 5.105 12.475 5.475 ;
        RECT 13.155 5.245 13.555 5.575 ;
        RECT 13.725 5.225 14.095 5.555 ;
        RECT 13.725 5.075 13.895 5.225 ;
        RECT 11.205 4.775 11.545 4.945 ;
        RECT 11.375 4.565 11.545 4.775 ;
        RECT 13.155 4.905 13.895 5.075 ;
        RECT 14.265 5.055 14.435 5.745 ;
        RECT 13.155 4.565 13.325 4.905 ;
        RECT 11.375 4.315 13.325 4.565 ;
        RECT 14.065 4.275 14.435 5.055 ;
        RECT 15.085 5.955 15.445 6.905 ;
        RECT 17.320 6.830 18.380 7.000 ;
        RECT 15.085 5.055 15.255 5.955 ;
        RECT 16.150 5.785 16.400 6.625 ;
        RECT 16.780 5.785 17.110 6.165 ;
        RECT 17.320 5.975 17.650 6.830 ;
        RECT 18.210 6.720 18.380 6.830 ;
        RECT 19.700 6.720 21.080 6.890 ;
        RECT 21.815 6.720 22.145 6.905 ;
        RECT 17.870 5.805 18.040 6.660 ;
        RECT 15.425 5.615 17.110 5.785 ;
        RECT 15.425 5.275 15.785 5.615 ;
        RECT 16.780 5.495 17.110 5.615 ;
        RECT 17.340 5.635 18.040 5.805 ;
        RECT 18.210 6.550 19.870 6.720 ;
        RECT 20.910 6.550 22.145 6.720 ;
        RECT 15.085 4.275 15.445 5.055 ;
        RECT 15.615 4.945 15.785 5.275 ;
        RECT 15.955 5.325 16.285 5.445 ;
        RECT 17.340 5.325 17.510 5.635 ;
        RECT 18.210 5.465 18.380 6.550 ;
        RECT 20.040 6.380 20.400 6.550 ;
        RECT 15.955 5.155 17.510 5.325 ;
        RECT 15.955 5.115 16.285 5.155 ;
        RECT 15.615 4.775 16.370 4.945 ;
        RECT 16.120 4.275 16.370 4.775 ;
        RECT 17.340 4.905 17.510 5.155 ;
        RECT 17.680 5.295 18.380 5.465 ;
        RECT 18.550 6.050 18.825 6.380 ;
        RECT 19.020 6.210 20.400 6.380 ;
        RECT 17.680 5.075 17.990 5.295 ;
        RECT 18.550 5.125 18.720 6.050 ;
        RECT 19.020 5.880 19.190 6.210 ;
        RECT 18.890 5.550 19.190 5.880 ;
        RECT 19.400 5.675 20.060 6.005 ;
        RECT 18.900 5.125 19.230 5.340 ;
        RECT 18.160 4.955 19.230 5.125 ;
        RECT 17.340 4.655 17.940 4.905 ;
        RECT 18.160 4.520 18.330 4.955 ;
        RECT 19.400 4.785 19.570 5.675 ;
        RECT 20.230 5.505 20.400 6.210 ;
        RECT 18.500 4.615 19.570 4.785 ;
        RECT 17.265 4.350 17.595 4.435 ;
        RECT 18.500 4.350 18.670 4.615 ;
        RECT 17.265 4.180 18.670 4.350 ;
        RECT 19.400 4.370 19.570 4.615 ;
        RECT 19.740 5.335 20.400 5.505 ;
        RECT 19.740 4.540 20.005 5.335 ;
        RECT 20.570 5.165 20.740 6.550 ;
        RECT 20.185 4.995 20.740 5.165 ;
        RECT 20.910 5.950 21.290 6.280 ;
        RECT 20.910 5.050 21.190 5.950 ;
        RECT 21.685 5.745 22.145 6.550 ;
        RECT 22.715 6.045 23.045 6.905 ;
        RECT 23.725 6.445 24.055 6.905 ;
        RECT 23.850 6.405 24.055 6.445 ;
        RECT 26.225 6.405 26.555 6.680 ;
        RECT 23.850 6.235 26.555 6.405 ;
        RECT 26.755 6.510 27.005 6.680 ;
        RECT 28.150 6.510 28.485 6.605 ;
        RECT 26.755 6.340 28.485 6.510 ;
        RECT 22.315 5.875 23.045 6.045 ;
        RECT 21.685 5.605 21.855 5.745 ;
        RECT 21.400 5.275 21.855 5.605 ;
        RECT 22.315 5.475 22.485 5.875 ;
        RECT 20.505 4.655 21.515 4.825 ;
        RECT 20.505 4.370 20.675 4.655 ;
        RECT 19.400 4.200 20.675 4.370 ;
        RECT 21.345 4.350 21.515 4.655 ;
        RECT 21.685 4.520 21.855 5.275 ;
        RECT 22.025 5.055 22.485 5.475 ;
        RECT 22.655 5.225 23.035 5.705 ;
        RECT 22.025 4.885 23.045 5.055 ;
        RECT 23.285 4.925 23.680 6.120 ;
        RECT 22.025 4.350 22.195 4.885 ;
        RECT 21.345 4.180 22.195 4.350 ;
        RECT 22.795 4.275 23.045 4.885 ;
        RECT 23.850 4.755 24.020 6.235 ;
        RECT 26.225 6.170 26.555 6.235 ;
        RECT 24.190 5.055 24.460 6.065 ;
        RECT 24.630 5.735 24.985 6.065 ;
        RECT 25.635 5.830 25.965 6.065 ;
        RECT 26.225 6.000 27.000 6.170 ;
        RECT 24.630 5.065 24.800 5.735 ;
        RECT 25.205 5.565 25.435 5.705 ;
        RECT 25.635 5.660 26.660 5.830 ;
        RECT 24.970 5.235 25.435 5.565 ;
        RECT 26.105 5.500 26.660 5.660 ;
        RECT 25.605 5.065 25.935 5.475 ;
        RECT 23.330 4.585 24.020 4.755 ;
        RECT 24.630 4.895 25.935 5.065 ;
        RECT 23.330 4.295 23.660 4.585 ;
        RECT 24.630 4.275 25.080 4.895 ;
        RECT 26.105 4.725 26.275 5.500 ;
        RECT 26.830 5.295 27.000 6.000 ;
        RECT 25.750 4.350 26.275 4.725 ;
        RECT 26.445 5.125 27.000 5.295 ;
        RECT 26.445 4.520 26.695 5.125 ;
        RECT 27.170 4.955 27.340 6.340 ;
        RECT 28.050 6.275 28.485 6.340 ;
        RECT 26.865 4.520 27.340 4.955 ;
        RECT 27.510 5.015 27.790 6.080 ;
        RECT 28.050 5.540 28.220 6.275 ;
        RECT 28.390 5.750 28.770 6.080 ;
        RECT 28.050 5.370 28.720 5.540 ;
        RECT 29.390 5.495 29.640 6.680 ;
        RECT 29.860 6.290 30.825 6.620 ;
        RECT 28.390 5.210 28.720 5.370 ;
        RECT 28.905 5.325 29.640 5.495 ;
        RECT 29.810 5.790 30.485 6.120 ;
        RECT 28.905 5.015 29.075 5.325 ;
        RECT 29.810 5.155 29.980 5.790 ;
        RECT 30.655 5.520 30.825 6.290 ;
        RECT 31.420 6.260 31.800 6.655 ;
        RECT 30.995 5.760 31.460 6.090 ;
        RECT 31.630 5.860 31.800 6.260 ;
        RECT 31.630 5.690 32.130 5.860 ;
        RECT 32.420 5.735 33.110 6.910 ;
        RECT 27.510 4.845 29.075 5.015 ;
        RECT 29.245 4.825 29.980 5.155 ;
        RECT 30.150 5.350 31.790 5.520 ;
        RECT 29.245 4.675 29.415 4.825 ;
        RECT 27.510 4.505 29.415 4.675 ;
        RECT 30.150 4.655 30.320 5.350 ;
        RECT 31.490 5.190 31.790 5.350 ;
        RECT 30.590 4.995 30.920 5.155 ;
        RECT 31.960 4.995 32.130 5.690 ;
        RECT 30.590 4.825 32.130 4.995 ;
        RECT 27.510 4.350 27.680 4.505 ;
        RECT 25.750 4.180 27.680 4.350 ;
        RECT 29.585 4.325 30.320 4.655 ;
        RECT 31.645 4.275 32.130 4.825 ;
        RECT 32.720 4.275 33.110 5.735 ;
        RECT 33.350 5.555 33.600 6.900 ;
        RECT 34.235 5.745 34.595 6.905 ;
        RECT 33.350 5.225 34.255 5.555 ;
        RECT 33.350 4.275 33.600 5.225 ;
        RECT 34.425 5.055 34.595 5.745 ;
        RECT 34.225 4.275 34.595 5.055 ;
        RECT 35.245 5.775 35.640 6.905 ;
        RECT 36.375 5.945 36.705 6.925 ;
        RECT 35.810 5.775 37.300 5.945 ;
        RECT 35.245 5.105 35.415 5.775 ;
        RECT 35.810 5.605 35.980 5.775 ;
        RECT 35.585 5.275 35.980 5.605 ;
        RECT 36.155 5.105 36.485 5.605 ;
        RECT 35.245 4.395 35.720 5.105 ;
        RECT 36.970 4.765 37.300 5.775 ;
        RECT 37.645 5.745 38.035 6.905 ;
        RECT 38.205 6.385 38.535 6.905 ;
        RECT 39.315 6.385 39.645 6.905 ;
        RECT 38.205 6.215 39.645 6.385 ;
        RECT 39.875 6.045 40.455 6.905 ;
        RECT 38.205 5.875 40.455 6.045 ;
        RECT 37.645 5.075 37.815 5.745 ;
        RECT 38.205 5.575 38.375 5.875 ;
        RECT 37.985 5.245 38.375 5.575 ;
        RECT 38.555 5.620 38.885 5.705 ;
        RECT 38.555 5.290 40.115 5.620 ;
        RECT 38.555 5.275 38.885 5.290 ;
        RECT 37.645 4.905 38.875 5.075 ;
        RECT 40.285 4.965 40.455 5.875 ;
        RECT 42.275 6.075 42.605 6.905 ;
        RECT 43.335 6.075 43.665 6.905 ;
        RECT 42.275 5.815 43.665 6.075 ;
        RECT 41.635 5.745 43.665 5.815 ;
        RECT 44.395 5.775 44.680 6.905 ;
        RECT 45.760 6.045 46.045 6.775 ;
        RECT 46.715 6.045 47.045 6.775 ;
        RECT 44.920 5.875 47.045 6.045 ;
        RECT 41.635 5.645 42.605 5.745 ;
        RECT 40.625 5.105 41.295 5.540 ;
        RECT 36.725 4.180 37.455 4.595 ;
        RECT 38.430 4.340 38.875 4.905 ;
        RECT 39.760 4.635 40.455 4.965 ;
        RECT 41.635 4.935 41.805 5.645 ;
        RECT 41.975 5.105 42.305 5.475 ;
        RECT 42.485 5.105 42.875 5.475 ;
        RECT 43.115 5.105 43.675 5.475 ;
        RECT 43.845 5.105 44.175 5.475 ;
        RECT 44.395 5.105 44.565 5.775 ;
        RECT 44.920 5.605 45.090 5.875 ;
        RECT 44.760 5.275 45.090 5.605 ;
        RECT 45.345 5.375 45.675 5.705 ;
        RECT 45.845 5.105 46.315 5.705 ;
        RECT 44.395 4.935 44.965 5.105 ;
        RECT 41.635 4.765 44.140 4.935 ;
        RECT 43.810 4.275 44.140 4.765 ;
        RECT 44.635 4.405 44.965 4.935 ;
        RECT 46.680 4.665 47.045 5.875 ;
        RECT 47.245 5.775 47.640 6.905 ;
        RECT 48.375 5.945 48.705 6.925 ;
        RECT 47.810 5.775 49.300 5.945 ;
        RECT 47.245 5.105 47.415 5.775 ;
        RECT 47.810 5.605 47.980 5.775 ;
        RECT 47.585 5.275 47.980 5.605 ;
        RECT 48.155 5.105 48.485 5.605 ;
        RECT 45.845 4.495 46.075 4.595 ;
        RECT 45.845 4.180 47.055 4.495 ;
        RECT 47.245 4.395 47.720 5.105 ;
        RECT 48.970 4.765 49.300 5.775 ;
        RECT 51.595 5.745 51.925 6.905 ;
        RECT 51.595 4.975 51.765 5.745 ;
        RECT 52.630 5.475 52.800 6.800 ;
        RECT 51.940 5.145 52.800 5.475 ;
        RECT 48.725 4.180 49.455 4.595 ;
        RECT 51.595 4.275 51.925 4.975 ;
        RECT 52.605 4.865 52.800 5.145 ;
        RECT 53.045 5.105 53.360 6.905 ;
        RECT 54.150 6.485 54.480 6.905 ;
        RECT 53.165 5.055 53.360 5.105 ;
        RECT 53.745 6.315 54.480 6.485 ;
        RECT 54.710 6.405 55.040 6.905 ;
        RECT 57.940 6.830 58.870 7.000 ;
        RECT 56.030 6.575 56.720 6.830 ;
        RECT 55.580 6.405 56.720 6.575 ;
        RECT 52.605 4.275 52.935 4.865 ;
        RECT 53.165 4.275 53.495 5.055 ;
        RECT 53.745 4.935 53.915 6.315 ;
        RECT 54.710 6.145 55.750 6.405 ;
        RECT 54.085 5.975 55.750 6.145 ;
        RECT 54.085 5.135 54.415 5.975 ;
        RECT 55.920 5.945 56.250 6.235 ;
        RECT 54.810 5.105 55.195 5.705 ;
        RECT 55.380 4.935 55.710 5.805 ;
        RECT 53.745 4.765 55.710 4.935 ;
        RECT 54.225 4.340 54.555 4.765 ;
        RECT 55.920 4.350 56.090 5.945 ;
        RECT 56.470 5.885 56.720 6.405 ;
        RECT 57.940 6.220 58.110 6.830 ;
        RECT 57.445 6.050 58.110 6.220 ;
        RECT 56.470 5.775 56.640 5.885 ;
        RECT 56.260 5.605 56.640 5.775 ;
        RECT 57.445 5.715 57.615 6.050 ;
        RECT 58.280 5.920 58.530 6.660 ;
        RECT 58.700 6.260 58.870 6.830 ;
        RECT 59.605 6.830 61.375 7.000 ;
        RECT 59.605 6.260 59.775 6.830 ;
        RECT 58.700 6.090 59.775 6.260 ;
        RECT 56.260 4.850 56.430 5.605 ;
        RECT 56.875 5.545 57.615 5.715 ;
        RECT 56.875 5.375 57.045 5.545 ;
        RECT 57.785 5.475 58.075 5.880 ;
        RECT 58.280 5.700 59.250 5.920 ;
        RECT 56.600 5.045 57.045 5.375 ;
        RECT 57.215 5.215 57.545 5.375 ;
        RECT 58.245 5.360 59.365 5.530 ;
        RECT 58.245 5.215 58.530 5.360 ;
        RECT 57.215 5.045 58.530 5.215 ;
        RECT 56.260 4.520 56.705 4.850 ;
        RECT 56.875 4.350 57.045 5.045 ;
        RECT 58.245 4.980 58.530 5.045 ;
        RECT 58.705 4.810 59.025 5.190 ;
        RECT 59.195 4.980 59.365 5.360 ;
        RECT 59.535 5.285 59.775 6.090 ;
        RECT 59.945 6.220 60.305 6.660 ;
        RECT 60.475 6.220 60.955 6.660 ;
        RECT 61.125 6.325 61.375 6.830 ;
        RECT 63.115 6.285 63.365 6.905 ;
        RECT 65.015 6.415 65.315 6.905 ;
        RECT 59.945 4.980 60.115 6.220 ;
        RECT 60.785 6.155 60.955 6.220 ;
        RECT 61.685 6.155 63.365 6.285 ;
        RECT 60.785 6.115 63.365 6.155 ;
        RECT 59.195 4.810 60.115 4.980 ;
        RECT 58.300 4.360 58.875 4.810 ;
        RECT 55.920 4.180 57.045 4.350 ;
        RECT 59.865 4.310 60.115 4.810 ;
        RECT 60.285 5.360 60.615 6.030 ;
        RECT 60.785 5.985 61.855 6.115 ;
        RECT 60.285 4.350 60.455 5.360 ;
        RECT 60.785 4.770 60.955 5.985 ;
        RECT 62.025 5.815 62.505 5.945 ;
        RECT 61.125 5.645 62.505 5.815 ;
        RECT 61.125 5.225 61.455 5.645 ;
        RECT 61.685 5.105 62.165 5.475 ;
        RECT 60.625 4.520 60.955 4.770 ;
        RECT 61.185 4.350 61.435 5.055 ;
        RECT 62.335 4.935 62.505 5.645 ;
        RECT 60.285 4.180 61.435 4.350 ;
        RECT 62.045 4.275 62.505 4.935 ;
        RECT 63.195 4.765 63.365 6.115 ;
        RECT 63.695 6.245 65.315 6.415 ;
        RECT 63.695 5.555 63.865 6.245 ;
        RECT 64.035 5.745 64.365 6.075 ;
        RECT 63.695 4.885 64.025 5.555 ;
        RECT 63.115 4.305 63.365 4.765 ;
        RECT 64.195 4.715 64.365 5.745 ;
        RECT 64.565 4.935 64.975 6.075 ;
        RECT 65.145 4.735 65.315 6.245 ;
        RECT 68.295 5.675 68.675 6.905 ;
        RECT 66.755 5.505 68.675 5.675 ;
        RECT 66.755 5.275 67.765 5.505 ;
        RECT 67.935 5.005 68.335 5.335 ;
        RECT 68.505 4.735 68.675 5.505 ;
        RECT 74.425 5.255 74.620 6.065 ;
        RECT 75.695 6.015 77.960 6.190 ;
        RECT 74.020 4.910 74.620 5.255 ;
        RECT 75.390 5.170 77.545 5.345 ;
        RECT 75.390 5.100 75.570 5.170 ;
        RECT 64.025 4.275 64.365 4.715 ;
        RECT 64.955 4.275 65.315 4.735 ;
        RECT 68.300 4.405 68.675 4.735 ;
        RECT 74.425 3.945 74.620 4.910 ;
        RECT 74.850 4.875 75.570 5.100 ;
        RECT 75.390 4.405 75.570 4.875 ;
        RECT 75.820 4.915 76.465 4.965 ;
        RECT 75.820 4.645 76.640 4.915 ;
        RECT 76.445 4.405 76.640 4.645 ;
        RECT 77.780 4.405 77.960 6.015 ;
        RECT 78.160 5.790 78.355 6.130 ;
        RECT 80.715 5.920 85.380 6.150 ;
        RECT 85.180 5.750 85.375 5.920 ;
        RECT 85.180 5.705 85.435 5.750 ;
        RECT 78.165 5.185 78.360 5.525 ;
        RECT 80.780 5.095 84.775 5.315 ;
        RECT 75.390 4.235 75.795 4.405 ;
        RECT 75.600 3.990 75.795 4.235 ;
        RECT 76.445 4.235 77.960 4.405 ;
        RECT 76.445 4.015 76.640 4.235 ;
        RECT 81.335 4.215 82.520 5.095 ;
        RECT 85.190 4.285 85.435 5.705 ;
        RECT 86.480 5.000 86.680 5.380 ;
        RECT 86.455 4.930 86.680 5.000 ;
        RECT 87.285 4.930 87.455 6.230 ;
        RECT 88.190 5.040 88.360 6.230 ;
        RECT 89.055 5.510 89.400 5.750 ;
        RECT 89.040 5.105 91.055 5.275 ;
        RECT 88.190 5.020 88.430 5.040 ;
        RECT 86.455 4.660 86.650 4.930 ;
        RECT 86.905 4.725 87.455 4.930 ;
        RECT 88.150 4.935 88.430 5.020 ;
        RECT 89.040 5.010 89.215 5.105 ;
        RECT 86.905 4.670 87.205 4.725 ;
        RECT 87.625 4.680 87.970 4.920 ;
        RECT 88.150 4.705 88.670 4.935 ;
        RECT 88.965 4.810 89.215 5.010 ;
        RECT 90.775 5.070 91.055 5.105 ;
        RECT 86.905 4.655 87.140 4.670 ;
        RECT 80.680 3.995 83.325 4.215 ;
        RECT 83.840 4.010 85.435 4.285 ;
        RECT 83.130 3.590 83.325 3.995 ;
        RECT 85.140 3.590 85.435 4.010 ;
        RECT 86.590 3.495 86.785 3.835 ;
        RECT 86.960 3.605 87.140 4.655 ;
        RECT 88.150 4.655 88.360 4.705 ;
        RECT 88.150 4.445 88.320 4.655 ;
        RECT 87.310 4.275 88.320 4.445 ;
        RECT 88.965 4.280 89.175 4.810 ;
        RECT 89.400 4.765 89.775 4.935 ;
        RECT 90.775 4.865 91.590 5.070 ;
        RECT 89.435 4.475 89.620 4.765 ;
        RECT 88.605 4.105 89.175 4.280 ;
        RECT 89.360 4.270 89.770 4.475 ;
        RECT 90.020 4.415 90.195 4.755 ;
        RECT 92.540 4.745 93.640 4.920 ;
        RECT 94.350 4.915 95.450 4.920 ;
        RECT 96.735 4.915 96.930 5.000 ;
        RECT 97.565 4.930 97.735 6.230 ;
        RECT 98.470 5.040 98.640 6.230 ;
        RECT 99.335 5.510 99.680 5.750 ;
        RECT 99.320 5.105 101.335 5.275 ;
        RECT 98.470 5.020 98.710 5.040 ;
        RECT 94.350 4.745 96.995 4.915 ;
        RECT 96.735 4.660 96.930 4.745 ;
        RECT 97.185 4.725 97.735 4.930 ;
        RECT 98.430 4.935 98.710 5.020 ;
        RECT 99.320 5.010 99.495 5.105 ;
        RECT 97.185 4.670 97.485 4.725 ;
        RECT 97.905 4.680 98.250 4.920 ;
        RECT 98.430 4.705 98.950 4.935 ;
        RECT 99.245 4.810 99.495 5.010 ;
        RECT 101.055 5.070 101.335 5.105 ;
        RECT 97.185 4.655 97.420 4.670 ;
        RECT 88.370 4.075 88.785 4.105 ;
        RECT 88.055 4.025 88.785 4.075 ;
        RECT 87.310 3.910 88.785 4.025 ;
        RECT 87.310 3.905 88.760 3.910 ;
        RECT 87.310 3.855 88.250 3.905 ;
        RECT 88.985 3.670 89.210 3.915 ;
        RECT 90.110 3.680 90.310 3.815 ;
        RECT 86.960 3.430 88.155 3.605 ;
        RECT 88.985 3.485 89.725 3.670 ;
        RECT 89.315 3.435 89.725 3.485 ;
        RECT 89.980 3.455 90.310 3.680 ;
        RECT 96.870 3.495 97.065 3.835 ;
        RECT 97.240 3.605 97.420 4.655 ;
        RECT 98.430 4.655 98.640 4.705 ;
        RECT 98.430 4.445 98.600 4.655 ;
        RECT 97.590 4.275 98.600 4.445 ;
        RECT 99.245 4.280 99.455 4.810 ;
        RECT 99.680 4.765 100.055 4.935 ;
        RECT 101.055 4.865 101.870 5.070 ;
        RECT 99.715 4.475 99.900 4.765 ;
        RECT 98.885 4.105 99.455 4.280 ;
        RECT 99.640 4.270 100.050 4.475 ;
        RECT 100.300 4.415 100.475 4.755 ;
        RECT 102.820 4.745 103.920 4.920 ;
        RECT 104.630 4.915 105.730 4.920 ;
        RECT 107.015 4.915 107.210 5.000 ;
        RECT 107.845 4.930 108.015 6.230 ;
        RECT 108.750 5.040 108.920 6.230 ;
        RECT 109.615 5.510 109.960 5.750 ;
        RECT 109.600 5.105 111.615 5.275 ;
        RECT 108.750 5.020 108.990 5.040 ;
        RECT 104.630 4.745 107.275 4.915 ;
        RECT 107.015 4.660 107.210 4.745 ;
        RECT 107.465 4.725 108.015 4.930 ;
        RECT 108.710 4.935 108.990 5.020 ;
        RECT 109.600 5.010 109.775 5.105 ;
        RECT 107.465 4.670 107.765 4.725 ;
        RECT 108.185 4.680 108.530 4.920 ;
        RECT 108.710 4.705 109.230 4.935 ;
        RECT 109.525 4.810 109.775 5.010 ;
        RECT 111.335 5.070 111.615 5.105 ;
        RECT 107.465 4.655 107.700 4.670 ;
        RECT 98.650 4.075 99.065 4.105 ;
        RECT 98.335 4.025 99.065 4.075 ;
        RECT 97.590 3.910 99.065 4.025 ;
        RECT 97.590 3.905 99.040 3.910 ;
        RECT 97.590 3.855 98.530 3.905 ;
        RECT 99.265 3.670 99.490 3.915 ;
        RECT 100.390 3.680 100.590 3.815 ;
        RECT 90.110 3.445 90.310 3.455 ;
        RECT 97.240 3.430 98.435 3.605 ;
        RECT 99.265 3.485 100.005 3.670 ;
        RECT 99.595 3.435 100.005 3.485 ;
        RECT 100.260 3.455 100.590 3.680 ;
        RECT 107.150 3.495 107.345 3.835 ;
        RECT 107.520 3.605 107.700 4.655 ;
        RECT 108.710 4.655 108.920 4.705 ;
        RECT 108.710 4.445 108.880 4.655 ;
        RECT 107.870 4.275 108.880 4.445 ;
        RECT 109.525 4.280 109.735 4.810 ;
        RECT 109.960 4.765 110.335 4.935 ;
        RECT 111.335 4.865 112.150 5.070 ;
        RECT 109.995 4.475 110.180 4.765 ;
        RECT 109.165 4.105 109.735 4.280 ;
        RECT 109.920 4.270 110.330 4.475 ;
        RECT 110.580 4.415 110.755 4.755 ;
        RECT 113.100 4.745 114.200 4.920 ;
        RECT 114.910 4.915 116.010 4.920 ;
        RECT 117.295 4.915 117.490 5.000 ;
        RECT 118.125 4.930 118.295 6.230 ;
        RECT 119.030 5.040 119.200 6.230 ;
        RECT 119.895 5.510 120.240 5.750 ;
        RECT 119.880 5.105 121.895 5.275 ;
        RECT 119.030 5.020 119.270 5.040 ;
        RECT 114.910 4.745 117.555 4.915 ;
        RECT 117.295 4.660 117.490 4.745 ;
        RECT 117.745 4.725 118.295 4.930 ;
        RECT 118.990 4.935 119.270 5.020 ;
        RECT 119.880 5.010 120.055 5.105 ;
        RECT 117.745 4.670 118.045 4.725 ;
        RECT 118.465 4.680 118.810 4.920 ;
        RECT 118.990 4.705 119.510 4.935 ;
        RECT 119.805 4.810 120.055 5.010 ;
        RECT 121.615 5.070 121.895 5.105 ;
        RECT 117.745 4.655 117.980 4.670 ;
        RECT 108.930 4.075 109.345 4.105 ;
        RECT 108.615 4.025 109.345 4.075 ;
        RECT 107.870 3.910 109.345 4.025 ;
        RECT 107.870 3.905 109.320 3.910 ;
        RECT 107.870 3.855 108.810 3.905 ;
        RECT 109.545 3.670 109.770 3.915 ;
        RECT 110.670 3.680 110.870 3.815 ;
        RECT 100.390 3.445 100.590 3.455 ;
        RECT 107.520 3.430 108.715 3.605 ;
        RECT 109.545 3.485 110.285 3.670 ;
        RECT 109.875 3.435 110.285 3.485 ;
        RECT 110.540 3.455 110.870 3.680 ;
        RECT 117.430 3.495 117.625 3.835 ;
        RECT 117.800 3.605 117.980 4.655 ;
        RECT 118.990 4.655 119.200 4.705 ;
        RECT 118.990 4.445 119.160 4.655 ;
        RECT 118.150 4.275 119.160 4.445 ;
        RECT 119.805 4.280 120.015 4.810 ;
        RECT 120.240 4.765 120.615 4.935 ;
        RECT 121.615 4.865 122.430 5.070 ;
        RECT 127.575 4.920 127.770 5.000 ;
        RECT 128.405 4.930 128.575 6.230 ;
        RECT 129.310 5.040 129.480 6.230 ;
        RECT 130.175 5.510 130.520 5.750 ;
        RECT 130.160 5.105 132.175 5.275 ;
        RECT 129.310 5.020 129.550 5.040 ;
        RECT 120.275 4.475 120.460 4.765 ;
        RECT 119.445 4.105 120.015 4.280 ;
        RECT 120.200 4.270 120.610 4.475 ;
        RECT 120.860 4.415 121.035 4.755 ;
        RECT 123.380 4.745 124.480 4.920 ;
        RECT 125.190 4.750 127.840 4.920 ;
        RECT 125.190 4.745 126.290 4.750 ;
        RECT 127.575 4.660 127.770 4.750 ;
        RECT 128.025 4.725 128.575 4.930 ;
        RECT 129.270 4.935 129.550 5.020 ;
        RECT 130.160 5.010 130.335 5.105 ;
        RECT 128.025 4.670 128.325 4.725 ;
        RECT 128.745 4.680 129.090 4.920 ;
        RECT 129.270 4.705 129.790 4.935 ;
        RECT 130.085 4.810 130.335 5.010 ;
        RECT 131.895 5.070 132.175 5.105 ;
        RECT 128.025 4.655 128.260 4.670 ;
        RECT 119.210 4.075 119.625 4.105 ;
        RECT 118.895 4.025 119.625 4.075 ;
        RECT 118.150 3.910 119.625 4.025 ;
        RECT 118.150 3.905 119.600 3.910 ;
        RECT 118.150 3.855 119.090 3.905 ;
        RECT 119.825 3.670 120.050 3.915 ;
        RECT 120.950 3.680 121.150 3.815 ;
        RECT 110.670 3.445 110.870 3.455 ;
        RECT 117.800 3.430 118.995 3.605 ;
        RECT 119.825 3.485 120.565 3.670 ;
        RECT 120.155 3.435 120.565 3.485 ;
        RECT 120.820 3.455 121.150 3.680 ;
        RECT 127.710 3.495 127.905 3.835 ;
        RECT 128.080 3.605 128.260 4.655 ;
        RECT 129.270 4.655 129.480 4.705 ;
        RECT 129.270 4.445 129.440 4.655 ;
        RECT 128.430 4.275 129.440 4.445 ;
        RECT 130.085 4.280 130.295 4.810 ;
        RECT 130.520 4.765 130.895 4.935 ;
        RECT 131.895 4.865 132.710 5.070 ;
        RECT 130.555 4.475 130.740 4.765 ;
        RECT 129.725 4.105 130.295 4.280 ;
        RECT 130.480 4.270 130.890 4.475 ;
        RECT 131.140 4.415 131.315 4.755 ;
        RECT 133.660 4.745 134.760 4.920 ;
        RECT 135.470 4.745 136.570 4.920 ;
        RECT 129.490 4.075 129.905 4.105 ;
        RECT 129.175 4.025 129.905 4.075 ;
        RECT 128.430 3.910 129.905 4.025 ;
        RECT 128.430 3.905 129.880 3.910 ;
        RECT 128.430 3.855 129.370 3.905 ;
        RECT 130.105 3.670 130.330 3.915 ;
        RECT 131.230 3.680 131.430 3.815 ;
        RECT 120.950 3.445 121.150 3.455 ;
        RECT 128.080 3.430 129.275 3.605 ;
        RECT 130.105 3.485 130.845 3.670 ;
        RECT 130.435 3.435 130.845 3.485 ;
        RECT 131.100 3.455 131.430 3.680 ;
        RECT 131.230 3.445 131.430 3.455 ;
        RECT 137.860 3.430 138.630 6.230 ;
      LAYER met1 ;
        RECT 94.185 19.720 94.635 19.730 ;
        RECT 3.970 19.525 4.300 19.615 ;
        RECT 3.970 19.355 5.170 19.525 ;
        RECT 5.000 18.545 5.170 19.355 ;
        RECT 8.335 19.265 8.665 19.565 ;
        RECT 93.875 19.380 94.635 19.720 ;
        RECT 31.080 19.205 44.080 19.375 ;
        RECT 93.875 19.370 94.185 19.380 ;
        RECT 7.060 18.715 13.890 18.885 ;
        RECT 4.995 18.285 5.325 18.545 ;
        RECT 6.440 17.975 6.740 18.305 ;
        RECT 7.060 18.280 7.230 18.715 ;
        RECT 6.965 18.020 7.295 18.280 ;
        RECT 8.870 18.210 9.130 18.540 ;
        RECT 10.750 18.250 11.080 18.550 ;
        RECT 13.720 18.270 13.890 18.715 ;
        RECT 14.150 18.810 14.410 18.935 ;
        RECT 20.885 18.810 21.145 18.930 ;
        RECT 31.080 18.905 31.250 19.205 ;
        RECT 14.150 18.640 21.145 18.810 ;
        RECT 24.215 18.840 24.505 18.885 ;
        RECT 28.535 18.840 28.825 18.885 ;
        RECT 30.920 18.840 31.250 18.905 ;
        RECT 24.215 18.700 31.250 18.840 ;
        RECT 24.215 18.655 24.505 18.700 ;
        RECT 28.535 18.655 28.825 18.700 ;
        RECT 30.920 18.645 31.250 18.700 ;
        RECT 34.310 18.760 34.570 18.920 ;
        RECT 14.150 18.605 14.410 18.640 ;
        RECT 20.885 18.600 21.145 18.640 ;
        RECT 34.310 18.590 36.895 18.760 ;
        RECT 22.590 18.280 23.070 18.580 ;
        RECT 22.590 18.270 22.760 18.280 ;
        RECT 25.145 18.275 25.475 18.535 ;
        RECT 36.725 18.380 36.895 18.590 ;
        RECT 43.910 18.515 44.080 19.205 ;
        RECT 56.860 18.605 57.190 18.865 ;
        RECT 43.895 18.470 44.185 18.515 ;
        RECT 45.335 18.470 45.625 18.515 ;
        RECT 52.535 18.470 52.825 18.515 ;
        RECT 43.895 18.420 52.825 18.470 ;
        RECT 60.165 18.470 60.550 18.550 ;
        RECT 63.095 18.470 63.385 18.515 ;
        RECT 60.165 18.420 63.385 18.470 ;
        RECT 5.535 17.445 5.915 17.645 ;
        RECT 8.960 17.565 9.130 18.210 ;
        RECT 9.795 18.035 10.125 18.165 ;
        RECT 12.235 18.035 12.495 18.195 ;
        RECT 13.715 18.110 22.760 18.270 ;
        RECT 13.715 18.100 22.725 18.110 ;
        RECT 9.795 17.865 12.495 18.035 ;
        RECT 23.305 17.995 23.565 18.155 ;
        RECT 36.725 18.120 37.055 18.380 ;
        RECT 38.240 18.005 38.500 18.335 ;
        RECT 43.895 18.330 63.385 18.420 ;
        RECT 43.895 18.285 44.185 18.330 ;
        RECT 45.335 18.285 45.625 18.330 ;
        RECT 23.305 17.830 36.385 17.995 ;
        RECT 39.135 17.930 39.395 18.260 ;
        RECT 52.535 18.250 60.550 18.330 ;
        RECT 63.095 18.285 63.385 18.330 ;
        RECT 86.090 18.435 86.725 18.705 ;
        RECT 91.240 18.595 91.710 18.695 ;
        RECT 49.550 17.875 49.880 18.185 ;
        RECT 23.305 17.825 36.475 17.830 ;
        RECT 15.125 17.565 15.385 17.725 ;
        RECT 8.960 17.445 15.385 17.565 ;
        RECT 36.215 17.500 36.475 17.825 ;
        RECT 5.535 17.395 15.385 17.445 ;
        RECT 5.535 17.275 9.240 17.395 ;
        RECT 86.090 16.130 86.260 18.435 ;
        RECT 91.240 18.425 91.925 18.595 ;
        RECT 88.310 18.255 88.575 18.290 ;
        RECT 86.540 18.040 88.575 18.255 ;
        RECT 86.540 16.985 86.710 18.040 ;
        RECT 88.310 18.010 88.575 18.040 ;
        RECT 89.445 18.000 89.715 18.300 ;
        RECT 89.540 17.755 89.715 18.000 ;
        RECT 89.540 17.585 91.245 17.755 ;
        RECT 86.415 16.665 86.710 16.985 ;
        RECT 91.075 16.935 91.245 17.585 ;
        RECT 91.075 16.765 91.570 16.935 ;
        RECT 91.275 16.615 91.570 16.765 ;
        RECT 88.145 16.130 88.445 16.200 ;
        RECT 86.090 15.960 88.445 16.130 ;
        RECT 89.525 16.130 89.830 16.200 ;
        RECT 91.755 16.130 91.925 18.425 ;
        RECT 95.515 16.380 95.865 17.140 ;
        RECT 89.525 15.960 91.925 16.130 ;
        RECT 93.690 15.715 94.185 16.255 ;
        RECT 13.425 15.020 24.385 15.190 ;
        RECT 42.475 15.065 42.735 15.395 ;
        RECT 5.075 14.780 11.610 14.950 ;
        RECT 13.425 14.780 13.595 15.020 ;
        RECT 5.075 14.630 5.245 14.780 ;
        RECT 2.760 14.495 5.245 14.630 ;
        RECT 2.755 14.460 5.245 14.495 ;
        RECT 2.755 14.165 2.925 14.460 ;
        RECT 5.980 14.260 6.310 14.560 ;
        RECT 11.440 14.410 11.820 14.780 ;
        RECT 13.215 14.410 13.595 14.780 ;
        RECT 14.150 14.565 14.410 14.660 ;
        RECT 20.885 14.565 21.145 14.660 ;
        RECT 14.150 14.395 21.145 14.565 ;
        RECT 14.150 14.330 14.410 14.395 ;
        RECT 20.885 14.330 21.145 14.395 ;
        RECT 24.215 14.610 24.385 15.020 ;
        RECT 34.310 14.830 34.570 14.905 ;
        RECT 34.310 14.660 41.200 14.830 ;
        RECT 55.480 14.740 55.740 15.070 ;
        RECT 62.155 14.945 62.385 15.055 ;
        RECT 62.155 14.775 62.825 14.945 ;
        RECT 62.155 14.765 62.385 14.775 ;
        RECT 24.215 14.565 24.505 14.610 ;
        RECT 28.535 14.565 28.825 14.610 ;
        RECT 30.920 14.565 31.250 14.620 ;
        RECT 34.310 14.575 34.570 14.660 ;
        RECT 24.215 14.425 31.250 14.565 ;
        RECT 24.215 14.380 24.505 14.425 ;
        RECT 28.535 14.380 28.825 14.425 ;
        RECT 30.920 14.360 31.250 14.425 ;
        RECT 2.670 13.835 2.930 14.165 ;
        RECT 4.030 13.605 4.360 13.905 ;
        RECT 5.000 13.755 5.260 14.085 ;
        RECT 8.845 13.970 9.175 14.270 ;
        RECT 10.750 13.970 11.080 14.270 ;
        RECT 22.740 13.980 23.070 14.280 ;
        RECT 25.145 13.980 25.475 14.280 ;
        RECT 3.590 13.305 3.850 13.445 ;
        RECT 5.000 13.305 5.170 13.755 ;
        RECT 6.450 13.610 6.710 13.940 ;
        RECT 12.235 13.765 12.495 13.920 ;
        RECT 8.945 13.670 12.495 13.765 ;
        RECT 6.540 13.365 6.710 13.610 ;
        RECT 8.855 13.595 12.495 13.670 ;
        RECT 3.590 13.135 5.170 13.305 ;
        RECT 6.475 13.160 6.855 13.365 ;
        RECT 8.855 13.340 9.115 13.595 ;
        RECT 12.235 13.590 12.495 13.595 ;
        RECT 23.305 13.760 23.565 13.920 ;
        RECT 23.305 13.590 35.490 13.760 ;
        RECT 36.160 13.755 36.420 14.085 ;
        RECT 38.605 13.860 38.935 14.120 ;
        RECT 41.030 14.035 41.200 14.660 ;
        RECT 44.855 14.565 45.145 14.610 ;
        RECT 49.175 14.565 49.465 14.610 ;
        RECT 51.540 14.565 51.870 14.620 ;
        RECT 44.855 14.425 51.870 14.565 ;
        RECT 44.855 14.380 45.145 14.425 ;
        RECT 49.175 14.380 49.465 14.425 ;
        RECT 51.540 14.360 51.870 14.425 ;
        RECT 54.915 14.365 55.175 14.695 ;
        RECT 35.160 13.390 35.490 13.590 ;
        RECT 38.605 13.540 38.775 13.860 ;
        RECT 40.975 13.705 41.235 14.035 ;
        RECT 41.635 13.950 41.965 14.210 ;
        RECT 42.430 13.765 42.760 14.025 ;
        RECT 45.815 13.795 46.145 14.115 ;
        RECT 36.280 13.370 38.775 13.540 ;
        RECT 15.125 13.160 15.385 13.325 ;
        RECT 3.590 13.115 3.850 13.135 ;
        RECT 6.475 12.995 15.385 13.160 ;
        RECT 36.280 13.135 36.450 13.370 ;
        RECT 42.505 13.340 42.675 13.765 ;
        RECT 55.480 13.750 55.740 14.080 ;
        RECT 56.335 13.750 56.595 14.080 ;
        RECT 57.710 13.750 57.970 14.080 ;
        RECT 58.715 13.750 58.975 14.080 ;
        RECT 61.195 13.965 61.455 14.295 ;
        RECT 62.655 14.275 62.825 14.775 ;
        RECT 63.545 14.635 63.775 14.735 ;
        RECT 65.005 14.640 65.285 14.695 ;
        RECT 63.305 14.445 63.775 14.635 ;
        RECT 64.535 14.470 66.635 14.640 ;
        RECT 62.170 13.985 62.400 14.275 ;
        RECT 62.650 13.985 62.880 14.275 ;
        RECT 62.225 13.840 62.395 13.985 ;
        RECT 63.305 13.840 63.475 14.445 ;
        RECT 63.625 13.985 63.855 14.275 ;
        RECT 62.225 13.670 63.475 13.840 ;
        RECT 63.685 13.840 63.855 13.985 ;
        RECT 64.535 13.840 64.705 14.470 ;
        RECT 65.005 14.425 65.285 14.470 ;
        RECT 66.465 14.270 66.635 14.470 ;
        RECT 63.685 13.670 64.705 13.840 ;
        RECT 65.560 13.760 65.790 14.050 ;
        RECT 66.435 13.980 66.665 14.270 ;
        RECT 96.610 13.970 96.750 19.185 ;
        RECT 97.170 13.970 97.310 19.185 ;
        RECT 97.730 13.970 97.870 19.185 ;
        RECT 98.290 13.970 98.430 19.185 ;
        RECT 98.850 13.970 98.990 19.185 ;
        RECT 99.410 13.970 99.550 19.185 ;
        RECT 99.970 13.970 100.110 19.185 ;
        RECT 100.530 13.970 100.670 19.185 ;
        RECT 101.090 13.970 101.230 19.185 ;
        RECT 101.680 13.970 101.950 19.185 ;
        RECT 102.400 13.970 102.540 19.185 ;
        RECT 102.960 13.970 103.100 19.185 ;
        RECT 103.520 13.970 103.660 19.185 ;
        RECT 104.080 13.970 104.220 19.185 ;
        RECT 104.640 13.970 104.780 19.185 ;
        RECT 105.200 13.970 105.340 19.185 ;
        RECT 105.760 13.970 105.900 19.185 ;
        RECT 106.320 13.970 106.460 19.185 ;
        RECT 106.880 13.970 107.020 19.185 ;
        RECT 63.305 13.465 63.475 13.670 ;
        RECT 65.560 13.465 65.730 13.760 ;
        RECT 6.540 12.990 15.295 12.995 ;
        RECT 34.250 12.965 36.450 13.135 ;
        RECT 36.990 13.115 37.320 13.150 ;
        RECT 38.605 13.115 38.935 13.150 ;
        RECT 34.250 12.875 34.580 12.965 ;
        RECT 36.990 12.945 38.935 13.115 ;
        RECT 42.425 13.080 42.755 13.340 ;
        RECT 63.305 13.295 65.730 13.465 ;
        RECT 96.610 13.650 107.020 13.970 ;
        RECT 36.990 12.890 37.320 12.945 ;
        RECT 38.605 12.890 38.935 12.945 ;
        RECT 60.705 12.860 60.965 13.190 ;
        RECT 38.960 11.025 39.290 11.030 ;
        RECT 4.260 10.685 4.590 10.985 ;
        RECT 38.960 10.855 43.175 11.025 ;
        RECT 38.960 10.770 39.290 10.855 ;
        RECT 42.845 10.765 43.175 10.855 ;
        RECT 3.685 10.300 5.180 10.470 ;
        RECT 3.685 10.030 3.855 10.300 ;
        RECT 5.010 10.040 5.180 10.300 ;
        RECT 5.935 10.455 6.265 10.545 ;
        RECT 5.935 10.285 7.825 10.455 ;
        RECT 57.820 10.440 58.080 10.770 ;
        RECT 62.155 10.680 62.385 10.790 ;
        RECT 62.155 10.510 62.825 10.680 ;
        RECT 62.155 10.500 62.385 10.510 ;
        RECT 2.175 9.415 2.505 9.715 ;
        RECT 3.105 9.700 3.365 10.030 ;
        RECT 3.595 9.700 3.855 10.030 ;
        RECT 4.095 9.700 4.355 10.030 ;
        RECT 5.010 9.740 5.340 10.040 ;
        RECT 5.950 9.740 6.280 10.040 ;
        RECT 7.655 9.905 7.825 10.285 ;
        RECT 14.150 10.310 14.410 10.395 ;
        RECT 20.885 10.310 21.145 10.400 ;
        RECT 14.150 10.140 21.145 10.310 ;
        RECT 14.150 10.065 14.410 10.140 ;
        RECT 20.885 10.070 21.145 10.140 ;
        RECT 24.215 10.300 24.505 10.345 ;
        RECT 28.535 10.300 28.825 10.345 ;
        RECT 30.920 10.300 31.250 10.360 ;
        RECT 53.035 10.345 53.365 10.375 ;
        RECT 24.215 10.160 31.250 10.300 ;
        RECT 42.955 10.270 43.215 10.325 ;
        RECT 43.420 10.270 43.680 10.340 ;
        RECT 42.955 10.165 43.680 10.270 ;
        RECT 24.215 10.115 24.505 10.160 ;
        RECT 28.535 10.115 28.825 10.160 ;
        RECT 30.920 10.100 31.250 10.160 ;
        RECT 36.250 10.070 43.680 10.165 ;
        RECT 46.295 10.300 46.585 10.345 ;
        RECT 48.695 10.300 48.985 10.345 ;
        RECT 53.015 10.300 53.365 10.345 ;
        RECT 46.295 10.160 53.365 10.300 ;
        RECT 46.295 10.115 46.585 10.160 ;
        RECT 48.695 10.115 48.985 10.160 ;
        RECT 53.015 10.115 53.365 10.160 ;
        RECT 53.850 10.095 54.110 10.425 ;
        RECT 54.470 10.115 54.800 10.375 ;
        RECT 3.190 8.875 3.360 9.700 ;
        RECT 4.185 9.330 4.355 9.700 ;
        RECT 5.950 9.330 6.120 9.740 ;
        RECT 4.185 9.160 6.120 9.330 ;
        RECT 6.495 9.300 6.755 9.655 ;
        RECT 7.655 9.575 7.915 9.905 ;
        RECT 10.750 9.700 11.080 10.000 ;
        RECT 36.250 9.995 43.215 10.070 ;
        RECT 43.420 10.010 43.680 10.070 ;
        RECT 12.235 9.490 12.495 9.650 ;
        RECT 22.740 9.590 23.070 9.890 ;
        RECT 25.145 9.705 25.475 9.965 ;
        RECT 36.250 9.840 36.420 9.995 ;
        RECT 8.945 9.320 12.495 9.490 ;
        RECT 23.305 9.490 23.565 9.650 ;
        RECT 36.160 9.510 36.420 9.840 ;
        RECT 23.305 9.320 35.490 9.490 ;
        RECT 38.605 9.365 38.935 9.780 ;
        RECT 40.975 9.480 41.235 9.810 ;
        RECT 52.025 9.665 52.355 9.985 ;
        RECT 59.260 9.960 59.520 10.290 ;
        RECT 55.370 9.595 55.700 9.855 ;
        RECT 56.910 9.535 57.170 9.865 ;
        RECT 58.670 9.525 58.930 9.855 ;
        RECT 6.540 8.875 6.710 9.300 ;
        RECT 8.945 9.070 9.205 9.320 ;
        RECT 35.160 9.090 35.490 9.320 ;
        RECT 36.280 9.235 38.935 9.365 ;
        RECT 42.345 9.235 42.675 9.240 ;
        RECT 36.280 9.195 42.675 9.235 ;
        RECT 15.125 8.875 15.385 9.035 ;
        RECT 3.190 8.705 15.385 8.875 ;
        RECT 34.250 8.930 34.580 8.970 ;
        RECT 36.280 8.930 36.450 9.195 ;
        RECT 38.715 9.065 42.675 9.195 ;
        RECT 42.345 8.980 42.675 9.065 ;
        RECT 58.735 9.225 58.905 9.525 ;
        RECT 60.235 9.380 60.495 9.710 ;
        RECT 61.195 9.700 61.455 10.030 ;
        RECT 62.655 10.010 62.825 10.510 ;
        RECT 63.545 10.370 63.775 10.470 ;
        RECT 65.005 10.375 65.285 10.430 ;
        RECT 63.305 10.180 63.775 10.370 ;
        RECT 64.535 10.205 66.635 10.375 ;
        RECT 62.170 9.720 62.400 10.010 ;
        RECT 62.650 9.720 62.880 10.010 ;
        RECT 62.225 9.575 62.395 9.720 ;
        RECT 63.305 9.575 63.475 10.180 ;
        RECT 63.625 9.720 63.855 10.010 ;
        RECT 62.225 9.405 63.475 9.575 ;
        RECT 63.685 9.575 63.855 9.720 ;
        RECT 64.535 9.575 64.705 10.205 ;
        RECT 65.005 10.160 65.285 10.205 ;
        RECT 64.895 9.975 65.340 10.010 ;
        RECT 66.465 10.005 66.635 10.205 ;
        RECT 64.885 9.745 65.340 9.975 ;
        RECT 64.895 9.705 65.340 9.745 ;
        RECT 63.685 9.405 64.705 9.575 ;
        RECT 65.560 9.495 65.790 9.785 ;
        RECT 66.435 9.715 66.665 10.005 ;
        RECT 60.235 9.225 60.405 9.380 ;
        RECT 58.735 9.055 60.405 9.225 ;
        RECT 63.305 9.200 63.475 9.405 ;
        RECT 65.560 9.200 65.730 9.495 ;
        RECT 63.305 9.030 65.730 9.200 ;
        RECT 93.650 9.145 94.050 9.550 ;
        RECT 34.250 8.760 36.450 8.930 ;
        RECT 36.990 8.845 37.320 8.880 ;
        RECT 38.605 8.845 38.935 8.880 ;
        RECT 34.250 8.710 34.580 8.760 ;
        RECT 36.990 8.675 38.935 8.845 ;
        RECT 36.990 8.620 37.320 8.675 ;
        RECT 38.605 8.620 38.935 8.675 ;
        RECT 56.305 8.640 56.635 8.900 ;
        RECT 96.610 8.435 96.750 13.650 ;
        RECT 97.170 8.435 97.310 13.650 ;
        RECT 97.730 8.435 97.870 13.650 ;
        RECT 98.290 8.435 98.430 13.650 ;
        RECT 98.850 8.435 98.990 13.650 ;
        RECT 99.410 8.435 99.550 13.650 ;
        RECT 99.970 8.435 100.110 13.650 ;
        RECT 100.530 8.435 100.670 13.650 ;
        RECT 101.090 8.435 101.230 13.650 ;
        RECT 101.680 8.435 101.950 13.650 ;
        RECT 102.400 8.435 102.540 13.650 ;
        RECT 102.960 8.435 103.100 13.650 ;
        RECT 103.520 8.435 103.660 13.650 ;
        RECT 104.080 8.435 104.220 13.650 ;
        RECT 104.640 8.435 104.780 13.650 ;
        RECT 105.200 8.435 105.340 13.650 ;
        RECT 105.760 8.435 105.900 13.650 ;
        RECT 106.320 8.435 106.460 13.650 ;
        RECT 106.880 8.435 107.020 13.650 ;
        RECT 108.835 13.970 108.975 19.185 ;
        RECT 109.395 13.970 109.535 19.185 ;
        RECT 109.955 13.970 110.095 19.185 ;
        RECT 110.515 13.970 110.655 19.185 ;
        RECT 111.075 13.970 111.215 19.185 ;
        RECT 111.635 13.970 111.775 19.185 ;
        RECT 112.195 13.970 112.335 19.185 ;
        RECT 112.755 13.970 112.895 19.185 ;
        RECT 113.315 13.970 113.455 19.185 ;
        RECT 113.905 13.970 114.175 19.185 ;
        RECT 114.625 13.970 114.765 19.185 ;
        RECT 115.185 13.970 115.325 19.185 ;
        RECT 115.745 13.970 115.885 19.185 ;
        RECT 116.305 13.970 116.445 19.185 ;
        RECT 116.865 13.970 117.005 19.185 ;
        RECT 117.425 13.970 117.565 19.185 ;
        RECT 117.985 13.970 118.125 19.185 ;
        RECT 118.545 13.970 118.685 19.185 ;
        RECT 119.105 13.970 119.245 19.185 ;
        RECT 108.835 13.650 119.245 13.970 ;
        RECT 108.835 8.435 108.975 13.650 ;
        RECT 109.395 8.435 109.535 13.650 ;
        RECT 109.955 8.435 110.095 13.650 ;
        RECT 110.515 8.435 110.655 13.650 ;
        RECT 111.075 8.435 111.215 13.650 ;
        RECT 111.635 8.435 111.775 13.650 ;
        RECT 112.195 8.435 112.335 13.650 ;
        RECT 112.755 8.435 112.895 13.650 ;
        RECT 113.315 8.435 113.455 13.650 ;
        RECT 113.905 8.435 114.175 13.650 ;
        RECT 114.625 8.435 114.765 13.650 ;
        RECT 115.185 8.435 115.325 13.650 ;
        RECT 115.745 8.435 115.885 13.650 ;
        RECT 116.305 8.435 116.445 13.650 ;
        RECT 116.865 8.435 117.005 13.650 ;
        RECT 117.425 8.435 117.565 13.650 ;
        RECT 117.985 8.435 118.125 13.650 ;
        RECT 118.545 8.435 118.685 13.650 ;
        RECT 119.105 8.435 119.245 13.650 ;
        RECT 121.100 13.970 121.240 19.185 ;
        RECT 121.660 13.970 121.800 19.185 ;
        RECT 122.220 13.970 122.360 19.185 ;
        RECT 122.780 13.970 122.920 19.185 ;
        RECT 123.340 13.970 123.480 19.185 ;
        RECT 123.900 13.970 124.040 19.185 ;
        RECT 124.460 13.970 124.600 19.185 ;
        RECT 125.020 13.970 125.160 19.185 ;
        RECT 125.580 13.970 125.720 19.185 ;
        RECT 126.170 13.970 126.440 19.185 ;
        RECT 126.890 13.970 127.030 19.185 ;
        RECT 127.450 13.970 127.590 19.185 ;
        RECT 128.010 13.970 128.150 19.185 ;
        RECT 128.570 13.970 128.710 19.185 ;
        RECT 129.130 13.970 129.270 19.185 ;
        RECT 129.690 13.970 129.830 19.185 ;
        RECT 130.250 13.970 130.390 19.185 ;
        RECT 130.810 13.970 130.950 19.185 ;
        RECT 131.370 13.970 131.510 19.185 ;
        RECT 121.100 13.650 131.510 13.970 ;
        RECT 121.100 8.435 121.240 13.650 ;
        RECT 121.660 8.435 121.800 13.650 ;
        RECT 122.220 8.435 122.360 13.650 ;
        RECT 122.780 8.435 122.920 13.650 ;
        RECT 123.340 8.435 123.480 13.650 ;
        RECT 123.900 8.435 124.040 13.650 ;
        RECT 124.460 8.435 124.600 13.650 ;
        RECT 125.020 8.435 125.160 13.650 ;
        RECT 125.580 8.435 125.720 13.650 ;
        RECT 126.170 8.435 126.440 13.650 ;
        RECT 126.890 8.435 127.030 13.650 ;
        RECT 127.450 8.435 127.590 13.650 ;
        RECT 128.010 8.435 128.150 13.650 ;
        RECT 128.570 8.435 128.710 13.650 ;
        RECT 129.130 8.435 129.270 13.650 ;
        RECT 129.690 8.435 129.830 13.650 ;
        RECT 130.250 8.435 130.390 13.650 ;
        RECT 130.810 8.435 130.950 13.650 ;
        RECT 131.370 8.435 131.510 13.650 ;
        RECT 133.350 13.970 133.490 19.185 ;
        RECT 133.910 13.970 134.050 19.185 ;
        RECT 134.470 13.970 134.610 19.185 ;
        RECT 135.030 13.970 135.170 19.185 ;
        RECT 135.590 13.970 135.730 19.185 ;
        RECT 136.150 13.970 136.290 19.185 ;
        RECT 136.710 13.970 136.850 19.185 ;
        RECT 137.270 13.970 137.410 19.185 ;
        RECT 137.830 13.970 137.970 19.185 ;
        RECT 138.420 13.970 138.690 19.185 ;
        RECT 139.140 13.970 139.280 19.185 ;
        RECT 139.700 13.970 139.840 19.185 ;
        RECT 140.260 13.970 140.400 19.185 ;
        RECT 140.820 13.970 140.960 19.185 ;
        RECT 141.380 13.970 141.520 19.185 ;
        RECT 141.940 13.970 142.080 19.185 ;
        RECT 142.500 13.970 142.640 19.185 ;
        RECT 143.060 13.970 143.200 19.185 ;
        RECT 143.620 13.970 143.760 19.185 ;
        RECT 133.350 13.650 143.760 13.970 ;
        RECT 133.350 8.435 133.490 13.650 ;
        RECT 133.910 8.435 134.050 13.650 ;
        RECT 134.470 8.435 134.610 13.650 ;
        RECT 135.030 8.435 135.170 13.650 ;
        RECT 135.590 8.435 135.730 13.650 ;
        RECT 136.150 8.435 136.290 13.650 ;
        RECT 136.710 8.435 136.850 13.650 ;
        RECT 137.270 8.435 137.410 13.650 ;
        RECT 137.830 8.435 137.970 13.650 ;
        RECT 138.420 8.435 138.690 13.650 ;
        RECT 139.140 8.435 139.280 13.650 ;
        RECT 139.700 8.435 139.840 13.650 ;
        RECT 140.260 8.435 140.400 13.650 ;
        RECT 140.820 8.435 140.960 13.650 ;
        RECT 141.380 8.435 141.520 13.650 ;
        RECT 141.940 8.435 142.080 13.650 ;
        RECT 142.500 8.435 142.640 13.650 ;
        RECT 143.060 8.435 143.200 13.650 ;
        RECT 143.620 8.435 143.760 13.650 ;
        RECT 145.105 7.045 145.510 7.765 ;
        RECT 43.370 6.770 43.630 6.865 ;
        RECT 44.395 6.770 44.655 6.865 ;
        RECT 43.370 6.600 44.655 6.770 ;
        RECT 43.370 6.535 43.630 6.600 ;
        RECT 44.395 6.535 44.655 6.600 ;
        RECT 47.260 6.245 47.520 6.575 ;
        RECT 51.590 6.250 51.920 6.510 ;
        RECT 5.960 6.155 6.290 6.245 ;
        RECT 5.960 6.040 8.475 6.155 ;
        RECT 5.960 5.985 8.480 6.040 ;
        RECT 4.515 5.440 4.845 5.740 ;
        RECT 5.390 5.440 5.720 5.740 ;
        RECT 5.945 5.440 6.275 5.740 ;
        RECT 8.310 5.585 8.480 5.985 ;
        RECT 14.150 6.025 14.410 6.125 ;
        RECT 20.885 6.025 21.145 6.125 ;
        RECT 14.150 5.855 21.145 6.025 ;
        RECT 14.150 5.795 14.410 5.855 ;
        RECT 20.885 5.795 21.145 5.855 ;
        RECT 24.215 6.030 24.505 6.075 ;
        RECT 28.535 6.030 28.825 6.075 ;
        RECT 30.920 6.030 31.250 6.090 ;
        RECT 24.215 5.890 31.250 6.030 ;
        RECT 24.215 5.845 24.505 5.890 ;
        RECT 28.535 5.845 28.825 5.890 ;
        RECT 30.920 5.830 31.250 5.890 ;
        RECT 34.250 5.960 34.580 6.050 ;
        RECT 44.370 6.015 44.700 6.100 ;
        RECT 34.250 5.790 38.775 5.960 ;
        RECT 6.475 5.110 6.805 5.410 ;
        RECT 8.265 5.325 8.595 5.585 ;
        RECT 10.750 5.440 11.080 5.740 ;
        RECT 22.740 5.400 23.070 5.700 ;
        RECT 25.145 5.465 25.475 5.725 ;
        RECT 38.605 5.670 38.775 5.790 ;
        RECT 41.010 5.845 44.700 6.015 ;
        RECT 38.605 5.580 38.935 5.670 ;
        RECT 12.235 5.230 12.495 5.385 ;
        RECT 6.540 4.610 6.710 5.110 ;
        RECT 8.855 5.060 12.495 5.230 ;
        RECT 8.855 4.820 9.115 5.060 ;
        RECT 12.235 5.055 12.495 5.060 ;
        RECT 23.305 5.215 23.565 5.375 ;
        RECT 23.305 5.045 35.490 5.215 ;
        RECT 36.160 5.205 36.420 5.535 ;
        RECT 38.605 5.410 39.505 5.580 ;
        RECT 41.010 5.510 41.180 5.845 ;
        RECT 44.370 5.840 44.700 5.845 ;
        RECT 78.095 6.010 78.415 6.085 ;
        RECT 35.160 4.815 35.490 5.045 ;
        RECT 39.335 4.990 39.505 5.410 ;
        RECT 40.850 5.250 41.180 5.510 ;
        RECT 42.560 5.525 45.660 5.695 ;
        RECT 54.935 5.660 55.225 5.705 ;
        RECT 57.800 5.660 58.120 5.735 ;
        RECT 78.095 5.690 78.430 6.010 ;
        RECT 42.560 5.385 42.730 5.525 ;
        RECT 41.990 5.055 42.250 5.385 ;
        RECT 42.465 5.055 42.730 5.385 ;
        RECT 43.425 5.055 43.685 5.385 ;
        RECT 43.905 5.065 44.175 5.385 ;
        RECT 45.330 5.355 45.660 5.525 ;
        RECT 45.950 5.565 46.280 5.615 ;
        RECT 48.170 5.565 48.500 5.615 ;
        RECT 45.950 5.395 48.500 5.565 ;
        RECT 54.935 5.520 58.120 5.660 ;
        RECT 54.935 5.475 55.225 5.520 ;
        RECT 57.800 5.445 58.120 5.520 ;
        RECT 45.950 5.355 46.280 5.395 ;
        RECT 48.170 5.355 48.500 5.395 ;
        RECT 45.950 5.065 46.120 5.355 ;
        RECT 61.755 5.140 62.210 5.445 ;
        RECT 64.660 5.325 64.980 5.390 ;
        RECT 68.025 5.325 68.425 5.495 ;
        RECT 78.095 5.345 78.415 5.505 ;
        RECT 64.660 5.140 68.425 5.325 ;
        RECT 64.660 5.065 64.980 5.140 ;
        RECT 43.905 5.055 46.120 5.065 ;
        RECT 41.990 4.990 42.160 5.055 ;
        RECT 39.335 4.820 42.160 4.990 ;
        RECT 15.125 4.610 15.385 4.770 ;
        RECT 6.540 4.440 15.385 4.610 ;
        RECT 36.990 4.605 37.320 4.640 ;
        RECT 38.605 4.605 38.935 4.640 ;
        RECT 36.990 4.435 38.935 4.605 ;
        RECT 43.515 4.610 43.685 5.055 ;
        RECT 43.990 4.895 46.120 5.055 ;
        RECT 68.020 5.035 68.425 5.140 ;
        RECT 73.935 4.955 74.335 5.300 ;
        RECT 78.090 5.205 78.415 5.345 ;
        RECT 73.980 4.940 74.300 4.955 ;
        RECT 43.515 4.520 46.120 4.610 ;
        RECT 48.680 4.520 49.010 4.625 ;
        RECT 43.515 4.440 49.010 4.520 ;
        RECT 36.990 4.380 37.320 4.435 ;
        RECT 38.605 4.380 38.935 4.435 ;
        RECT 45.790 4.365 49.010 4.440 ;
        RECT 45.790 4.350 48.790 4.365 ;
        RECT 63.995 4.355 64.450 4.660 ;
        RECT 78.090 4.485 78.410 5.205 ;
        RECT 86.470 5.025 86.790 5.445 ;
        RECT 89.010 5.205 89.400 5.785 ;
        RECT 89.010 5.135 89.310 5.205 ;
        RECT 91.765 5.150 94.450 5.320 ;
        RECT 86.470 4.765 86.640 5.025 ;
        RECT 89.370 4.970 89.730 4.995 ;
        RECT 91.765 4.970 91.935 5.150 ;
        RECT 94.280 5.005 94.450 5.150 ;
        RECT 99.290 5.205 99.680 5.785 ;
        RECT 99.290 5.135 99.590 5.205 ;
        RECT 102.045 5.150 104.730 5.320 ;
        RECT 86.905 4.640 87.225 4.940 ;
        RECT 87.610 4.640 87.970 4.940 ;
        RECT 88.335 4.800 91.935 4.970 ;
        RECT 88.335 4.640 88.655 4.800 ;
        RECT 89.370 4.725 89.730 4.800 ;
        RECT 87.055 4.500 87.225 4.640 ;
        RECT 89.960 4.500 90.275 4.655 ;
        RECT 92.495 4.555 93.700 5.005 ;
        RECT 94.280 4.555 95.485 5.005 ;
        RECT 99.650 4.970 100.010 4.995 ;
        RECT 102.045 4.970 102.215 5.150 ;
        RECT 104.560 5.005 104.730 5.150 ;
        RECT 109.570 5.205 109.960 5.785 ;
        RECT 109.570 5.135 109.870 5.205 ;
        RECT 112.325 5.150 115.010 5.320 ;
        RECT 97.185 4.640 97.505 4.940 ;
        RECT 97.890 4.640 98.250 4.940 ;
        RECT 98.615 4.800 102.215 4.970 ;
        RECT 98.615 4.640 98.935 4.800 ;
        RECT 99.650 4.725 100.010 4.800 ;
        RECT 92.495 4.500 92.665 4.555 ;
        RECT 87.055 4.330 92.665 4.500 ;
        RECT 93.505 4.410 93.700 4.555 ;
        RECT 97.335 4.500 97.505 4.640 ;
        RECT 100.240 4.500 100.555 4.655 ;
        RECT 102.775 4.555 103.980 5.005 ;
        RECT 104.560 4.555 105.765 5.005 ;
        RECT 109.930 4.970 110.290 4.995 ;
        RECT 112.325 4.970 112.495 5.150 ;
        RECT 114.840 5.005 115.010 5.150 ;
        RECT 119.850 5.205 120.240 5.785 ;
        RECT 119.850 5.135 120.150 5.205 ;
        RECT 122.605 5.150 125.290 5.320 ;
        RECT 107.465 4.640 107.785 4.940 ;
        RECT 108.170 4.640 108.530 4.940 ;
        RECT 108.895 4.800 112.495 4.970 ;
        RECT 108.895 4.640 109.215 4.800 ;
        RECT 109.930 4.725 110.290 4.800 ;
        RECT 102.775 4.500 102.945 4.555 ;
        RECT 83.075 3.860 83.395 3.910 ;
        RECT 83.035 3.570 83.395 3.860 ;
        RECT 85.125 3.585 85.535 3.885 ;
        RECT 86.535 3.585 86.855 3.985 ;
        RECT 89.455 3.925 89.625 4.330 ;
        RECT 93.505 4.240 96.985 4.410 ;
        RECT 97.335 4.330 102.945 4.500 ;
        RECT 103.775 4.410 103.970 4.555 ;
        RECT 107.615 4.500 107.785 4.640 ;
        RECT 110.520 4.500 110.835 4.655 ;
        RECT 113.055 4.555 114.260 5.005 ;
        RECT 114.840 4.555 116.045 5.005 ;
        RECT 120.210 4.970 120.570 4.995 ;
        RECT 122.605 4.970 122.775 5.150 ;
        RECT 125.120 5.005 125.290 5.150 ;
        RECT 130.130 5.205 130.520 5.785 ;
        RECT 138.005 5.355 138.490 5.940 ;
        RECT 130.130 5.135 130.430 5.205 ;
        RECT 132.885 5.150 135.570 5.320 ;
        RECT 117.745 4.640 118.065 4.940 ;
        RECT 118.450 4.640 118.810 4.940 ;
        RECT 119.175 4.800 122.775 4.970 ;
        RECT 119.175 4.640 119.495 4.800 ;
        RECT 120.210 4.725 120.570 4.800 ;
        RECT 113.055 4.500 113.225 4.555 ;
        RECT 88.915 3.755 89.630 3.925 ;
        RECT 96.815 3.885 96.985 4.240 ;
        RECT 99.735 3.925 99.905 4.330 ;
        RECT 103.775 4.240 107.265 4.410 ;
        RECT 107.615 4.330 113.225 4.500 ;
        RECT 114.060 4.410 114.255 4.555 ;
        RECT 117.895 4.500 118.065 4.640 ;
        RECT 120.800 4.500 121.115 4.655 ;
        RECT 123.335 4.555 124.540 5.005 ;
        RECT 125.120 4.555 126.325 5.005 ;
        RECT 130.490 4.970 130.850 4.995 ;
        RECT 132.885 4.970 133.055 5.150 ;
        RECT 135.400 5.005 135.570 5.150 ;
        RECT 128.025 4.640 128.345 4.940 ;
        RECT 128.730 4.640 129.090 4.940 ;
        RECT 129.455 4.800 133.055 4.970 ;
        RECT 129.455 4.640 129.775 4.800 ;
        RECT 130.490 4.725 130.850 4.800 ;
        RECT 123.335 4.500 123.505 4.555 ;
        RECT 88.915 3.615 89.265 3.755 ;
        RECT 90.045 3.575 90.395 3.885 ;
        RECT 96.815 3.585 97.135 3.885 ;
        RECT 99.195 3.755 99.910 3.925 ;
        RECT 107.095 3.885 107.265 4.240 ;
        RECT 110.015 3.925 110.185 4.330 ;
        RECT 114.060 4.240 117.545 4.410 ;
        RECT 117.895 4.330 123.505 4.500 ;
        RECT 124.335 4.410 124.530 4.555 ;
        RECT 128.175 4.500 128.345 4.640 ;
        RECT 131.080 4.500 131.395 4.655 ;
        RECT 133.615 4.555 134.820 5.005 ;
        RECT 135.400 4.555 136.605 5.005 ;
        RECT 133.615 4.500 133.785 4.555 ;
        RECT 99.195 3.615 99.545 3.755 ;
        RECT 100.325 3.575 100.675 3.885 ;
        RECT 107.095 3.585 107.415 3.885 ;
        RECT 109.475 3.755 110.190 3.925 ;
        RECT 117.375 3.885 117.545 4.240 ;
        RECT 120.295 3.925 120.465 4.330 ;
        RECT 124.335 4.240 127.825 4.410 ;
        RECT 128.175 4.330 133.785 4.500 ;
        RECT 109.475 3.615 109.825 3.755 ;
        RECT 110.605 3.575 110.955 3.885 ;
        RECT 117.375 3.585 117.695 3.885 ;
        RECT 119.755 3.755 120.470 3.925 ;
        RECT 127.655 3.885 127.825 4.240 ;
        RECT 130.575 3.925 130.745 4.330 ;
        RECT 119.755 3.615 120.105 3.755 ;
        RECT 120.885 3.575 121.235 3.885 ;
        RECT 127.655 3.585 127.975 3.885 ;
        RECT 130.035 3.755 130.750 3.925 ;
        RECT 130.035 3.615 130.385 3.755 ;
        RECT 131.165 3.575 131.515 3.885 ;
        RECT 85.335 2.745 130.240 2.750 ;
        RECT 85.165 2.550 130.240 2.745 ;
        RECT 85.165 2.485 85.535 2.550 ;
        RECT 88.835 2.485 89.205 2.550 ;
        RECT 99.125 2.485 99.495 2.550 ;
        RECT 109.370 2.485 109.740 2.550 ;
        RECT 119.645 2.485 120.015 2.550 ;
        RECT 129.870 2.490 130.240 2.550 ;
      LAYER met2 ;
        RECT 8.315 19.390 8.685 19.600 ;
        RECT 93.880 19.545 94.640 19.745 ;
        RECT 8.315 19.220 55.410 19.390 ;
        RECT 58.455 19.220 64.295 19.390 ;
        RECT 93.880 19.325 95.905 19.545 ;
        RECT 55.240 19.050 58.625 19.220 ;
        RECT 30.920 18.645 31.250 18.905 ;
        RECT 6.405 18.125 6.785 18.325 ;
        RECT 10.730 18.205 11.100 18.585 ;
        RECT 22.720 18.235 23.090 18.615 ;
        RECT 25.145 18.275 25.475 18.535 ;
        RECT 4.550 17.965 6.785 18.125 ;
        RECT 9.775 17.990 10.145 18.200 ;
        RECT 4.040 17.955 6.785 17.965 ;
        RECT 4.040 17.795 4.725 17.955 ;
        RECT 9.005 17.820 10.145 17.990 ;
        RECT 2.685 13.825 3.430 13.995 ;
        RECT 4.040 13.940 4.210 17.795 ;
        RECT 5.535 17.275 5.915 17.645 ;
        RECT 4.010 13.560 4.690 13.940 ;
        RECT 4.040 11.020 4.210 13.560 ;
        RECT 4.040 10.815 4.610 11.020 ;
        RECT 4.240 10.640 4.610 10.815 ;
        RECT 5.535 10.075 5.705 17.275 ;
        RECT 5.960 14.215 6.330 14.595 ;
        RECT 9.005 14.305 9.175 17.820 ;
        RECT 10.790 14.305 10.960 18.205 ;
        RECT 11.440 14.725 11.820 14.780 ;
        RECT 13.215 14.725 13.595 14.780 ;
        RECT 11.440 14.555 13.595 14.725 ;
        RECT 11.440 14.410 11.820 14.555 ;
        RECT 13.215 14.410 13.595 14.555 ;
        RECT 22.825 14.315 22.995 18.235 ;
        RECT 25.300 14.315 25.470 18.275 ;
        RECT 31.080 14.620 31.250 18.645 ;
        RECT 34.310 18.590 34.570 18.920 ;
        RECT 36.245 18.775 38.410 18.945 ;
        RECT 56.860 18.775 57.190 18.865 ;
        RECT 34.355 14.905 34.525 18.590 ;
        RECT 30.920 14.360 31.250 14.620 ;
        RECT 34.310 14.575 34.570 14.905 ;
        RECT 6.160 13.715 6.330 14.215 ;
        RECT 8.825 13.925 9.195 14.305 ;
        RECT 10.730 13.925 11.100 14.305 ;
        RECT 22.720 13.935 23.090 14.315 ;
        RECT 25.125 13.935 25.495 14.315 ;
        RECT 10.790 13.715 10.960 13.925 ;
        RECT 6.160 13.545 10.960 13.715 ;
        RECT 6.475 13.165 6.855 13.365 ;
        RECT 6.130 12.995 6.855 13.165 ;
        RECT 6.130 10.075 6.300 12.995 ;
        RECT 4.990 9.905 5.705 10.075 ;
        RECT 4.990 9.870 5.360 9.905 ;
        RECT 5.535 9.900 5.705 9.905 ;
        RECT 2.155 9.370 2.525 9.750 ;
        RECT 4.675 9.700 5.360 9.870 ;
        RECT 2.290 5.190 2.460 9.370 ;
        RECT 4.675 5.775 4.845 9.700 ;
        RECT 4.990 9.695 5.360 9.700 ;
        RECT 5.930 9.695 6.300 10.075 ;
        RECT 10.790 10.035 10.960 13.545 ;
        RECT 22.825 12.090 22.995 13.935 ;
        RECT 25.240 12.090 25.410 13.935 ;
        RECT 22.825 11.920 25.410 12.090 ;
        RECT 5.930 9.235 6.100 9.695 ;
        RECT 5.550 9.065 6.100 9.235 ;
        RECT 6.450 9.290 6.820 9.670 ;
        RECT 10.730 9.655 11.100 10.035 ;
        RECT 22.825 9.925 22.995 11.920 ;
        RECT 25.240 10.025 25.410 11.920 ;
        RECT 31.080 10.360 31.250 14.360 ;
        RECT 36.245 14.085 36.415 18.775 ;
        RECT 38.240 18.335 38.410 18.775 ;
        RECT 56.425 18.605 57.190 18.775 ;
        RECT 38.240 18.005 38.500 18.335 ;
        RECT 39.135 18.100 39.395 18.260 ;
        RECT 39.135 17.930 42.960 18.100 ;
        RECT 36.160 13.755 36.420 14.085 ;
        RECT 38.605 14.030 38.935 14.120 ;
        RECT 38.605 13.860 39.290 14.030 ;
        RECT 30.920 10.100 31.250 10.360 ;
        RECT 5.550 5.775 5.720 9.065 ;
        RECT 6.450 8.825 6.620 9.290 ;
        RECT 6.125 8.655 6.620 8.825 ;
        RECT 6.125 5.775 6.295 8.655 ;
        RECT 10.790 5.775 10.960 9.655 ;
        RECT 22.720 9.545 23.090 9.925 ;
        RECT 25.135 9.625 25.480 10.025 ;
        RECT 4.495 5.395 4.865 5.775 ;
        RECT 5.370 5.395 5.740 5.775 ;
        RECT 5.925 5.395 6.295 5.775 ;
        RECT 6.455 5.190 6.825 5.445 ;
        RECT 10.730 5.395 11.100 5.775 ;
        RECT 22.825 5.735 22.995 9.545 ;
        RECT 22.720 5.355 23.090 5.735 ;
        RECT 25.300 5.725 25.470 9.625 ;
        RECT 31.080 6.090 31.250 10.100 ;
        RECT 36.245 9.840 36.415 13.755 ;
        RECT 39.120 11.030 39.290 13.860 ;
        RECT 38.960 10.770 39.290 11.030 ;
        RECT 36.160 9.510 36.420 9.840 ;
        RECT 38.605 9.520 38.935 9.780 ;
        RECT 30.920 5.830 31.250 6.090 ;
        RECT 25.145 5.465 25.475 5.725 ;
        RECT 36.245 5.535 36.415 9.510 ;
        RECT 36.160 5.205 36.420 5.535 ;
        RECT 2.290 5.020 6.825 5.190 ;
        RECT 39.665 4.820 39.965 17.730 ;
        RECT 42.475 15.395 42.645 17.930 ;
        RECT 49.450 17.855 50.010 18.175 ;
        RECT 42.475 15.065 42.735 15.395 ;
        RECT 55.480 14.910 55.740 15.070 ;
        RECT 55.480 14.740 56.135 14.910 ;
        RECT 51.540 14.360 51.870 14.620 ;
        RECT 54.915 14.535 55.175 14.695 ;
        RECT 53.900 14.365 55.175 14.535 ;
        RECT 41.635 14.150 41.965 14.210 ;
        RECT 40.975 13.780 41.235 14.035 ;
        RECT 41.635 13.980 44.620 14.150 ;
        RECT 41.635 13.950 41.965 13.980 ;
        RECT 40.975 13.610 44.085 13.780 ;
        RECT 42.425 13.245 42.755 13.340 ;
        RECT 42.425 13.080 43.620 13.245 ;
        RECT 42.540 13.075 43.620 13.080 ;
        RECT 42.845 10.765 43.175 11.025 ;
        RECT 40.975 9.480 41.235 9.810 ;
        RECT 39.545 4.510 40.080 4.820 ;
        RECT 41.065 4.755 41.235 9.480 ;
        RECT 42.345 8.980 42.675 9.240 ;
        RECT 42.465 5.380 42.635 8.980 ;
        RECT 43.005 5.385 43.175 10.765 ;
        RECT 43.440 10.340 43.610 13.075 ;
        RECT 43.420 10.010 43.680 10.340 ;
        RECT 43.005 5.380 43.520 5.385 ;
        RECT 43.915 5.380 44.085 13.610 ;
        RECT 44.445 6.865 44.615 13.980 ;
        RECT 45.715 13.775 46.275 14.095 ;
        RECT 51.695 10.345 51.865 14.360 ;
        RECT 53.900 10.425 54.070 14.365 ;
        RECT 55.480 13.920 55.740 14.080 ;
        RECT 55.015 13.750 55.740 13.920 ;
        RECT 53.035 10.345 53.365 10.375 ;
        RECT 51.695 10.175 53.365 10.345 ;
        RECT 53.035 10.115 53.365 10.175 ;
        RECT 51.925 9.645 52.485 9.965 ;
        RECT 53.195 9.940 53.365 10.115 ;
        RECT 53.850 10.095 54.110 10.425 ;
        RECT 54.470 10.115 54.800 10.375 ;
        RECT 54.470 9.940 54.640 10.115 ;
        RECT 53.195 9.770 54.640 9.940 ;
        RECT 44.395 6.535 44.655 6.865 ;
        RECT 47.260 6.245 47.520 6.575 ;
        RECT 55.015 6.510 55.185 13.750 ;
        RECT 55.965 9.855 56.135 14.740 ;
        RECT 56.425 14.080 56.595 18.605 ;
        RECT 60.195 18.420 60.525 18.535 ;
        RECT 58.305 18.275 60.525 18.420 ;
        RECT 56.335 13.750 56.595 14.080 ;
        RECT 57.710 13.750 57.970 14.080 ;
        RECT 56.960 13.580 57.970 13.750 ;
        RECT 56.960 9.865 57.130 13.580 ;
        RECT 58.305 10.770 58.475 18.275 ;
        RECT 58.715 13.930 58.975 14.080 ;
        RECT 61.195 13.965 61.455 14.295 ;
        RECT 58.715 13.760 59.500 13.930 ;
        RECT 58.715 13.750 58.975 13.760 ;
        RECT 57.820 10.600 58.475 10.770 ;
        RECT 57.820 10.440 58.080 10.600 ;
        RECT 55.370 9.685 56.135 9.855 ;
        RECT 55.370 9.595 55.700 9.685 ;
        RECT 56.835 9.535 57.235 9.865 ;
        RECT 56.305 8.865 56.635 8.900 ;
        RECT 57.860 8.865 58.030 10.440 ;
        RECT 59.330 10.290 59.500 13.760 ;
        RECT 60.705 12.860 60.965 13.190 ;
        RECT 60.705 12.075 60.885 12.860 ;
        RECT 61.285 12.075 61.455 13.965 ;
        RECT 60.705 11.905 61.455 12.075 ;
        RECT 59.260 9.960 59.520 10.290 ;
        RECT 61.285 10.030 61.455 11.905 ;
        RECT 61.195 9.700 61.455 10.030 ;
        RECT 64.125 10.010 64.295 19.220 ;
        RECT 95.705 17.145 95.905 19.325 ;
        RECT 101.680 19.185 101.950 19.655 ;
        RECT 113.905 19.185 114.175 19.655 ;
        RECT 126.170 19.185 126.440 19.655 ;
        RECT 138.420 19.185 138.690 19.655 ;
        RECT 96.580 19.045 107.050 19.185 ;
        RECT 108.805 19.045 119.275 19.185 ;
        RECT 121.070 19.045 131.540 19.185 ;
        RECT 133.320 19.045 143.790 19.185 ;
        RECT 101.680 18.625 101.950 19.045 ;
        RECT 113.905 18.625 114.175 19.045 ;
        RECT 126.170 18.625 126.440 19.045 ;
        RECT 138.420 18.625 138.690 19.045 ;
        RECT 96.580 18.485 107.050 18.625 ;
        RECT 108.805 18.485 119.275 18.625 ;
        RECT 121.070 18.485 131.540 18.625 ;
        RECT 133.320 18.485 143.790 18.625 ;
        RECT 101.680 18.065 101.950 18.485 ;
        RECT 113.905 18.065 114.175 18.485 ;
        RECT 126.170 18.065 126.440 18.485 ;
        RECT 138.420 18.065 138.690 18.485 ;
        RECT 96.580 17.925 107.050 18.065 ;
        RECT 108.805 17.925 119.275 18.065 ;
        RECT 121.070 17.925 131.540 18.065 ;
        RECT 133.320 17.925 143.790 18.065 ;
        RECT 101.680 17.505 101.950 17.925 ;
        RECT 113.905 17.505 114.175 17.925 ;
        RECT 126.170 17.505 126.440 17.925 ;
        RECT 138.420 17.505 138.690 17.925 ;
        RECT 96.580 17.365 107.050 17.505 ;
        RECT 108.805 17.365 119.275 17.505 ;
        RECT 121.070 17.365 131.540 17.505 ;
        RECT 133.320 17.365 143.790 17.505 ;
        RECT 95.490 16.385 95.910 17.145 ;
        RECT 101.680 16.945 101.950 17.365 ;
        RECT 113.905 16.945 114.175 17.365 ;
        RECT 126.170 16.945 126.440 17.365 ;
        RECT 138.420 16.945 138.690 17.365 ;
        RECT 96.580 16.805 107.050 16.945 ;
        RECT 108.805 16.805 119.275 16.945 ;
        RECT 121.070 16.805 131.540 16.945 ;
        RECT 133.320 16.805 143.790 16.945 ;
        RECT 101.680 16.385 101.950 16.805 ;
        RECT 113.905 16.385 114.175 16.805 ;
        RECT 126.170 16.385 126.440 16.805 ;
        RECT 138.420 16.385 138.690 16.805 ;
        RECT 93.700 15.720 94.195 16.260 ;
        RECT 64.125 9.840 65.340 10.010 ;
        RECT 56.305 8.695 58.030 8.865 ;
        RECT 56.305 8.640 56.635 8.695 ;
        RECT 51.590 6.340 55.185 6.510 ;
        RECT 51.590 6.250 51.920 6.340 ;
        RECT 42.460 5.050 42.725 5.380 ;
        RECT 43.005 5.215 43.685 5.380 ;
        RECT 43.425 5.050 43.685 5.215 ;
        RECT 43.915 5.050 44.175 5.380 ;
        RECT 47.260 4.755 47.430 6.245 ;
        RECT 57.860 5.755 58.030 8.695 ;
        RECT 64.895 9.680 65.340 9.840 ;
        RECT 64.895 6.170 65.065 9.680 ;
        RECT 93.650 9.425 94.050 9.545 ;
        RECT 95.705 9.425 95.905 16.385 ;
        RECT 96.580 16.245 107.050 16.385 ;
        RECT 108.805 16.245 119.275 16.385 ;
        RECT 121.070 16.245 131.540 16.385 ;
        RECT 133.320 16.245 143.790 16.385 ;
        RECT 101.680 15.825 101.950 16.245 ;
        RECT 113.905 15.825 114.175 16.245 ;
        RECT 126.170 15.825 126.440 16.245 ;
        RECT 138.420 15.825 138.690 16.245 ;
        RECT 96.580 15.685 107.050 15.825 ;
        RECT 108.805 15.685 119.275 15.825 ;
        RECT 121.070 15.685 131.540 15.825 ;
        RECT 133.320 15.685 143.790 15.825 ;
        RECT 101.680 15.265 101.950 15.685 ;
        RECT 113.905 15.265 114.175 15.685 ;
        RECT 126.170 15.265 126.440 15.685 ;
        RECT 138.420 15.265 138.690 15.685 ;
        RECT 96.580 15.125 107.050 15.265 ;
        RECT 108.805 15.125 119.275 15.265 ;
        RECT 121.070 15.125 131.540 15.265 ;
        RECT 133.320 15.125 143.790 15.265 ;
        RECT 101.680 14.705 101.950 15.125 ;
        RECT 113.905 14.705 114.175 15.125 ;
        RECT 126.170 14.705 126.440 15.125 ;
        RECT 138.420 14.705 138.690 15.125 ;
        RECT 96.580 14.565 107.050 14.705 ;
        RECT 108.805 14.565 119.275 14.705 ;
        RECT 121.070 14.565 131.540 14.705 ;
        RECT 133.320 14.565 143.790 14.705 ;
        RECT 101.680 13.945 101.950 14.565 ;
        RECT 113.905 13.945 114.175 14.565 ;
        RECT 126.170 13.945 126.440 14.565 ;
        RECT 138.420 13.945 138.690 14.565 ;
        RECT 96.110 13.675 145.425 13.945 ;
        RECT 101.680 13.055 101.950 13.675 ;
        RECT 113.905 13.055 114.175 13.675 ;
        RECT 126.170 13.055 126.440 13.675 ;
        RECT 138.420 13.055 138.690 13.675 ;
        RECT 96.580 12.915 107.050 13.055 ;
        RECT 108.805 12.915 119.275 13.055 ;
        RECT 121.070 12.915 131.540 13.055 ;
        RECT 133.320 12.915 143.790 13.055 ;
        RECT 101.680 12.495 101.950 12.915 ;
        RECT 113.905 12.495 114.175 12.915 ;
        RECT 126.170 12.495 126.440 12.915 ;
        RECT 138.420 12.495 138.690 12.915 ;
        RECT 96.580 12.355 107.050 12.495 ;
        RECT 108.805 12.355 119.275 12.495 ;
        RECT 121.070 12.355 131.540 12.495 ;
        RECT 133.320 12.355 143.790 12.495 ;
        RECT 101.680 11.935 101.950 12.355 ;
        RECT 113.905 11.935 114.175 12.355 ;
        RECT 126.170 11.935 126.440 12.355 ;
        RECT 138.420 11.935 138.690 12.355 ;
        RECT 96.580 11.795 107.050 11.935 ;
        RECT 108.805 11.795 119.275 11.935 ;
        RECT 121.070 11.795 131.540 11.935 ;
        RECT 133.320 11.795 143.790 11.935 ;
        RECT 101.680 11.375 101.950 11.795 ;
        RECT 113.905 11.375 114.175 11.795 ;
        RECT 126.170 11.375 126.440 11.795 ;
        RECT 138.420 11.375 138.690 11.795 ;
        RECT 96.580 11.235 107.050 11.375 ;
        RECT 108.805 11.235 119.275 11.375 ;
        RECT 121.070 11.235 131.540 11.375 ;
        RECT 133.320 11.235 143.790 11.375 ;
        RECT 101.680 10.815 101.950 11.235 ;
        RECT 113.905 10.815 114.175 11.235 ;
        RECT 126.170 10.815 126.440 11.235 ;
        RECT 138.420 10.815 138.690 11.235 ;
        RECT 96.580 10.675 107.050 10.815 ;
        RECT 108.805 10.675 119.275 10.815 ;
        RECT 121.070 10.675 131.540 10.815 ;
        RECT 133.320 10.675 143.790 10.815 ;
        RECT 101.680 10.255 101.950 10.675 ;
        RECT 113.905 10.255 114.175 10.675 ;
        RECT 126.170 10.255 126.440 10.675 ;
        RECT 138.420 10.255 138.690 10.675 ;
        RECT 96.580 10.115 107.050 10.255 ;
        RECT 108.805 10.115 119.275 10.255 ;
        RECT 121.070 10.115 131.540 10.255 ;
        RECT 133.320 10.115 143.790 10.255 ;
        RECT 101.680 9.695 101.950 10.115 ;
        RECT 113.905 9.695 114.175 10.115 ;
        RECT 126.170 9.695 126.440 10.115 ;
        RECT 138.420 9.695 138.690 10.115 ;
        RECT 96.580 9.555 107.050 9.695 ;
        RECT 108.805 9.555 119.275 9.695 ;
        RECT 121.070 9.555 131.540 9.695 ;
        RECT 133.320 9.555 143.790 9.695 ;
        RECT 93.650 9.240 95.905 9.425 ;
        RECT 93.650 9.140 94.050 9.240 ;
        RECT 101.680 9.135 101.950 9.555 ;
        RECT 113.905 9.135 114.175 9.555 ;
        RECT 126.170 9.135 126.440 9.555 ;
        RECT 138.420 9.135 138.690 9.555 ;
        RECT 96.580 8.995 107.050 9.135 ;
        RECT 108.805 8.995 119.275 9.135 ;
        RECT 121.070 8.995 131.540 9.135 ;
        RECT 133.320 8.995 143.790 9.135 ;
        RECT 101.680 8.575 101.950 8.995 ;
        RECT 113.905 8.575 114.175 8.995 ;
        RECT 126.170 8.575 126.440 8.995 ;
        RECT 138.420 8.575 138.690 8.995 ;
        RECT 96.580 8.435 107.050 8.575 ;
        RECT 108.805 8.435 119.275 8.575 ;
        RECT 121.070 8.435 131.540 8.575 ;
        RECT 133.320 8.435 143.790 8.575 ;
        RECT 101.680 7.965 101.950 8.435 ;
        RECT 113.905 7.965 114.175 8.435 ;
        RECT 126.170 7.965 126.440 8.435 ;
        RECT 138.420 7.295 138.690 8.435 ;
        RECT 145.225 7.865 145.425 13.675 ;
        RECT 145.135 7.310 145.540 7.865 ;
        RECT 138.420 7.025 139.305 7.295 ;
        RECT 64.050 6.000 65.065 6.170 ;
        RECT 57.830 5.425 58.090 5.755 ;
        RECT 64.050 5.430 64.220 6.000 ;
        RECT 78.105 5.645 78.945 6.025 ;
        RECT 61.795 5.260 64.220 5.430 ;
        RECT 68.035 5.325 68.420 5.495 ;
        RECT 78.550 5.415 78.945 5.645 ;
        RECT 86.625 5.950 135.560 6.120 ;
        RECT 86.625 5.445 86.795 5.950 ;
        RECT 68.020 5.300 74.200 5.325 ;
        RECT 68.020 5.290 74.330 5.300 ;
        RECT 61.795 5.170 62.125 5.260 ;
        RECT 68.020 5.125 74.335 5.290 ;
        RECT 73.935 4.955 74.335 5.125 ;
        RECT 86.465 5.020 86.795 5.445 ;
        RECT 86.945 5.605 133.795 5.775 ;
        RECT 41.065 4.585 47.430 4.755 ;
        RECT 63.910 4.355 64.575 4.870 ;
        RECT 78.095 4.445 78.455 4.840 ;
        RECT 86.945 4.270 87.115 5.605 ;
        RECT 88.930 5.135 89.400 5.445 ;
        RECT 99.225 5.135 99.695 5.445 ;
        RECT 109.465 5.135 109.935 5.445 ;
        RECT 119.755 5.210 120.225 5.445 ;
        RECT 119.750 5.135 120.225 5.210 ;
        RECT 130.070 5.135 130.540 5.445 ;
        RECT 87.615 4.645 87.975 4.935 ;
        RECT 86.535 4.070 87.115 4.270 ;
        RECT 86.535 3.985 86.870 4.070 ;
        RECT 83.035 3.570 83.395 3.860 ;
        RECT 85.155 3.585 85.555 3.890 ;
        RECT 86.530 3.585 86.870 3.985 ;
        RECT 83.215 2.280 83.385 3.570 ;
        RECT 85.265 2.745 85.435 3.585 ;
        RECT 85.165 2.485 85.535 2.745 ;
        RECT 87.760 2.280 87.930 4.645 ;
        RECT 88.930 2.745 89.100 5.135 ;
        RECT 89.370 4.725 89.730 4.995 ;
        RECT 89.535 3.825 89.725 4.725 ;
        RECT 97.890 4.645 98.250 4.935 ;
        RECT 90.045 3.825 90.395 3.890 ;
        RECT 89.535 3.655 90.395 3.825 ;
        RECT 90.045 3.580 90.395 3.655 ;
        RECT 88.835 2.485 89.205 2.745 ;
        RECT 98.030 2.280 98.200 4.645 ;
        RECT 99.225 2.745 99.395 5.135 ;
        RECT 99.650 4.725 100.010 4.995 ;
        RECT 99.815 3.825 100.005 4.725 ;
        RECT 108.175 4.645 108.535 4.935 ;
        RECT 100.325 3.825 100.675 3.890 ;
        RECT 99.815 3.655 100.675 3.825 ;
        RECT 100.325 3.580 100.675 3.655 ;
        RECT 99.125 2.485 99.495 2.745 ;
        RECT 108.330 2.280 108.500 4.645 ;
        RECT 109.465 2.745 109.635 5.135 ;
        RECT 109.930 4.725 110.290 4.995 ;
        RECT 110.095 3.825 110.285 4.725 ;
        RECT 118.450 4.645 118.810 4.935 ;
        RECT 110.605 3.825 110.955 3.890 ;
        RECT 110.095 3.655 110.955 3.825 ;
        RECT 110.605 3.580 110.955 3.655 ;
        RECT 109.370 2.485 109.740 2.745 ;
        RECT 118.600 2.280 118.770 4.645 ;
        RECT 119.750 2.745 119.920 5.135 ;
        RECT 120.210 4.725 120.570 4.995 ;
        RECT 120.375 3.825 120.565 4.725 ;
        RECT 128.730 4.645 129.090 4.935 ;
        RECT 120.885 3.825 121.235 3.890 ;
        RECT 120.375 3.655 121.235 3.825 ;
        RECT 120.885 3.580 121.235 3.655 ;
        RECT 119.645 2.485 120.015 2.745 ;
        RECT 128.880 2.280 129.050 4.645 ;
        RECT 130.070 2.750 130.240 5.135 ;
        RECT 133.625 5.010 133.795 5.605 ;
        RECT 130.490 4.725 130.850 4.995 ;
        RECT 130.655 3.825 130.845 4.725 ;
        RECT 133.620 4.565 134.040 5.010 ;
        RECT 135.390 5.005 135.560 5.950 ;
        RECT 138.915 5.940 139.305 7.025 ;
        RECT 138.005 5.610 139.305 5.940 ;
        RECT 138.005 5.350 138.725 5.610 ;
        RECT 135.390 4.585 135.840 5.005 ;
        RECT 131.165 3.825 131.515 3.890 ;
        RECT 130.655 3.655 131.515 3.825 ;
        RECT 131.165 3.580 131.515 3.655 ;
        RECT 129.870 2.490 130.240 2.750 ;
        RECT 83.215 2.080 129.050 2.280 ;
      LAYER met3 ;
        RECT 39.540 17.595 40.100 17.690 ;
        RECT 49.450 17.595 50.010 18.220 ;
        RECT 39.540 17.295 50.010 17.595 ;
        RECT 70.340 17.230 74.005 17.235 ;
        RECT 70.340 16.935 93.730 17.230 ;
        RECT 25.125 13.935 25.495 14.315 ;
        RECT 25.195 13.475 25.495 13.935 ;
        RECT 39.510 14.065 40.070 14.140 ;
        RECT 45.715 14.065 46.275 14.140 ;
        RECT 39.510 13.765 46.275 14.065 ;
        RECT 39.510 13.745 40.070 13.765 ;
        RECT 45.715 13.745 46.275 13.765 ;
        RECT 39.510 13.475 39.860 13.745 ;
        RECT 25.195 13.175 39.860 13.475 ;
        RECT 51.925 9.960 52.485 10.010 ;
        RECT 39.765 9.740 52.485 9.960 ;
        RECT 39.510 9.660 52.485 9.740 ;
        RECT 39.510 9.345 40.070 9.660 ;
        RECT 51.925 9.615 52.485 9.660 ;
        RECT 56.805 9.850 57.265 9.865 ;
        RECT 70.340 9.850 70.640 16.935 ;
        RECT 73.070 16.930 93.730 16.935 ;
        RECT 93.430 16.320 93.730 16.930 ;
        RECT 93.430 15.820 94.200 16.320 ;
        RECT 56.805 9.550 70.640 9.850 ;
        RECT 56.805 9.535 57.265 9.550 ;
        RECT 78.450 5.870 79.020 5.905 ;
        RECT 78.450 5.605 79.140 5.870 ;
        RECT 78.455 5.225 79.140 5.605 ;
        RECT 39.535 4.780 40.095 4.875 ;
        RECT 63.910 4.780 64.575 5.000 ;
        RECT 78.840 4.950 79.140 5.225 ;
        RECT 86.400 4.990 86.890 5.530 ;
        RECT 86.400 4.950 86.700 4.990 ;
        RECT 39.535 4.485 64.575 4.780 ;
        RECT 39.535 4.480 64.275 4.485 ;
        RECT 78.005 4.350 78.520 4.905 ;
        RECT 78.840 4.870 86.700 4.950 ;
        RECT 78.840 4.650 86.690 4.870 ;
        RECT 78.215 4.050 86.955 4.350 ;
        RECT 86.465 3.790 86.955 4.050 ;
  END
END pll
END LIBRARY

